VERSION 5.8 ;
BUSBITCHARS "[]" ;
DIVIDERCHAR "/" ;
UNITS
    DATABASE MICRONS 1000 ;
END UNITS

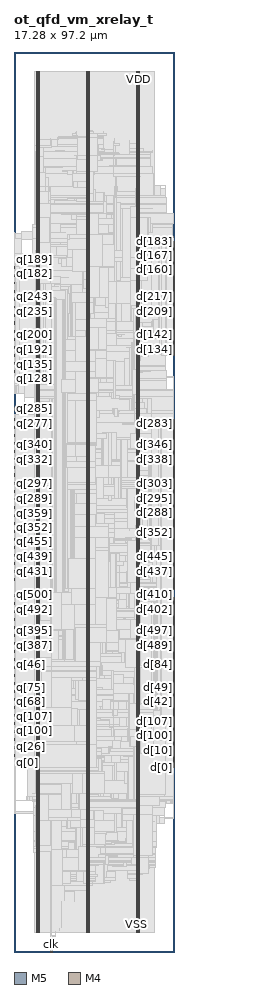
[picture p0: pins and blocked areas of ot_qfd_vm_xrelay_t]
MACRO ot_qfd_vm_xrelay_t
  FOREIGN ot_qfd_vm_xrelay_t 0 0 ;
  CLASS BLOCK ;
  SIZE 17.28 BY 97.2 ;
  PIN clk
    DIRECTION INPUT ;
    USE SIGNAL ;
    PORT
      LAYER M5 ;
        RECT  3.984 0 4.008 0.084 ;
    END
  END clk
  PIN d[0]
    DIRECTION INPUT ;
    USE SIGNAL ;
    PORT
      LAYER M4 ;
        RECT  17.196 19.92 17.28 19.944 ;
    END
  END d[0]
  PIN d[100]
    DIRECTION INPUT ;
    USE SIGNAL ;
    PORT
      LAYER M4 ;
        RECT  17.196 23.376 17.28 23.4 ;
    END
  END d[100]
  PIN d[101]
    DIRECTION INPUT ;
    USE SIGNAL ;
    PORT
      LAYER M4 ;
        RECT  17.196 23.472 17.28 23.496 ;
    END
  END d[101]
  PIN d[102]
    DIRECTION INPUT ;
    USE SIGNAL ;
    PORT
      LAYER M4 ;
        RECT  17.196 23.568 17.28 23.592 ;
    END
  END d[102]
  PIN d[103]
    DIRECTION INPUT ;
    USE SIGNAL ;
    PORT
      LAYER M4 ;
        RECT  17.196 23.664 17.28 23.688 ;
    END
  END d[103]
  PIN d[104]
    DIRECTION INPUT ;
    USE SIGNAL ;
    PORT
      LAYER M4 ;
        RECT  17.196 23.76 17.28 23.784 ;
    END
  END d[104]
  PIN d[105]
    DIRECTION INPUT ;
    USE SIGNAL ;
    PORT
      LAYER M4 ;
        RECT  17.196 23.856 17.28 23.88 ;
    END
  END d[105]
  PIN d[106]
    DIRECTION INPUT ;
    USE SIGNAL ;
    PORT
      LAYER M4 ;
        RECT  17.196 23.952 17.28 23.976 ;
    END
  END d[106]
  PIN d[107]
    DIRECTION INPUT ;
    USE SIGNAL ;
    PORT
      LAYER M4 ;
        RECT  17.196 24.048 17.28 24.072 ;
    END
  END d[107]
  PIN d[108]
    DIRECTION INPUT ;
    USE SIGNAL ;
    PORT
      LAYER M4 ;
        RECT  17.196 24.144 17.28 24.168 ;
    END
  END d[108]
  PIN d[109]
    DIRECTION INPUT ;
    USE SIGNAL ;
    PORT
      LAYER M4 ;
        RECT  17.196 24.24 17.28 24.264 ;
    END
  END d[109]
  PIN d[10]
    DIRECTION INPUT ;
    USE SIGNAL ;
    PORT
      LAYER M4 ;
        RECT  17.196 20.88 17.28 20.904 ;
    END
  END d[10]
  PIN d[110]
    DIRECTION INPUT ;
    USE SIGNAL ;
    PORT
      LAYER M4 ;
        RECT  17.196 24.336 17.28 24.36 ;
    END
  END d[110]
  PIN d[111]
    DIRECTION INPUT ;
    USE SIGNAL ;
    PORT
      LAYER M4 ;
        RECT  17.196 24.432 17.28 24.456 ;
    END
  END d[111]
  PIN d[112]
    DIRECTION INPUT ;
    USE SIGNAL ;
    PORT
      LAYER M4 ;
        RECT  17.196 24.528 17.28 24.552 ;
    END
  END d[112]
  PIN d[113]
    DIRECTION INPUT ;
    USE SIGNAL ;
    PORT
      LAYER M4 ;
        RECT  17.196 24.624 17.28 24.648 ;
    END
  END d[113]
  PIN d[114]
    DIRECTION INPUT ;
    USE SIGNAL ;
    PORT
      LAYER M4 ;
        RECT  17.196 24.72 17.28 24.744 ;
    END
  END d[114]
  PIN d[115]
    DIRECTION INPUT ;
    USE SIGNAL ;
    PORT
      LAYER M4 ;
        RECT  17.196 24.816 17.28 24.84 ;
    END
  END d[115]
  PIN d[116]
    DIRECTION INPUT ;
    USE SIGNAL ;
    PORT
      LAYER M4 ;
        RECT  17.196 24.912 17.28 24.936 ;
    END
  END d[116]
  PIN d[117]
    DIRECTION INPUT ;
    USE SIGNAL ;
    PORT
      LAYER M4 ;
        RECT  17.196 25.008 17.28 25.032 ;
    END
  END d[117]
  PIN d[118]
    DIRECTION INPUT ;
    USE SIGNAL ;
    PORT
      LAYER M4 ;
        RECT  17.196 25.104 17.28 25.128 ;
    END
  END d[118]
  PIN d[119]
    DIRECTION INPUT ;
    USE SIGNAL ;
    PORT
      LAYER M4 ;
        RECT  17.196 25.2 17.28 25.224 ;
    END
  END d[119]
  PIN d[11]
    DIRECTION INPUT ;
    USE SIGNAL ;
    PORT
      LAYER M4 ;
        RECT  17.196 20.976 17.28 21 ;
    END
  END d[11]
  PIN d[120]
    DIRECTION INPUT ;
    USE SIGNAL ;
    PORT
      LAYER M4 ;
        RECT  17.196 25.296 17.28 25.32 ;
    END
  END d[120]
  PIN d[121]
    DIRECTION INPUT ;
    USE SIGNAL ;
    PORT
      LAYER M4 ;
        RECT  17.196 25.392 17.28 25.416 ;
    END
  END d[121]
  PIN d[122]
    DIRECTION INPUT ;
    USE SIGNAL ;
    PORT
      LAYER M4 ;
        RECT  17.196 25.488 17.28 25.512 ;
    END
  END d[122]
  PIN d[123]
    DIRECTION INPUT ;
    USE SIGNAL ;
    PORT
      LAYER M4 ;
        RECT  17.196 25.584 17.28 25.608 ;
    END
  END d[123]
  PIN d[124]
    DIRECTION INPUT ;
    USE SIGNAL ;
    PORT
      LAYER M4 ;
        RECT  17.196 25.68 17.28 25.704 ;
    END
  END d[124]
  PIN d[125]
    DIRECTION INPUT ;
    USE SIGNAL ;
    PORT
      LAYER M4 ;
        RECT  17.196 25.776 17.28 25.8 ;
    END
  END d[125]
  PIN d[126]
    DIRECTION INPUT ;
    USE SIGNAL ;
    PORT
      LAYER M4 ;
        RECT  17.196 25.872 17.28 25.896 ;
    END
  END d[126]
  PIN d[127]
    DIRECTION INPUT ;
    USE SIGNAL ;
    PORT
      LAYER M4 ;
        RECT  17.196 25.968 17.28 25.992 ;
    END
  END d[127]
  PIN d[128]
    DIRECTION INPUT ;
    USE SIGNAL ;
    PORT
      LAYER M4 ;
        RECT  17.196 64.464 17.28 64.488 ;
    END
  END d[128]
  PIN d[129]
    DIRECTION INPUT ;
    USE SIGNAL ;
    PORT
      LAYER M4 ;
        RECT  17.196 64.56 17.28 64.584 ;
    END
  END d[129]
  PIN d[12]
    DIRECTION INPUT ;
    USE SIGNAL ;
    PORT
      LAYER M4 ;
        RECT  17.196 21.072 17.28 21.096 ;
    END
  END d[12]
  PIN d[130]
    DIRECTION INPUT ;
    USE SIGNAL ;
    PORT
      LAYER M4 ;
        RECT  17.196 64.656 17.28 64.68 ;
    END
  END d[130]
  PIN d[131]
    DIRECTION INPUT ;
    USE SIGNAL ;
    PORT
      LAYER M4 ;
        RECT  17.196 64.752 17.28 64.776 ;
    END
  END d[131]
  PIN d[132]
    DIRECTION INPUT ;
    USE SIGNAL ;
    PORT
      LAYER M4 ;
        RECT  17.196 64.848 17.28 64.872 ;
    END
  END d[132]
  PIN d[133]
    DIRECTION INPUT ;
    USE SIGNAL ;
    PORT
      LAYER M4 ;
        RECT  17.196 64.944 17.28 64.968 ;
    END
  END d[133]
  PIN d[134]
    DIRECTION INPUT ;
    USE SIGNAL ;
    PORT
      LAYER M4 ;
        RECT  17.196 65.04 17.28 65.064 ;
    END
  END d[134]
  PIN d[135]
    DIRECTION INPUT ;
    USE SIGNAL ;
    PORT
      LAYER M4 ;
        RECT  17.196 65.136 17.28 65.16 ;
    END
  END d[135]
  PIN d[136]
    DIRECTION INPUT ;
    USE SIGNAL ;
    PORT
      LAYER M4 ;
        RECT  17.196 65.232 17.28 65.256 ;
    END
  END d[136]
  PIN d[137]
    DIRECTION INPUT ;
    USE SIGNAL ;
    PORT
      LAYER M4 ;
        RECT  17.196 65.328 17.28 65.352 ;
    END
  END d[137]
  PIN d[138]
    DIRECTION INPUT ;
    USE SIGNAL ;
    PORT
      LAYER M4 ;
        RECT  17.196 65.424 17.28 65.448 ;
    END
  END d[138]
  PIN d[139]
    DIRECTION INPUT ;
    USE SIGNAL ;
    PORT
      LAYER M4 ;
        RECT  17.196 65.52 17.28 65.544 ;
    END
  END d[139]
  PIN d[13]
    DIRECTION INPUT ;
    USE SIGNAL ;
    PORT
      LAYER M4 ;
        RECT  17.196 21.168 17.28 21.192 ;
    END
  END d[13]
  PIN d[140]
    DIRECTION INPUT ;
    USE SIGNAL ;
    PORT
      LAYER M4 ;
        RECT  17.196 65.616 17.28 65.64 ;
    END
  END d[140]
  PIN d[141]
    DIRECTION INPUT ;
    USE SIGNAL ;
    PORT
      LAYER M4 ;
        RECT  17.196 65.712 17.28 65.736 ;
    END
  END d[141]
  PIN d[142]
    DIRECTION INPUT ;
    USE SIGNAL ;
    PORT
      LAYER M4 ;
        RECT  17.196 65.808 17.28 65.832 ;
    END
  END d[142]
  PIN d[143]
    DIRECTION INPUT ;
    USE SIGNAL ;
    PORT
      LAYER M4 ;
        RECT  17.196 65.904 17.28 65.928 ;
    END
  END d[143]
  PIN d[144]
    DIRECTION INPUT ;
    USE SIGNAL ;
    PORT
      LAYER M4 ;
        RECT  17.196 66 17.28 66.024 ;
    END
  END d[144]
  PIN d[145]
    DIRECTION INPUT ;
    USE SIGNAL ;
    PORT
      LAYER M4 ;
        RECT  17.196 66.096 17.28 66.12 ;
    END
  END d[145]
  PIN d[146]
    DIRECTION INPUT ;
    USE SIGNAL ;
    PORT
      LAYER M4 ;
        RECT  17.196 66.192 17.28 66.216 ;
    END
  END d[146]
  PIN d[147]
    DIRECTION INPUT ;
    USE SIGNAL ;
    PORT
      LAYER M4 ;
        RECT  17.196 66.288 17.28 66.312 ;
    END
  END d[147]
  PIN d[148]
    DIRECTION INPUT ;
    USE SIGNAL ;
    PORT
      LAYER M4 ;
        RECT  17.196 66.384 17.28 66.408 ;
    END
  END d[148]
  PIN d[149]
    DIRECTION INPUT ;
    USE SIGNAL ;
    PORT
      LAYER M4 ;
        RECT  17.196 66.48 17.28 66.504 ;
    END
  END d[149]
  PIN d[14]
    DIRECTION INPUT ;
    USE SIGNAL ;
    PORT
      LAYER M4 ;
        RECT  17.196 21.264 17.28 21.288 ;
    END
  END d[14]
  PIN d[150]
    DIRECTION INPUT ;
    USE SIGNAL ;
    PORT
      LAYER M4 ;
        RECT  17.196 66.576 17.28 66.6 ;
    END
  END d[150]
  PIN d[151]
    DIRECTION INPUT ;
    USE SIGNAL ;
    PORT
      LAYER M4 ;
        RECT  17.196 66.672 17.28 66.696 ;
    END
  END d[151]
  PIN d[152]
    DIRECTION INPUT ;
    USE SIGNAL ;
    PORT
      LAYER M4 ;
        RECT  17.196 66.768 17.28 66.792 ;
    END
  END d[152]
  PIN d[153]
    DIRECTION INPUT ;
    USE SIGNAL ;
    PORT
      LAYER M4 ;
        RECT  17.196 66.864 17.28 66.888 ;
    END
  END d[153]
  PIN d[154]
    DIRECTION INPUT ;
    USE SIGNAL ;
    PORT
      LAYER M4 ;
        RECT  17.196 66.96 17.28 66.984 ;
    END
  END d[154]
  PIN d[155]
    DIRECTION INPUT ;
    USE SIGNAL ;
    PORT
      LAYER M4 ;
        RECT  17.196 67.056 17.28 67.08 ;
    END
  END d[155]
  PIN d[156]
    DIRECTION INPUT ;
    USE SIGNAL ;
    PORT
      LAYER M4 ;
        RECT  17.196 67.152 17.28 67.176 ;
    END
  END d[156]
  PIN d[157]
    DIRECTION INPUT ;
    USE SIGNAL ;
    PORT
      LAYER M4 ;
        RECT  17.196 67.248 17.28 67.272 ;
    END
  END d[157]
  PIN d[158]
    DIRECTION INPUT ;
    USE SIGNAL ;
    PORT
      LAYER M4 ;
        RECT  17.196 67.344 17.28 67.368 ;
    END
  END d[158]
  PIN d[159]
    DIRECTION INPUT ;
    USE SIGNAL ;
    PORT
      LAYER M4 ;
        RECT  17.196 67.44 17.28 67.464 ;
    END
  END d[159]
  PIN d[15]
    DIRECTION INPUT ;
    USE SIGNAL ;
    PORT
      LAYER M4 ;
        RECT  17.196 21.36 17.28 21.384 ;
    END
  END d[15]
  PIN d[160]
    DIRECTION INPUT ;
    USE SIGNAL ;
    PORT
      LAYER M4 ;
        RECT  17.196 73.68 17.28 73.704 ;
    END
  END d[160]
  PIN d[161]
    DIRECTION INPUT ;
    USE SIGNAL ;
    PORT
      LAYER M4 ;
        RECT  17.196 73.776 17.28 73.8 ;
    END
  END d[161]
  PIN d[162]
    DIRECTION INPUT ;
    USE SIGNAL ;
    PORT
      LAYER M4 ;
        RECT  17.196 73.872 17.28 73.896 ;
    END
  END d[162]
  PIN d[163]
    DIRECTION INPUT ;
    USE SIGNAL ;
    PORT
      LAYER M4 ;
        RECT  17.196 73.968 17.28 73.992 ;
    END
  END d[163]
  PIN d[164]
    DIRECTION INPUT ;
    USE SIGNAL ;
    PORT
      LAYER M4 ;
        RECT  17.196 74.064 17.28 74.088 ;
    END
  END d[164]
  PIN d[165]
    DIRECTION INPUT ;
    USE SIGNAL ;
    PORT
      LAYER M4 ;
        RECT  17.196 74.16 17.28 74.184 ;
    END
  END d[165]
  PIN d[166]
    DIRECTION INPUT ;
    USE SIGNAL ;
    PORT
      LAYER M4 ;
        RECT  17.196 74.256 17.28 74.28 ;
    END
  END d[166]
  PIN d[167]
    DIRECTION INPUT ;
    USE SIGNAL ;
    PORT
      LAYER M4 ;
        RECT  17.196 74.352 17.28 74.376 ;
    END
  END d[167]
  PIN d[168]
    DIRECTION INPUT ;
    USE SIGNAL ;
    PORT
      LAYER M4 ;
        RECT  17.196 74.448 17.28 74.472 ;
    END
  END d[168]
  PIN d[169]
    DIRECTION INPUT ;
    USE SIGNAL ;
    PORT
      LAYER M4 ;
        RECT  17.196 74.544 17.28 74.568 ;
    END
  END d[169]
  PIN d[16]
    DIRECTION INPUT ;
    USE SIGNAL ;
    PORT
      LAYER M4 ;
        RECT  17.196 21.456 17.28 21.48 ;
    END
  END d[16]
  PIN d[170]
    DIRECTION INPUT ;
    USE SIGNAL ;
    PORT
      LAYER M4 ;
        RECT  17.196 74.64 17.28 74.664 ;
    END
  END d[170]
  PIN d[171]
    DIRECTION INPUT ;
    USE SIGNAL ;
    PORT
      LAYER M4 ;
        RECT  17.196 74.736 17.28 74.76 ;
    END
  END d[171]
  PIN d[172]
    DIRECTION INPUT ;
    USE SIGNAL ;
    PORT
      LAYER M4 ;
        RECT  17.196 74.832 17.28 74.856 ;
    END
  END d[172]
  PIN d[173]
    DIRECTION INPUT ;
    USE SIGNAL ;
    PORT
      LAYER M4 ;
        RECT  17.196 74.928 17.28 74.952 ;
    END
  END d[173]
  PIN d[174]
    DIRECTION INPUT ;
    USE SIGNAL ;
    PORT
      LAYER M4 ;
        RECT  17.196 75.024 17.28 75.048 ;
    END
  END d[174]
  PIN d[175]
    DIRECTION INPUT ;
    USE SIGNAL ;
    PORT
      LAYER M4 ;
        RECT  17.196 75.12 17.28 75.144 ;
    END
  END d[175]
  PIN d[176]
    DIRECTION INPUT ;
    USE SIGNAL ;
    PORT
      LAYER M4 ;
        RECT  17.196 75.216 17.28 75.24 ;
    END
  END d[176]
  PIN d[177]
    DIRECTION INPUT ;
    USE SIGNAL ;
    PORT
      LAYER M4 ;
        RECT  17.196 75.312 17.28 75.336 ;
    END
  END d[177]
  PIN d[178]
    DIRECTION INPUT ;
    USE SIGNAL ;
    PORT
      LAYER M4 ;
        RECT  17.196 75.408 17.28 75.432 ;
    END
  END d[178]
  PIN d[179]
    DIRECTION INPUT ;
    USE SIGNAL ;
    PORT
      LAYER M4 ;
        RECT  17.196 75.504 17.28 75.528 ;
    END
  END d[179]
  PIN d[17]
    DIRECTION INPUT ;
    USE SIGNAL ;
    PORT
      LAYER M4 ;
        RECT  17.196 21.552 17.28 21.576 ;
    END
  END d[17]
  PIN d[180]
    DIRECTION INPUT ;
    USE SIGNAL ;
    PORT
      LAYER M4 ;
        RECT  17.196 75.6 17.28 75.624 ;
    END
  END d[180]
  PIN d[181]
    DIRECTION INPUT ;
    USE SIGNAL ;
    PORT
      LAYER M4 ;
        RECT  17.196 75.696 17.28 75.72 ;
    END
  END d[181]
  PIN d[182]
    DIRECTION INPUT ;
    USE SIGNAL ;
    PORT
      LAYER M4 ;
        RECT  17.196 75.792 17.28 75.816 ;
    END
  END d[182]
  PIN d[183]
    DIRECTION INPUT ;
    USE SIGNAL ;
    PORT
      LAYER M4 ;
        RECT  17.196 75.888 17.28 75.912 ;
    END
  END d[183]
  PIN d[184]
    DIRECTION INPUT ;
    USE SIGNAL ;
    PORT
      LAYER M4 ;
        RECT  17.196 75.984 17.28 76.008 ;
    END
  END d[184]
  PIN d[185]
    DIRECTION INPUT ;
    USE SIGNAL ;
    PORT
      LAYER M4 ;
        RECT  17.196 76.08 17.28 76.104 ;
    END
  END d[185]
  PIN d[186]
    DIRECTION INPUT ;
    USE SIGNAL ;
    PORT
      LAYER M4 ;
        RECT  17.196 76.176 17.28 76.2 ;
    END
  END d[186]
  PIN d[187]
    DIRECTION INPUT ;
    USE SIGNAL ;
    PORT
      LAYER M4 ;
        RECT  17.196 76.272 17.28 76.296 ;
    END
  END d[187]
  PIN d[188]
    DIRECTION INPUT ;
    USE SIGNAL ;
    PORT
      LAYER M4 ;
        RECT  17.196 76.368 17.28 76.392 ;
    END
  END d[188]
  PIN d[189]
    DIRECTION INPUT ;
    USE SIGNAL ;
    PORT
      LAYER M4 ;
        RECT  17.196 76.464 17.28 76.488 ;
    END
  END d[189]
  PIN d[18]
    DIRECTION INPUT ;
    USE SIGNAL ;
    PORT
      LAYER M4 ;
        RECT  17.196 21.648 17.28 21.672 ;
    END
  END d[18]
  PIN d[190]
    DIRECTION INPUT ;
    USE SIGNAL ;
    PORT
      LAYER M4 ;
        RECT  17.196 76.56 17.28 76.584 ;
    END
  END d[190]
  PIN d[191]
    DIRECTION INPUT ;
    USE SIGNAL ;
    PORT
      LAYER M4 ;
        RECT  17.196 76.656 17.28 76.68 ;
    END
  END d[191]
  PIN d[192]
    DIRECTION INPUT ;
    USE SIGNAL ;
    PORT
      LAYER M4 ;
        RECT  17.196 67.536 17.28 67.56 ;
    END
  END d[192]
  PIN d[193]
    DIRECTION INPUT ;
    USE SIGNAL ;
    PORT
      LAYER M4 ;
        RECT  17.196 67.632 17.28 67.656 ;
    END
  END d[193]
  PIN d[194]
    DIRECTION INPUT ;
    USE SIGNAL ;
    PORT
      LAYER M4 ;
        RECT  17.196 67.728 17.28 67.752 ;
    END
  END d[194]
  PIN d[195]
    DIRECTION INPUT ;
    USE SIGNAL ;
    PORT
      LAYER M4 ;
        RECT  17.196 67.824 17.28 67.848 ;
    END
  END d[195]
  PIN d[196]
    DIRECTION INPUT ;
    USE SIGNAL ;
    PORT
      LAYER M4 ;
        RECT  17.196 67.92 17.28 67.944 ;
    END
  END d[196]
  PIN d[197]
    DIRECTION INPUT ;
    USE SIGNAL ;
    PORT
      LAYER M4 ;
        RECT  17.196 68.016 17.28 68.04 ;
    END
  END d[197]
  PIN d[198]
    DIRECTION INPUT ;
    USE SIGNAL ;
    PORT
      LAYER M4 ;
        RECT  17.196 68.112 17.28 68.136 ;
    END
  END d[198]
  PIN d[199]
    DIRECTION INPUT ;
    USE SIGNAL ;
    PORT
      LAYER M4 ;
        RECT  17.196 68.208 17.28 68.232 ;
    END
  END d[199]
  PIN d[19]
    DIRECTION INPUT ;
    USE SIGNAL ;
    PORT
      LAYER M4 ;
        RECT  17.196 21.744 17.28 21.768 ;
    END
  END d[19]
  PIN d[1]
    DIRECTION INPUT ;
    USE SIGNAL ;
    PORT
      LAYER M4 ;
        RECT  17.196 20.016 17.28 20.04 ;
    END
  END d[1]
  PIN d[200]
    DIRECTION INPUT ;
    USE SIGNAL ;
    PORT
      LAYER M4 ;
        RECT  17.196 68.304 17.28 68.328 ;
    END
  END d[200]
  PIN d[201]
    DIRECTION INPUT ;
    USE SIGNAL ;
    PORT
      LAYER M4 ;
        RECT  17.196 68.4 17.28 68.424 ;
    END
  END d[201]
  PIN d[202]
    DIRECTION INPUT ;
    USE SIGNAL ;
    PORT
      LAYER M4 ;
        RECT  17.196 68.496 17.28 68.52 ;
    END
  END d[202]
  PIN d[203]
    DIRECTION INPUT ;
    USE SIGNAL ;
    PORT
      LAYER M4 ;
        RECT  17.196 68.592 17.28 68.616 ;
    END
  END d[203]
  PIN d[204]
    DIRECTION INPUT ;
    USE SIGNAL ;
    PORT
      LAYER M4 ;
        RECT  17.196 68.688 17.28 68.712 ;
    END
  END d[204]
  PIN d[205]
    DIRECTION INPUT ;
    USE SIGNAL ;
    PORT
      LAYER M4 ;
        RECT  17.196 68.784 17.28 68.808 ;
    END
  END d[205]
  PIN d[206]
    DIRECTION INPUT ;
    USE SIGNAL ;
    PORT
      LAYER M4 ;
        RECT  17.196 68.88 17.28 68.904 ;
    END
  END d[206]
  PIN d[207]
    DIRECTION INPUT ;
    USE SIGNAL ;
    PORT
      LAYER M4 ;
        RECT  17.196 68.976 17.28 69 ;
    END
  END d[207]
  PIN d[208]
    DIRECTION INPUT ;
    USE SIGNAL ;
    PORT
      LAYER M4 ;
        RECT  17.196 69.072 17.28 69.096 ;
    END
  END d[208]
  PIN d[209]
    DIRECTION INPUT ;
    USE SIGNAL ;
    PORT
      LAYER M4 ;
        RECT  17.196 69.168 17.28 69.192 ;
    END
  END d[209]
  PIN d[20]
    DIRECTION INPUT ;
    USE SIGNAL ;
    PORT
      LAYER M4 ;
        RECT  17.196 21.84 17.28 21.864 ;
    END
  END d[20]
  PIN d[210]
    DIRECTION INPUT ;
    USE SIGNAL ;
    PORT
      LAYER M4 ;
        RECT  17.196 69.264 17.28 69.288 ;
    END
  END d[210]
  PIN d[211]
    DIRECTION INPUT ;
    USE SIGNAL ;
    PORT
      LAYER M4 ;
        RECT  17.196 69.36 17.28 69.384 ;
    END
  END d[211]
  PIN d[212]
    DIRECTION INPUT ;
    USE SIGNAL ;
    PORT
      LAYER M4 ;
        RECT  17.196 69.456 17.28 69.48 ;
    END
  END d[212]
  PIN d[213]
    DIRECTION INPUT ;
    USE SIGNAL ;
    PORT
      LAYER M4 ;
        RECT  17.196 69.552 17.28 69.576 ;
    END
  END d[213]
  PIN d[214]
    DIRECTION INPUT ;
    USE SIGNAL ;
    PORT
      LAYER M4 ;
        RECT  17.196 69.648 17.28 69.672 ;
    END
  END d[214]
  PIN d[215]
    DIRECTION INPUT ;
    USE SIGNAL ;
    PORT
      LAYER M4 ;
        RECT  17.196 69.744 17.28 69.768 ;
    END
  END d[215]
  PIN d[216]
    DIRECTION INPUT ;
    USE SIGNAL ;
    PORT
      LAYER M4 ;
        RECT  17.196 69.84 17.28 69.864 ;
    END
  END d[216]
  PIN d[217]
    DIRECTION INPUT ;
    USE SIGNAL ;
    PORT
      LAYER M4 ;
        RECT  17.196 69.936 17.28 69.96 ;
    END
  END d[217]
  PIN d[218]
    DIRECTION INPUT ;
    USE SIGNAL ;
    PORT
      LAYER M4 ;
        RECT  17.196 70.032 17.28 70.056 ;
    END
  END d[218]
  PIN d[219]
    DIRECTION INPUT ;
    USE SIGNAL ;
    PORT
      LAYER M4 ;
        RECT  17.196 70.128 17.28 70.152 ;
    END
  END d[219]
  PIN d[21]
    DIRECTION INPUT ;
    USE SIGNAL ;
    PORT
      LAYER M4 ;
        RECT  17.196 21.936 17.28 21.96 ;
    END
  END d[21]
  PIN d[220]
    DIRECTION INPUT ;
    USE SIGNAL ;
    PORT
      LAYER M4 ;
        RECT  17.196 70.224 17.28 70.248 ;
    END
  END d[220]
  PIN d[221]
    DIRECTION INPUT ;
    USE SIGNAL ;
    PORT
      LAYER M4 ;
        RECT  17.196 70.32 17.28 70.344 ;
    END
  END d[221]
  PIN d[222]
    DIRECTION INPUT ;
    USE SIGNAL ;
    PORT
      LAYER M4 ;
        RECT  17.196 70.416 17.28 70.44 ;
    END
  END d[222]
  PIN d[223]
    DIRECTION INPUT ;
    USE SIGNAL ;
    PORT
      LAYER M4 ;
        RECT  17.196 70.512 17.28 70.536 ;
    END
  END d[223]
  PIN d[224]
    DIRECTION INPUT ;
    USE SIGNAL ;
    PORT
      LAYER M4 ;
        RECT  17.196 70.608 17.28 70.632 ;
    END
  END d[224]
  PIN d[225]
    DIRECTION INPUT ;
    USE SIGNAL ;
    PORT
      LAYER M4 ;
        RECT  17.196 70.704 17.28 70.728 ;
    END
  END d[225]
  PIN d[226]
    DIRECTION INPUT ;
    USE SIGNAL ;
    PORT
      LAYER M4 ;
        RECT  17.196 70.8 17.28 70.824 ;
    END
  END d[226]
  PIN d[227]
    DIRECTION INPUT ;
    USE SIGNAL ;
    PORT
      LAYER M4 ;
        RECT  17.196 70.896 17.28 70.92 ;
    END
  END d[227]
  PIN d[228]
    DIRECTION INPUT ;
    USE SIGNAL ;
    PORT
      LAYER M4 ;
        RECT  17.196 70.992 17.28 71.016 ;
    END
  END d[228]
  PIN d[229]
    DIRECTION INPUT ;
    USE SIGNAL ;
    PORT
      LAYER M4 ;
        RECT  17.196 71.088 17.28 71.112 ;
    END
  END d[229]
  PIN d[22]
    DIRECTION INPUT ;
    USE SIGNAL ;
    PORT
      LAYER M4 ;
        RECT  17.196 22.032 17.28 22.056 ;
    END
  END d[22]
  PIN d[230]
    DIRECTION INPUT ;
    USE SIGNAL ;
    PORT
      LAYER M4 ;
        RECT  17.196 71.184 17.28 71.208 ;
    END
  END d[230]
  PIN d[231]
    DIRECTION INPUT ;
    USE SIGNAL ;
    PORT
      LAYER M4 ;
        RECT  17.196 71.28 17.28 71.304 ;
    END
  END d[231]
  PIN d[232]
    DIRECTION INPUT ;
    USE SIGNAL ;
    PORT
      LAYER M4 ;
        RECT  17.196 71.376 17.28 71.4 ;
    END
  END d[232]
  PIN d[233]
    DIRECTION INPUT ;
    USE SIGNAL ;
    PORT
      LAYER M4 ;
        RECT  17.196 71.472 17.28 71.496 ;
    END
  END d[233]
  PIN d[234]
    DIRECTION INPUT ;
    USE SIGNAL ;
    PORT
      LAYER M4 ;
        RECT  17.196 71.568 17.28 71.592 ;
    END
  END d[234]
  PIN d[235]
    DIRECTION INPUT ;
    USE SIGNAL ;
    PORT
      LAYER M4 ;
        RECT  17.196 71.664 17.28 71.688 ;
    END
  END d[235]
  PIN d[236]
    DIRECTION INPUT ;
    USE SIGNAL ;
    PORT
      LAYER M4 ;
        RECT  17.196 71.76 17.28 71.784 ;
    END
  END d[236]
  PIN d[237]
    DIRECTION INPUT ;
    USE SIGNAL ;
    PORT
      LAYER M4 ;
        RECT  17.196 71.856 17.28 71.88 ;
    END
  END d[237]
  PIN d[238]
    DIRECTION INPUT ;
    USE SIGNAL ;
    PORT
      LAYER M4 ;
        RECT  17.196 71.952 17.28 71.976 ;
    END
  END d[238]
  PIN d[239]
    DIRECTION INPUT ;
    USE SIGNAL ;
    PORT
      LAYER M4 ;
        RECT  17.196 72.048 17.28 72.072 ;
    END
  END d[239]
  PIN d[23]
    DIRECTION INPUT ;
    USE SIGNAL ;
    PORT
      LAYER M4 ;
        RECT  17.196 22.128 17.28 22.152 ;
    END
  END d[23]
  PIN d[240]
    DIRECTION INPUT ;
    USE SIGNAL ;
    PORT
      LAYER M4 ;
        RECT  17.196 72.144 17.28 72.168 ;
    END
  END d[240]
  PIN d[241]
    DIRECTION INPUT ;
    USE SIGNAL ;
    PORT
      LAYER M4 ;
        RECT  17.196 72.24 17.28 72.264 ;
    END
  END d[241]
  PIN d[242]
    DIRECTION INPUT ;
    USE SIGNAL ;
    PORT
      LAYER M4 ;
        RECT  17.196 72.336 17.28 72.36 ;
    END
  END d[242]
  PIN d[243]
    DIRECTION INPUT ;
    USE SIGNAL ;
    PORT
      LAYER M4 ;
        RECT  17.196 72.432 17.28 72.456 ;
    END
  END d[243]
  PIN d[244]
    DIRECTION INPUT ;
    USE SIGNAL ;
    PORT
      LAYER M4 ;
        RECT  17.196 72.528 17.28 72.552 ;
    END
  END d[244]
  PIN d[245]
    DIRECTION INPUT ;
    USE SIGNAL ;
    PORT
      LAYER M4 ;
        RECT  17.196 72.624 17.28 72.648 ;
    END
  END d[245]
  PIN d[246]
    DIRECTION INPUT ;
    USE SIGNAL ;
    PORT
      LAYER M4 ;
        RECT  17.196 72.72 17.28 72.744 ;
    END
  END d[246]
  PIN d[247]
    DIRECTION INPUT ;
    USE SIGNAL ;
    PORT
      LAYER M4 ;
        RECT  17.196 72.816 17.28 72.84 ;
    END
  END d[247]
  PIN d[248]
    DIRECTION INPUT ;
    USE SIGNAL ;
    PORT
      LAYER M4 ;
        RECT  17.196 72.912 17.28 72.936 ;
    END
  END d[248]
  PIN d[249]
    DIRECTION INPUT ;
    USE SIGNAL ;
    PORT
      LAYER M4 ;
        RECT  17.196 73.008 17.28 73.032 ;
    END
  END d[249]
  PIN d[24]
    DIRECTION INPUT ;
    USE SIGNAL ;
    PORT
      LAYER M4 ;
        RECT  17.196 22.224 17.28 22.248 ;
    END
  END d[24]
  PIN d[250]
    DIRECTION INPUT ;
    USE SIGNAL ;
    PORT
      LAYER M4 ;
        RECT  17.196 73.104 17.28 73.128 ;
    END
  END d[250]
  PIN d[251]
    DIRECTION INPUT ;
    USE SIGNAL ;
    PORT
      LAYER M4 ;
        RECT  17.196 73.2 17.28 73.224 ;
    END
  END d[251]
  PIN d[252]
    DIRECTION INPUT ;
    USE SIGNAL ;
    PORT
      LAYER M4 ;
        RECT  17.196 73.296 17.28 73.32 ;
    END
  END d[252]
  PIN d[253]
    DIRECTION INPUT ;
    USE SIGNAL ;
    PORT
      LAYER M4 ;
        RECT  17.196 73.392 17.28 73.416 ;
    END
  END d[253]
  PIN d[254]
    DIRECTION INPUT ;
    USE SIGNAL ;
    PORT
      LAYER M4 ;
        RECT  17.196 73.488 17.28 73.512 ;
    END
  END d[254]
  PIN d[255]
    DIRECTION INPUT ;
    USE SIGNAL ;
    PORT
      LAYER M4 ;
        RECT  17.196 73.584 17.28 73.608 ;
    END
  END d[255]
  PIN d[256]
    DIRECTION INPUT ;
    USE SIGNAL ;
    PORT
      LAYER M4 ;
        RECT  17.196 54.48 17.28 54.504 ;
    END
  END d[256]
  PIN d[257]
    DIRECTION INPUT ;
    USE SIGNAL ;
    PORT
      LAYER M4 ;
        RECT  17.196 54.576 17.28 54.6 ;
    END
  END d[257]
  PIN d[258]
    DIRECTION INPUT ;
    USE SIGNAL ;
    PORT
      LAYER M4 ;
        RECT  17.196 54.672 17.28 54.696 ;
    END
  END d[258]
  PIN d[259]
    DIRECTION INPUT ;
    USE SIGNAL ;
    PORT
      LAYER M4 ;
        RECT  17.196 54.768 17.28 54.792 ;
    END
  END d[259]
  PIN d[25]
    DIRECTION INPUT ;
    USE SIGNAL ;
    PORT
      LAYER M4 ;
        RECT  17.196 22.32 17.28 22.344 ;
    END
  END d[25]
  PIN d[260]
    DIRECTION INPUT ;
    USE SIGNAL ;
    PORT
      LAYER M4 ;
        RECT  17.196 54.864 17.28 54.888 ;
    END
  END d[260]
  PIN d[261]
    DIRECTION INPUT ;
    USE SIGNAL ;
    PORT
      LAYER M4 ;
        RECT  17.196 54.96 17.28 54.984 ;
    END
  END d[261]
  PIN d[262]
    DIRECTION INPUT ;
    USE SIGNAL ;
    PORT
      LAYER M4 ;
        RECT  17.196 55.056 17.28 55.08 ;
    END
  END d[262]
  PIN d[263]
    DIRECTION INPUT ;
    USE SIGNAL ;
    PORT
      LAYER M4 ;
        RECT  17.196 55.152 17.28 55.176 ;
    END
  END d[263]
  PIN d[264]
    DIRECTION INPUT ;
    USE SIGNAL ;
    PORT
      LAYER M4 ;
        RECT  17.196 55.248 17.28 55.272 ;
    END
  END d[264]
  PIN d[265]
    DIRECTION INPUT ;
    USE SIGNAL ;
    PORT
      LAYER M4 ;
        RECT  17.196 55.344 17.28 55.368 ;
    END
  END d[265]
  PIN d[266]
    DIRECTION INPUT ;
    USE SIGNAL ;
    PORT
      LAYER M4 ;
        RECT  17.196 55.44 17.28 55.464 ;
    END
  END d[266]
  PIN d[267]
    DIRECTION INPUT ;
    USE SIGNAL ;
    PORT
      LAYER M4 ;
        RECT  17.196 55.536 17.28 55.56 ;
    END
  END d[267]
  PIN d[268]
    DIRECTION INPUT ;
    USE SIGNAL ;
    PORT
      LAYER M4 ;
        RECT  17.196 55.632 17.28 55.656 ;
    END
  END d[268]
  PIN d[269]
    DIRECTION INPUT ;
    USE SIGNAL ;
    PORT
      LAYER M4 ;
        RECT  17.196 55.728 17.28 55.752 ;
    END
  END d[269]
  PIN d[26]
    DIRECTION INPUT ;
    USE SIGNAL ;
    PORT
      LAYER M4 ;
        RECT  17.196 22.416 17.28 22.44 ;
    END
  END d[26]
  PIN d[270]
    DIRECTION INPUT ;
    USE SIGNAL ;
    PORT
      LAYER M4 ;
        RECT  17.196 55.824 17.28 55.848 ;
    END
  END d[270]
  PIN d[271]
    DIRECTION INPUT ;
    USE SIGNAL ;
    PORT
      LAYER M4 ;
        RECT  17.196 55.92 17.28 55.944 ;
    END
  END d[271]
  PIN d[272]
    DIRECTION INPUT ;
    USE SIGNAL ;
    PORT
      LAYER M4 ;
        RECT  17.196 56.016 17.28 56.04 ;
    END
  END d[272]
  PIN d[273]
    DIRECTION INPUT ;
    USE SIGNAL ;
    PORT
      LAYER M4 ;
        RECT  17.196 56.112 17.28 56.136 ;
    END
  END d[273]
  PIN d[274]
    DIRECTION INPUT ;
    USE SIGNAL ;
    PORT
      LAYER M4 ;
        RECT  17.196 56.208 17.28 56.232 ;
    END
  END d[274]
  PIN d[275]
    DIRECTION INPUT ;
    USE SIGNAL ;
    PORT
      LAYER M4 ;
        RECT  17.196 56.304 17.28 56.328 ;
    END
  END d[275]
  PIN d[276]
    DIRECTION INPUT ;
    USE SIGNAL ;
    PORT
      LAYER M4 ;
        RECT  17.196 56.4 17.28 56.424 ;
    END
  END d[276]
  PIN d[277]
    DIRECTION INPUT ;
    USE SIGNAL ;
    PORT
      LAYER M4 ;
        RECT  17.196 56.496 17.28 56.52 ;
    END
  END d[277]
  PIN d[278]
    DIRECTION INPUT ;
    USE SIGNAL ;
    PORT
      LAYER M4 ;
        RECT  17.196 56.592 17.28 56.616 ;
    END
  END d[278]
  PIN d[279]
    DIRECTION INPUT ;
    USE SIGNAL ;
    PORT
      LAYER M4 ;
        RECT  17.196 56.688 17.28 56.712 ;
    END
  END d[279]
  PIN d[27]
    DIRECTION INPUT ;
    USE SIGNAL ;
    PORT
      LAYER M4 ;
        RECT  17.196 22.512 17.28 22.536 ;
    END
  END d[27]
  PIN d[280]
    DIRECTION INPUT ;
    USE SIGNAL ;
    PORT
      LAYER M4 ;
        RECT  17.196 56.784 17.28 56.808 ;
    END
  END d[280]
  PIN d[281]
    DIRECTION INPUT ;
    USE SIGNAL ;
    PORT
      LAYER M4 ;
        RECT  17.196 56.88 17.28 56.904 ;
    END
  END d[281]
  PIN d[282]
    DIRECTION INPUT ;
    USE SIGNAL ;
    PORT
      LAYER M4 ;
        RECT  17.196 56.976 17.28 57 ;
    END
  END d[282]
  PIN d[283]
    DIRECTION INPUT ;
    USE SIGNAL ;
    PORT
      LAYER M4 ;
        RECT  17.196 57.072 17.28 57.096 ;
    END
  END d[283]
  PIN d[284]
    DIRECTION INPUT ;
    USE SIGNAL ;
    PORT
      LAYER M4 ;
        RECT  17.196 57.168 17.28 57.192 ;
    END
  END d[284]
  PIN d[285]
    DIRECTION INPUT ;
    USE SIGNAL ;
    PORT
      LAYER M4 ;
        RECT  17.196 57.264 17.28 57.288 ;
    END
  END d[285]
  PIN d[286]
    DIRECTION INPUT ;
    USE SIGNAL ;
    PORT
      LAYER M4 ;
        RECT  17.196 57.36 17.28 57.384 ;
    END
  END d[286]
  PIN d[287]
    DIRECTION INPUT ;
    USE SIGNAL ;
    PORT
      LAYER M4 ;
        RECT  17.196 57.456 17.28 57.48 ;
    END
  END d[287]
  PIN d[288]
    DIRECTION INPUT ;
    USE SIGNAL ;
    PORT
      LAYER M4 ;
        RECT  17.196 48.336 17.28 48.36 ;
    END
  END d[288]
  PIN d[289]
    DIRECTION INPUT ;
    USE SIGNAL ;
    PORT
      LAYER M4 ;
        RECT  17.196 48.432 17.28 48.456 ;
    END
  END d[289]
  PIN d[28]
    DIRECTION INPUT ;
    USE SIGNAL ;
    PORT
      LAYER M4 ;
        RECT  17.196 22.608 17.28 22.632 ;
    END
  END d[28]
  PIN d[290]
    DIRECTION INPUT ;
    USE SIGNAL ;
    PORT
      LAYER M4 ;
        RECT  17.196 48.528 17.28 48.552 ;
    END
  END d[290]
  PIN d[291]
    DIRECTION INPUT ;
    USE SIGNAL ;
    PORT
      LAYER M4 ;
        RECT  17.196 48.624 17.28 48.648 ;
    END
  END d[291]
  PIN d[292]
    DIRECTION INPUT ;
    USE SIGNAL ;
    PORT
      LAYER M4 ;
        RECT  17.196 48.72 17.28 48.744 ;
    END
  END d[292]
  PIN d[293]
    DIRECTION INPUT ;
    USE SIGNAL ;
    PORT
      LAYER M4 ;
        RECT  17.196 48.816 17.28 48.84 ;
    END
  END d[293]
  PIN d[294]
    DIRECTION INPUT ;
    USE SIGNAL ;
    PORT
      LAYER M4 ;
        RECT  17.196 48.912 17.28 48.936 ;
    END
  END d[294]
  PIN d[295]
    DIRECTION INPUT ;
    USE SIGNAL ;
    PORT
      LAYER M4 ;
        RECT  17.196 49.008 17.28 49.032 ;
    END
  END d[295]
  PIN d[296]
    DIRECTION INPUT ;
    USE SIGNAL ;
    PORT
      LAYER M4 ;
        RECT  17.196 49.104 17.28 49.128 ;
    END
  END d[296]
  PIN d[297]
    DIRECTION INPUT ;
    USE SIGNAL ;
    PORT
      LAYER M4 ;
        RECT  17.196 49.2 17.28 49.224 ;
    END
  END d[297]
  PIN d[298]
    DIRECTION INPUT ;
    USE SIGNAL ;
    PORT
      LAYER M4 ;
        RECT  17.196 49.296 17.28 49.32 ;
    END
  END d[298]
  PIN d[299]
    DIRECTION INPUT ;
    USE SIGNAL ;
    PORT
      LAYER M4 ;
        RECT  17.196 49.392 17.28 49.416 ;
    END
  END d[299]
  PIN d[29]
    DIRECTION INPUT ;
    USE SIGNAL ;
    PORT
      LAYER M4 ;
        RECT  17.196 22.704 17.28 22.728 ;
    END
  END d[29]
  PIN d[2]
    DIRECTION INPUT ;
    USE SIGNAL ;
    PORT
      LAYER M4 ;
        RECT  17.196 20.112 17.28 20.136 ;
    END
  END d[2]
  PIN d[300]
    DIRECTION INPUT ;
    USE SIGNAL ;
    PORT
      LAYER M4 ;
        RECT  17.196 49.488 17.28 49.512 ;
    END
  END d[300]
  PIN d[301]
    DIRECTION INPUT ;
    USE SIGNAL ;
    PORT
      LAYER M4 ;
        RECT  17.196 49.584 17.28 49.608 ;
    END
  END d[301]
  PIN d[302]
    DIRECTION INPUT ;
    USE SIGNAL ;
    PORT
      LAYER M4 ;
        RECT  17.196 49.68 17.28 49.704 ;
    END
  END d[302]
  PIN d[303]
    DIRECTION INPUT ;
    USE SIGNAL ;
    PORT
      LAYER M4 ;
        RECT  17.196 49.776 17.28 49.8 ;
    END
  END d[303]
  PIN d[304]
    DIRECTION INPUT ;
    USE SIGNAL ;
    PORT
      LAYER M4 ;
        RECT  17.196 49.872 17.28 49.896 ;
    END
  END d[304]
  PIN d[305]
    DIRECTION INPUT ;
    USE SIGNAL ;
    PORT
      LAYER M4 ;
        RECT  17.196 49.968 17.28 49.992 ;
    END
  END d[305]
  PIN d[306]
    DIRECTION INPUT ;
    USE SIGNAL ;
    PORT
      LAYER M4 ;
        RECT  17.196 50.064 17.28 50.088 ;
    END
  END d[306]
  PIN d[307]
    DIRECTION INPUT ;
    USE SIGNAL ;
    PORT
      LAYER M4 ;
        RECT  17.196 50.16 17.28 50.184 ;
    END
  END d[307]
  PIN d[308]
    DIRECTION INPUT ;
    USE SIGNAL ;
    PORT
      LAYER M4 ;
        RECT  17.196 50.256 17.28 50.28 ;
    END
  END d[308]
  PIN d[309]
    DIRECTION INPUT ;
    USE SIGNAL ;
    PORT
      LAYER M4 ;
        RECT  17.196 50.352 17.28 50.376 ;
    END
  END d[309]
  PIN d[30]
    DIRECTION INPUT ;
    USE SIGNAL ;
    PORT
      LAYER M4 ;
        RECT  17.196 22.8 17.28 22.824 ;
    END
  END d[30]
  PIN d[310]
    DIRECTION INPUT ;
    USE SIGNAL ;
    PORT
      LAYER M4 ;
        RECT  17.196 50.448 17.28 50.472 ;
    END
  END d[310]
  PIN d[311]
    DIRECTION INPUT ;
    USE SIGNAL ;
    PORT
      LAYER M4 ;
        RECT  17.196 50.544 17.28 50.568 ;
    END
  END d[311]
  PIN d[312]
    DIRECTION INPUT ;
    USE SIGNAL ;
    PORT
      LAYER M4 ;
        RECT  17.196 50.64 17.28 50.664 ;
    END
  END d[312]
  PIN d[313]
    DIRECTION INPUT ;
    USE SIGNAL ;
    PORT
      LAYER M4 ;
        RECT  17.196 50.736 17.28 50.76 ;
    END
  END d[313]
  PIN d[314]
    DIRECTION INPUT ;
    USE SIGNAL ;
    PORT
      LAYER M4 ;
        RECT  17.196 50.832 17.28 50.856 ;
    END
  END d[314]
  PIN d[315]
    DIRECTION INPUT ;
    USE SIGNAL ;
    PORT
      LAYER M4 ;
        RECT  17.196 50.928 17.28 50.952 ;
    END
  END d[315]
  PIN d[316]
    DIRECTION INPUT ;
    USE SIGNAL ;
    PORT
      LAYER M4 ;
        RECT  17.196 51.024 17.28 51.048 ;
    END
  END d[316]
  PIN d[317]
    DIRECTION INPUT ;
    USE SIGNAL ;
    PORT
      LAYER M4 ;
        RECT  17.196 51.12 17.28 51.144 ;
    END
  END d[317]
  PIN d[318]
    DIRECTION INPUT ;
    USE SIGNAL ;
    PORT
      LAYER M4 ;
        RECT  17.196 51.216 17.28 51.24 ;
    END
  END d[318]
  PIN d[319]
    DIRECTION INPUT ;
    USE SIGNAL ;
    PORT
      LAYER M4 ;
        RECT  17.196 51.312 17.28 51.336 ;
    END
  END d[319]
  PIN d[31]
    DIRECTION INPUT ;
    USE SIGNAL ;
    PORT
      LAYER M4 ;
        RECT  17.196 22.896 17.28 22.92 ;
    END
  END d[31]
  PIN d[320]
    DIRECTION INPUT ;
    USE SIGNAL ;
    PORT
      LAYER M4 ;
        RECT  17.196 51.408 17.28 51.432 ;
    END
  END d[320]
  PIN d[321]
    DIRECTION INPUT ;
    USE SIGNAL ;
    PORT
      LAYER M4 ;
        RECT  17.196 51.504 17.28 51.528 ;
    END
  END d[321]
  PIN d[322]
    DIRECTION INPUT ;
    USE SIGNAL ;
    PORT
      LAYER M4 ;
        RECT  17.196 51.6 17.28 51.624 ;
    END
  END d[322]
  PIN d[323]
    DIRECTION INPUT ;
    USE SIGNAL ;
    PORT
      LAYER M4 ;
        RECT  17.196 51.696 17.28 51.72 ;
    END
  END d[323]
  PIN d[324]
    DIRECTION INPUT ;
    USE SIGNAL ;
    PORT
      LAYER M4 ;
        RECT  17.196 51.792 17.28 51.816 ;
    END
  END d[324]
  PIN d[325]
    DIRECTION INPUT ;
    USE SIGNAL ;
    PORT
      LAYER M4 ;
        RECT  17.196 51.888 17.28 51.912 ;
    END
  END d[325]
  PIN d[326]
    DIRECTION INPUT ;
    USE SIGNAL ;
    PORT
      LAYER M4 ;
        RECT  17.196 51.984 17.28 52.008 ;
    END
  END d[326]
  PIN d[327]
    DIRECTION INPUT ;
    USE SIGNAL ;
    PORT
      LAYER M4 ;
        RECT  17.196 52.08 17.28 52.104 ;
    END
  END d[327]
  PIN d[328]
    DIRECTION INPUT ;
    USE SIGNAL ;
    PORT
      LAYER M4 ;
        RECT  17.196 52.176 17.28 52.2 ;
    END
  END d[328]
  PIN d[329]
    DIRECTION INPUT ;
    USE SIGNAL ;
    PORT
      LAYER M4 ;
        RECT  17.196 52.272 17.28 52.296 ;
    END
  END d[329]
  PIN d[32]
    DIRECTION INPUT ;
    USE SIGNAL ;
    PORT
      LAYER M4 ;
        RECT  17.196 26.064 17.28 26.088 ;
    END
  END d[32]
  PIN d[330]
    DIRECTION INPUT ;
    USE SIGNAL ;
    PORT
      LAYER M4 ;
        RECT  17.196 52.368 17.28 52.392 ;
    END
  END d[330]
  PIN d[331]
    DIRECTION INPUT ;
    USE SIGNAL ;
    PORT
      LAYER M4 ;
        RECT  17.196 52.464 17.28 52.488 ;
    END
  END d[331]
  PIN d[332]
    DIRECTION INPUT ;
    USE SIGNAL ;
    PORT
      LAYER M4 ;
        RECT  17.196 52.56 17.28 52.584 ;
    END
  END d[332]
  PIN d[333]
    DIRECTION INPUT ;
    USE SIGNAL ;
    PORT
      LAYER M4 ;
        RECT  17.196 52.656 17.28 52.68 ;
    END
  END d[333]
  PIN d[334]
    DIRECTION INPUT ;
    USE SIGNAL ;
    PORT
      LAYER M4 ;
        RECT  17.196 52.752 17.28 52.776 ;
    END
  END d[334]
  PIN d[335]
    DIRECTION INPUT ;
    USE SIGNAL ;
    PORT
      LAYER M4 ;
        RECT  17.196 52.848 17.28 52.872 ;
    END
  END d[335]
  PIN d[336]
    DIRECTION INPUT ;
    USE SIGNAL ;
    PORT
      LAYER M4 ;
        RECT  17.196 52.944 17.28 52.968 ;
    END
  END d[336]
  PIN d[337]
    DIRECTION INPUT ;
    USE SIGNAL ;
    PORT
      LAYER M4 ;
        RECT  17.196 53.04 17.28 53.064 ;
    END
  END d[337]
  PIN d[338]
    DIRECTION INPUT ;
    USE SIGNAL ;
    PORT
      LAYER M4 ;
        RECT  17.196 53.136 17.28 53.16 ;
    END
  END d[338]
  PIN d[339]
    DIRECTION INPUT ;
    USE SIGNAL ;
    PORT
      LAYER M4 ;
        RECT  17.196 53.232 17.28 53.256 ;
    END
  END d[339]
  PIN d[33]
    DIRECTION INPUT ;
    USE SIGNAL ;
    PORT
      LAYER M4 ;
        RECT  17.196 26.16 17.28 26.184 ;
    END
  END d[33]
  PIN d[340]
    DIRECTION INPUT ;
    USE SIGNAL ;
    PORT
      LAYER M4 ;
        RECT  17.196 53.328 17.28 53.352 ;
    END
  END d[340]
  PIN d[341]
    DIRECTION INPUT ;
    USE SIGNAL ;
    PORT
      LAYER M4 ;
        RECT  17.196 53.424 17.28 53.448 ;
    END
  END d[341]
  PIN d[342]
    DIRECTION INPUT ;
    USE SIGNAL ;
    PORT
      LAYER M4 ;
        RECT  17.196 53.52 17.28 53.544 ;
    END
  END d[342]
  PIN d[343]
    DIRECTION INPUT ;
    USE SIGNAL ;
    PORT
      LAYER M4 ;
        RECT  17.196 53.616 17.28 53.64 ;
    END
  END d[343]
  PIN d[344]
    DIRECTION INPUT ;
    USE SIGNAL ;
    PORT
      LAYER M4 ;
        RECT  17.196 53.712 17.28 53.736 ;
    END
  END d[344]
  PIN d[345]
    DIRECTION INPUT ;
    USE SIGNAL ;
    PORT
      LAYER M4 ;
        RECT  17.196 53.808 17.28 53.832 ;
    END
  END d[345]
  PIN d[346]
    DIRECTION INPUT ;
    USE SIGNAL ;
    PORT
      LAYER M4 ;
        RECT  17.196 53.904 17.28 53.928 ;
    END
  END d[346]
  PIN d[347]
    DIRECTION INPUT ;
    USE SIGNAL ;
    PORT
      LAYER M4 ;
        RECT  17.196 54 17.28 54.024 ;
    END
  END d[347]
  PIN d[348]
    DIRECTION INPUT ;
    USE SIGNAL ;
    PORT
      LAYER M4 ;
        RECT  17.196 54.096 17.28 54.12 ;
    END
  END d[348]
  PIN d[349]
    DIRECTION INPUT ;
    USE SIGNAL ;
    PORT
      LAYER M4 ;
        RECT  17.196 54.192 17.28 54.216 ;
    END
  END d[349]
  PIN d[34]
    DIRECTION INPUT ;
    USE SIGNAL ;
    PORT
      LAYER M4 ;
        RECT  17.196 26.256 17.28 26.28 ;
    END
  END d[34]
  PIN d[350]
    DIRECTION INPUT ;
    USE SIGNAL ;
    PORT
      LAYER M4 ;
        RECT  17.196 54.288 17.28 54.312 ;
    END
  END d[350]
  PIN d[351]
    DIRECTION INPUT ;
    USE SIGNAL ;
    PORT
      LAYER M4 ;
        RECT  17.196 54.384 17.28 54.408 ;
    END
  END d[351]
  PIN d[352]
    DIRECTION INPUT ;
    USE SIGNAL ;
    PORT
      LAYER M4 ;
        RECT  17.196 45.264 17.28 45.288 ;
    END
  END d[352]
  PIN d[353]
    DIRECTION INPUT ;
    USE SIGNAL ;
    PORT
      LAYER M4 ;
        RECT  17.196 45.36 17.28 45.384 ;
    END
  END d[353]
  PIN d[354]
    DIRECTION INPUT ;
    USE SIGNAL ;
    PORT
      LAYER M4 ;
        RECT  17.196 45.456 17.28 45.48 ;
    END
  END d[354]
  PIN d[355]
    DIRECTION INPUT ;
    USE SIGNAL ;
    PORT
      LAYER M4 ;
        RECT  17.196 45.552 17.28 45.576 ;
    END
  END d[355]
  PIN d[356]
    DIRECTION INPUT ;
    USE SIGNAL ;
    PORT
      LAYER M4 ;
        RECT  17.196 45.648 17.28 45.672 ;
    END
  END d[356]
  PIN d[357]
    DIRECTION INPUT ;
    USE SIGNAL ;
    PORT
      LAYER M4 ;
        RECT  17.196 45.744 17.28 45.768 ;
    END
  END d[357]
  PIN d[358]
    DIRECTION INPUT ;
    USE SIGNAL ;
    PORT
      LAYER M4 ;
        RECT  17.196 45.84 17.28 45.864 ;
    END
  END d[358]
  PIN d[359]
    DIRECTION INPUT ;
    USE SIGNAL ;
    PORT
      LAYER M4 ;
        RECT  17.196 45.936 17.28 45.96 ;
    END
  END d[359]
  PIN d[35]
    DIRECTION INPUT ;
    USE SIGNAL ;
    PORT
      LAYER M4 ;
        RECT  17.196 26.352 17.28 26.376 ;
    END
  END d[35]
  PIN d[360]
    DIRECTION INPUT ;
    USE SIGNAL ;
    PORT
      LAYER M4 ;
        RECT  17.196 46.032 17.28 46.056 ;
    END
  END d[360]
  PIN d[361]
    DIRECTION INPUT ;
    USE SIGNAL ;
    PORT
      LAYER M4 ;
        RECT  17.196 46.128 17.28 46.152 ;
    END
  END d[361]
  PIN d[362]
    DIRECTION INPUT ;
    USE SIGNAL ;
    PORT
      LAYER M4 ;
        RECT  17.196 46.224 17.28 46.248 ;
    END
  END d[362]
  PIN d[363]
    DIRECTION INPUT ;
    USE SIGNAL ;
    PORT
      LAYER M4 ;
        RECT  17.196 46.32 17.28 46.344 ;
    END
  END d[363]
  PIN d[364]
    DIRECTION INPUT ;
    USE SIGNAL ;
    PORT
      LAYER M4 ;
        RECT  17.196 46.416 17.28 46.44 ;
    END
  END d[364]
  PIN d[365]
    DIRECTION INPUT ;
    USE SIGNAL ;
    PORT
      LAYER M4 ;
        RECT  17.196 46.512 17.28 46.536 ;
    END
  END d[365]
  PIN d[366]
    DIRECTION INPUT ;
    USE SIGNAL ;
    PORT
      LAYER M4 ;
        RECT  17.196 46.608 17.28 46.632 ;
    END
  END d[366]
  PIN d[367]
    DIRECTION INPUT ;
    USE SIGNAL ;
    PORT
      LAYER M4 ;
        RECT  17.196 46.704 17.28 46.728 ;
    END
  END d[367]
  PIN d[368]
    DIRECTION INPUT ;
    USE SIGNAL ;
    PORT
      LAYER M4 ;
        RECT  17.196 46.8 17.28 46.824 ;
    END
  END d[368]
  PIN d[369]
    DIRECTION INPUT ;
    USE SIGNAL ;
    PORT
      LAYER M4 ;
        RECT  17.196 46.896 17.28 46.92 ;
    END
  END d[369]
  PIN d[36]
    DIRECTION INPUT ;
    USE SIGNAL ;
    PORT
      LAYER M4 ;
        RECT  17.196 26.448 17.28 26.472 ;
    END
  END d[36]
  PIN d[370]
    DIRECTION INPUT ;
    USE SIGNAL ;
    PORT
      LAYER M4 ;
        RECT  17.196 46.992 17.28 47.016 ;
    END
  END d[370]
  PIN d[371]
    DIRECTION INPUT ;
    USE SIGNAL ;
    PORT
      LAYER M4 ;
        RECT  17.196 47.088 17.28 47.112 ;
    END
  END d[371]
  PIN d[372]
    DIRECTION INPUT ;
    USE SIGNAL ;
    PORT
      LAYER M4 ;
        RECT  17.196 47.184 17.28 47.208 ;
    END
  END d[372]
  PIN d[373]
    DIRECTION INPUT ;
    USE SIGNAL ;
    PORT
      LAYER M4 ;
        RECT  17.196 47.28 17.28 47.304 ;
    END
  END d[373]
  PIN d[374]
    DIRECTION INPUT ;
    USE SIGNAL ;
    PORT
      LAYER M4 ;
        RECT  17.196 47.376 17.28 47.4 ;
    END
  END d[374]
  PIN d[375]
    DIRECTION INPUT ;
    USE SIGNAL ;
    PORT
      LAYER M4 ;
        RECT  17.196 47.472 17.28 47.496 ;
    END
  END d[375]
  PIN d[376]
    DIRECTION INPUT ;
    USE SIGNAL ;
    PORT
      LAYER M4 ;
        RECT  17.196 47.568 17.28 47.592 ;
    END
  END d[376]
  PIN d[377]
    DIRECTION INPUT ;
    USE SIGNAL ;
    PORT
      LAYER M4 ;
        RECT  17.196 47.664 17.28 47.688 ;
    END
  END d[377]
  PIN d[378]
    DIRECTION INPUT ;
    USE SIGNAL ;
    PORT
      LAYER M4 ;
        RECT  17.196 47.76 17.28 47.784 ;
    END
  END d[378]
  PIN d[379]
    DIRECTION INPUT ;
    USE SIGNAL ;
    PORT
      LAYER M4 ;
        RECT  17.196 47.856 17.28 47.88 ;
    END
  END d[379]
  PIN d[37]
    DIRECTION INPUT ;
    USE SIGNAL ;
    PORT
      LAYER M4 ;
        RECT  17.196 26.544 17.28 26.568 ;
    END
  END d[37]
  PIN d[380]
    DIRECTION INPUT ;
    USE SIGNAL ;
    PORT
      LAYER M4 ;
        RECT  17.196 47.952 17.28 47.976 ;
    END
  END d[380]
  PIN d[381]
    DIRECTION INPUT ;
    USE SIGNAL ;
    PORT
      LAYER M4 ;
        RECT  17.196 48.048 17.28 48.072 ;
    END
  END d[381]
  PIN d[382]
    DIRECTION INPUT ;
    USE SIGNAL ;
    PORT
      LAYER M4 ;
        RECT  17.196 48.144 17.28 48.168 ;
    END
  END d[382]
  PIN d[383]
    DIRECTION INPUT ;
    USE SIGNAL ;
    PORT
      LAYER M4 ;
        RECT  17.196 48.24 17.28 48.264 ;
    END
  END d[383]
  PIN d[384]
    DIRECTION INPUT ;
    USE SIGNAL ;
    PORT
      LAYER M4 ;
        RECT  17.196 35.28 17.28 35.304 ;
    END
  END d[384]
  PIN d[385]
    DIRECTION INPUT ;
    USE SIGNAL ;
    PORT
      LAYER M4 ;
        RECT  17.196 35.376 17.28 35.4 ;
    END
  END d[385]
  PIN d[386]
    DIRECTION INPUT ;
    USE SIGNAL ;
    PORT
      LAYER M4 ;
        RECT  17.196 35.472 17.28 35.496 ;
    END
  END d[386]
  PIN d[387]
    DIRECTION INPUT ;
    USE SIGNAL ;
    PORT
      LAYER M4 ;
        RECT  17.196 35.568 17.28 35.592 ;
    END
  END d[387]
  PIN d[388]
    DIRECTION INPUT ;
    USE SIGNAL ;
    PORT
      LAYER M4 ;
        RECT  17.196 35.664 17.28 35.688 ;
    END
  END d[388]
  PIN d[389]
    DIRECTION INPUT ;
    USE SIGNAL ;
    PORT
      LAYER M4 ;
        RECT  17.196 35.76 17.28 35.784 ;
    END
  END d[389]
  PIN d[38]
    DIRECTION INPUT ;
    USE SIGNAL ;
    PORT
      LAYER M4 ;
        RECT  17.196 26.64 17.28 26.664 ;
    END
  END d[38]
  PIN d[390]
    DIRECTION INPUT ;
    USE SIGNAL ;
    PORT
      LAYER M4 ;
        RECT  17.196 35.856 17.28 35.88 ;
    END
  END d[390]
  PIN d[391]
    DIRECTION INPUT ;
    USE SIGNAL ;
    PORT
      LAYER M4 ;
        RECT  17.196 35.952 17.28 35.976 ;
    END
  END d[391]
  PIN d[392]
    DIRECTION INPUT ;
    USE SIGNAL ;
    PORT
      LAYER M4 ;
        RECT  17.196 36.048 17.28 36.072 ;
    END
  END d[392]
  PIN d[393]
    DIRECTION INPUT ;
    USE SIGNAL ;
    PORT
      LAYER M4 ;
        RECT  17.196 36.144 17.28 36.168 ;
    END
  END d[393]
  PIN d[394]
    DIRECTION INPUT ;
    USE SIGNAL ;
    PORT
      LAYER M4 ;
        RECT  17.196 36.24 17.28 36.264 ;
    END
  END d[394]
  PIN d[395]
    DIRECTION INPUT ;
    USE SIGNAL ;
    PORT
      LAYER M4 ;
        RECT  17.196 36.336 17.28 36.36 ;
    END
  END d[395]
  PIN d[396]
    DIRECTION INPUT ;
    USE SIGNAL ;
    PORT
      LAYER M4 ;
        RECT  17.196 36.432 17.28 36.456 ;
    END
  END d[396]
  PIN d[397]
    DIRECTION INPUT ;
    USE SIGNAL ;
    PORT
      LAYER M4 ;
        RECT  17.196 36.528 17.28 36.552 ;
    END
  END d[397]
  PIN d[398]
    DIRECTION INPUT ;
    USE SIGNAL ;
    PORT
      LAYER M4 ;
        RECT  17.196 36.624 17.28 36.648 ;
    END
  END d[398]
  PIN d[399]
    DIRECTION INPUT ;
    USE SIGNAL ;
    PORT
      LAYER M4 ;
        RECT  17.196 36.72 17.28 36.744 ;
    END
  END d[399]
  PIN d[39]
    DIRECTION INPUT ;
    USE SIGNAL ;
    PORT
      LAYER M4 ;
        RECT  17.196 26.736 17.28 26.76 ;
    END
  END d[39]
  PIN d[3]
    DIRECTION INPUT ;
    USE SIGNAL ;
    PORT
      LAYER M4 ;
        RECT  17.196 20.208 17.28 20.232 ;
    END
  END d[3]
  PIN d[400]
    DIRECTION INPUT ;
    USE SIGNAL ;
    PORT
      LAYER M4 ;
        RECT  17.196 36.816 17.28 36.84 ;
    END
  END d[400]
  PIN d[401]
    DIRECTION INPUT ;
    USE SIGNAL ;
    PORT
      LAYER M4 ;
        RECT  17.196 36.912 17.28 36.936 ;
    END
  END d[401]
  PIN d[402]
    DIRECTION INPUT ;
    USE SIGNAL ;
    PORT
      LAYER M4 ;
        RECT  17.196 37.008 17.28 37.032 ;
    END
  END d[402]
  PIN d[403]
    DIRECTION INPUT ;
    USE SIGNAL ;
    PORT
      LAYER M4 ;
        RECT  17.196 37.104 17.28 37.128 ;
    END
  END d[403]
  PIN d[404]
    DIRECTION INPUT ;
    USE SIGNAL ;
    PORT
      LAYER M4 ;
        RECT  17.196 37.2 17.28 37.224 ;
    END
  END d[404]
  PIN d[405]
    DIRECTION INPUT ;
    USE SIGNAL ;
    PORT
      LAYER M4 ;
        RECT  17.196 37.296 17.28 37.32 ;
    END
  END d[405]
  PIN d[406]
    DIRECTION INPUT ;
    USE SIGNAL ;
    PORT
      LAYER M4 ;
        RECT  17.196 37.392 17.28 37.416 ;
    END
  END d[406]
  PIN d[407]
    DIRECTION INPUT ;
    USE SIGNAL ;
    PORT
      LAYER M4 ;
        RECT  17.196 37.488 17.28 37.512 ;
    END
  END d[407]
  PIN d[408]
    DIRECTION INPUT ;
    USE SIGNAL ;
    PORT
      LAYER M4 ;
        RECT  17.196 37.584 17.28 37.608 ;
    END
  END d[408]
  PIN d[409]
    DIRECTION INPUT ;
    USE SIGNAL ;
    PORT
      LAYER M4 ;
        RECT  17.196 37.68 17.28 37.704 ;
    END
  END d[409]
  PIN d[40]
    DIRECTION INPUT ;
    USE SIGNAL ;
    PORT
      LAYER M4 ;
        RECT  17.196 26.832 17.28 26.856 ;
    END
  END d[40]
  PIN d[410]
    DIRECTION INPUT ;
    USE SIGNAL ;
    PORT
      LAYER M4 ;
        RECT  17.196 37.776 17.28 37.8 ;
    END
  END d[410]
  PIN d[411]
    DIRECTION INPUT ;
    USE SIGNAL ;
    PORT
      LAYER M4 ;
        RECT  17.196 37.872 17.28 37.896 ;
    END
  END d[411]
  PIN d[412]
    DIRECTION INPUT ;
    USE SIGNAL ;
    PORT
      LAYER M4 ;
        RECT  17.196 37.968 17.28 37.992 ;
    END
  END d[412]
  PIN d[413]
    DIRECTION INPUT ;
    USE SIGNAL ;
    PORT
      LAYER M4 ;
        RECT  17.196 38.064 17.28 38.088 ;
    END
  END d[413]
  PIN d[414]
    DIRECTION INPUT ;
    USE SIGNAL ;
    PORT
      LAYER M4 ;
        RECT  17.196 38.16 17.28 38.184 ;
    END
  END d[414]
  PIN d[415]
    DIRECTION INPUT ;
    USE SIGNAL ;
    PORT
      LAYER M4 ;
        RECT  17.196 38.256 17.28 38.28 ;
    END
  END d[415]
  PIN d[416]
    DIRECTION INPUT ;
    USE SIGNAL ;
    PORT
      LAYER M4 ;
        RECT  17.196 39.12 17.28 39.144 ;
    END
  END d[416]
  PIN d[417]
    DIRECTION INPUT ;
    USE SIGNAL ;
    PORT
      LAYER M4 ;
        RECT  17.196 39.216 17.28 39.24 ;
    END
  END d[417]
  PIN d[418]
    DIRECTION INPUT ;
    USE SIGNAL ;
    PORT
      LAYER M4 ;
        RECT  17.196 39.312 17.28 39.336 ;
    END
  END d[418]
  PIN d[419]
    DIRECTION INPUT ;
    USE SIGNAL ;
    PORT
      LAYER M4 ;
        RECT  17.196 39.408 17.28 39.432 ;
    END
  END d[419]
  PIN d[41]
    DIRECTION INPUT ;
    USE SIGNAL ;
    PORT
      LAYER M4 ;
        RECT  17.196 26.928 17.28 26.952 ;
    END
  END d[41]
  PIN d[420]
    DIRECTION INPUT ;
    USE SIGNAL ;
    PORT
      LAYER M4 ;
        RECT  17.196 39.504 17.28 39.528 ;
    END
  END d[420]
  PIN d[421]
    DIRECTION INPUT ;
    USE SIGNAL ;
    PORT
      LAYER M4 ;
        RECT  17.196 39.6 17.28 39.624 ;
    END
  END d[421]
  PIN d[422]
    DIRECTION INPUT ;
    USE SIGNAL ;
    PORT
      LAYER M4 ;
        RECT  17.196 39.696 17.28 39.72 ;
    END
  END d[422]
  PIN d[423]
    DIRECTION INPUT ;
    USE SIGNAL ;
    PORT
      LAYER M4 ;
        RECT  17.196 39.792 17.28 39.816 ;
    END
  END d[423]
  PIN d[424]
    DIRECTION INPUT ;
    USE SIGNAL ;
    PORT
      LAYER M4 ;
        RECT  17.196 39.888 17.28 39.912 ;
    END
  END d[424]
  PIN d[425]
    DIRECTION INPUT ;
    USE SIGNAL ;
    PORT
      LAYER M4 ;
        RECT  17.196 39.984 17.28 40.008 ;
    END
  END d[425]
  PIN d[426]
    DIRECTION INPUT ;
    USE SIGNAL ;
    PORT
      LAYER M4 ;
        RECT  17.196 40.08 17.28 40.104 ;
    END
  END d[426]
  PIN d[427]
    DIRECTION INPUT ;
    USE SIGNAL ;
    PORT
      LAYER M4 ;
        RECT  17.196 40.176 17.28 40.2 ;
    END
  END d[427]
  PIN d[428]
    DIRECTION INPUT ;
    USE SIGNAL ;
    PORT
      LAYER M4 ;
        RECT  17.196 40.272 17.28 40.296 ;
    END
  END d[428]
  PIN d[429]
    DIRECTION INPUT ;
    USE SIGNAL ;
    PORT
      LAYER M4 ;
        RECT  17.196 40.368 17.28 40.392 ;
    END
  END d[429]
  PIN d[42]
    DIRECTION INPUT ;
    USE SIGNAL ;
    PORT
      LAYER M4 ;
        RECT  17.196 27.024 17.28 27.048 ;
    END
  END d[42]
  PIN d[430]
    DIRECTION INPUT ;
    USE SIGNAL ;
    PORT
      LAYER M4 ;
        RECT  17.196 40.464 17.28 40.488 ;
    END
  END d[430]
  PIN d[431]
    DIRECTION INPUT ;
    USE SIGNAL ;
    PORT
      LAYER M4 ;
        RECT  17.196 40.56 17.28 40.584 ;
    END
  END d[431]
  PIN d[432]
    DIRECTION INPUT ;
    USE SIGNAL ;
    PORT
      LAYER M4 ;
        RECT  17.196 40.656 17.28 40.68 ;
    END
  END d[432]
  PIN d[433]
    DIRECTION INPUT ;
    USE SIGNAL ;
    PORT
      LAYER M4 ;
        RECT  17.196 40.752 17.28 40.776 ;
    END
  END d[433]
  PIN d[434]
    DIRECTION INPUT ;
    USE SIGNAL ;
    PORT
      LAYER M4 ;
        RECT  17.196 40.848 17.28 40.872 ;
    END
  END d[434]
  PIN d[435]
    DIRECTION INPUT ;
    USE SIGNAL ;
    PORT
      LAYER M4 ;
        RECT  17.196 40.944 17.28 40.968 ;
    END
  END d[435]
  PIN d[436]
    DIRECTION INPUT ;
    USE SIGNAL ;
    PORT
      LAYER M4 ;
        RECT  17.196 41.04 17.28 41.064 ;
    END
  END d[436]
  PIN d[437]
    DIRECTION INPUT ;
    USE SIGNAL ;
    PORT
      LAYER M4 ;
        RECT  17.196 41.136 17.28 41.16 ;
    END
  END d[437]
  PIN d[438]
    DIRECTION INPUT ;
    USE SIGNAL ;
    PORT
      LAYER M4 ;
        RECT  17.196 41.232 17.28 41.256 ;
    END
  END d[438]
  PIN d[439]
    DIRECTION INPUT ;
    USE SIGNAL ;
    PORT
      LAYER M4 ;
        RECT  17.196 41.328 17.28 41.352 ;
    END
  END d[439]
  PIN d[43]
    DIRECTION INPUT ;
    USE SIGNAL ;
    PORT
      LAYER M4 ;
        RECT  17.196 27.12 17.28 27.144 ;
    END
  END d[43]
  PIN d[440]
    DIRECTION INPUT ;
    USE SIGNAL ;
    PORT
      LAYER M4 ;
        RECT  17.196 41.424 17.28 41.448 ;
    END
  END d[440]
  PIN d[441]
    DIRECTION INPUT ;
    USE SIGNAL ;
    PORT
      LAYER M4 ;
        RECT  17.196 41.52 17.28 41.544 ;
    END
  END d[441]
  PIN d[442]
    DIRECTION INPUT ;
    USE SIGNAL ;
    PORT
      LAYER M4 ;
        RECT  17.196 41.616 17.28 41.64 ;
    END
  END d[442]
  PIN d[443]
    DIRECTION INPUT ;
    USE SIGNAL ;
    PORT
      LAYER M4 ;
        RECT  17.196 41.712 17.28 41.736 ;
    END
  END d[443]
  PIN d[444]
    DIRECTION INPUT ;
    USE SIGNAL ;
    PORT
      LAYER M4 ;
        RECT  17.196 41.808 17.28 41.832 ;
    END
  END d[444]
  PIN d[445]
    DIRECTION INPUT ;
    USE SIGNAL ;
    PORT
      LAYER M4 ;
        RECT  17.196 41.904 17.28 41.928 ;
    END
  END d[445]
  PIN d[446]
    DIRECTION INPUT ;
    USE SIGNAL ;
    PORT
      LAYER M4 ;
        RECT  17.196 42 17.28 42.024 ;
    END
  END d[446]
  PIN d[447]
    DIRECTION INPUT ;
    USE SIGNAL ;
    PORT
      LAYER M4 ;
        RECT  17.196 42.096 17.28 42.12 ;
    END
  END d[447]
  PIN d[448]
    DIRECTION INPUT ;
    USE SIGNAL ;
    PORT
      LAYER M4 ;
        RECT  17.196 42.192 17.28 42.216 ;
    END
  END d[448]
  PIN d[449]
    DIRECTION INPUT ;
    USE SIGNAL ;
    PORT
      LAYER M4 ;
        RECT  17.196 42.288 17.28 42.312 ;
    END
  END d[449]
  PIN d[44]
    DIRECTION INPUT ;
    USE SIGNAL ;
    PORT
      LAYER M4 ;
        RECT  17.196 27.216 17.28 27.24 ;
    END
  END d[44]
  PIN d[450]
    DIRECTION INPUT ;
    USE SIGNAL ;
    PORT
      LAYER M4 ;
        RECT  17.196 42.384 17.28 42.408 ;
    END
  END d[450]
  PIN d[451]
    DIRECTION INPUT ;
    USE SIGNAL ;
    PORT
      LAYER M4 ;
        RECT  17.196 42.48 17.28 42.504 ;
    END
  END d[451]
  PIN d[452]
    DIRECTION INPUT ;
    USE SIGNAL ;
    PORT
      LAYER M4 ;
        RECT  17.196 42.576 17.28 42.6 ;
    END
  END d[452]
  PIN d[453]
    DIRECTION INPUT ;
    USE SIGNAL ;
    PORT
      LAYER M4 ;
        RECT  17.196 42.672 17.28 42.696 ;
    END
  END d[453]
  PIN d[454]
    DIRECTION INPUT ;
    USE SIGNAL ;
    PORT
      LAYER M4 ;
        RECT  17.196 42.768 17.28 42.792 ;
    END
  END d[454]
  PIN d[455]
    DIRECTION INPUT ;
    USE SIGNAL ;
    PORT
      LAYER M4 ;
        RECT  17.196 42.864 17.28 42.888 ;
    END
  END d[455]
  PIN d[456]
    DIRECTION INPUT ;
    USE SIGNAL ;
    PORT
      LAYER M4 ;
        RECT  17.196 42.96 17.28 42.984 ;
    END
  END d[456]
  PIN d[457]
    DIRECTION INPUT ;
    USE SIGNAL ;
    PORT
      LAYER M4 ;
        RECT  17.196 43.056 17.28 43.08 ;
    END
  END d[457]
  PIN d[458]
    DIRECTION INPUT ;
    USE SIGNAL ;
    PORT
      LAYER M4 ;
        RECT  17.196 43.152 17.28 43.176 ;
    END
  END d[458]
  PIN d[459]
    DIRECTION INPUT ;
    USE SIGNAL ;
    PORT
      LAYER M4 ;
        RECT  17.196 43.248 17.28 43.272 ;
    END
  END d[459]
  PIN d[45]
    DIRECTION INPUT ;
    USE SIGNAL ;
    PORT
      LAYER M4 ;
        RECT  17.196 27.312 17.28 27.336 ;
    END
  END d[45]
  PIN d[460]
    DIRECTION INPUT ;
    USE SIGNAL ;
    PORT
      LAYER M4 ;
        RECT  17.196 43.344 17.28 43.368 ;
    END
  END d[460]
  PIN d[461]
    DIRECTION INPUT ;
    USE SIGNAL ;
    PORT
      LAYER M4 ;
        RECT  17.196 43.44 17.28 43.464 ;
    END
  END d[461]
  PIN d[462]
    DIRECTION INPUT ;
    USE SIGNAL ;
    PORT
      LAYER M4 ;
        RECT  17.196 43.536 17.28 43.56 ;
    END
  END d[462]
  PIN d[463]
    DIRECTION INPUT ;
    USE SIGNAL ;
    PORT
      LAYER M4 ;
        RECT  17.196 43.632 17.28 43.656 ;
    END
  END d[463]
  PIN d[464]
    DIRECTION INPUT ;
    USE SIGNAL ;
    PORT
      LAYER M4 ;
        RECT  17.196 43.728 17.28 43.752 ;
    END
  END d[464]
  PIN d[465]
    DIRECTION INPUT ;
    USE SIGNAL ;
    PORT
      LAYER M4 ;
        RECT  17.196 43.824 17.28 43.848 ;
    END
  END d[465]
  PIN d[466]
    DIRECTION INPUT ;
    USE SIGNAL ;
    PORT
      LAYER M4 ;
        RECT  17.196 43.92 17.28 43.944 ;
    END
  END d[466]
  PIN d[467]
    DIRECTION INPUT ;
    USE SIGNAL ;
    PORT
      LAYER M4 ;
        RECT  17.196 44.016 17.28 44.04 ;
    END
  END d[467]
  PIN d[468]
    DIRECTION INPUT ;
    USE SIGNAL ;
    PORT
      LAYER M4 ;
        RECT  17.196 44.112 17.28 44.136 ;
    END
  END d[468]
  PIN d[469]
    DIRECTION INPUT ;
    USE SIGNAL ;
    PORT
      LAYER M4 ;
        RECT  17.196 44.208 17.28 44.232 ;
    END
  END d[469]
  PIN d[46]
    DIRECTION INPUT ;
    USE SIGNAL ;
    PORT
      LAYER M4 ;
        RECT  17.196 27.408 17.28 27.432 ;
    END
  END d[46]
  PIN d[470]
    DIRECTION INPUT ;
    USE SIGNAL ;
    PORT
      LAYER M4 ;
        RECT  17.196 44.304 17.28 44.328 ;
    END
  END d[470]
  PIN d[471]
    DIRECTION INPUT ;
    USE SIGNAL ;
    PORT
      LAYER M4 ;
        RECT  17.196 44.4 17.28 44.424 ;
    END
  END d[471]
  PIN d[472]
    DIRECTION INPUT ;
    USE SIGNAL ;
    PORT
      LAYER M4 ;
        RECT  17.196 44.496 17.28 44.52 ;
    END
  END d[472]
  PIN d[473]
    DIRECTION INPUT ;
    USE SIGNAL ;
    PORT
      LAYER M4 ;
        RECT  17.196 44.592 17.28 44.616 ;
    END
  END d[473]
  PIN d[474]
    DIRECTION INPUT ;
    USE SIGNAL ;
    PORT
      LAYER M4 ;
        RECT  17.196 44.688 17.28 44.712 ;
    END
  END d[474]
  PIN d[475]
    DIRECTION INPUT ;
    USE SIGNAL ;
    PORT
      LAYER M4 ;
        RECT  17.196 44.784 17.28 44.808 ;
    END
  END d[475]
  PIN d[476]
    DIRECTION INPUT ;
    USE SIGNAL ;
    PORT
      LAYER M4 ;
        RECT  17.196 44.88 17.28 44.904 ;
    END
  END d[476]
  PIN d[477]
    DIRECTION INPUT ;
    USE SIGNAL ;
    PORT
      LAYER M4 ;
        RECT  17.196 44.976 17.28 45 ;
    END
  END d[477]
  PIN d[478]
    DIRECTION INPUT ;
    USE SIGNAL ;
    PORT
      LAYER M4 ;
        RECT  17.196 45.072 17.28 45.096 ;
    END
  END d[478]
  PIN d[479]
    DIRECTION INPUT ;
    USE SIGNAL ;
    PORT
      LAYER M4 ;
        RECT  17.196 45.168 17.28 45.192 ;
    END
  END d[479]
  PIN d[47]
    DIRECTION INPUT ;
    USE SIGNAL ;
    PORT
      LAYER M4 ;
        RECT  17.196 27.504 17.28 27.528 ;
    END
  END d[47]
  PIN d[480]
    DIRECTION INPUT ;
    USE SIGNAL ;
    PORT
      LAYER M4 ;
        RECT  17.196 32.208 17.28 32.232 ;
    END
  END d[480]
  PIN d[481]
    DIRECTION INPUT ;
    USE SIGNAL ;
    PORT
      LAYER M4 ;
        RECT  17.196 32.304 17.28 32.328 ;
    END
  END d[481]
  PIN d[482]
    DIRECTION INPUT ;
    USE SIGNAL ;
    PORT
      LAYER M4 ;
        RECT  17.196 32.4 17.28 32.424 ;
    END
  END d[482]
  PIN d[483]
    DIRECTION INPUT ;
    USE SIGNAL ;
    PORT
      LAYER M4 ;
        RECT  17.196 32.496 17.28 32.52 ;
    END
  END d[483]
  PIN d[484]
    DIRECTION INPUT ;
    USE SIGNAL ;
    PORT
      LAYER M4 ;
        RECT  17.196 32.592 17.28 32.616 ;
    END
  END d[484]
  PIN d[485]
    DIRECTION INPUT ;
    USE SIGNAL ;
    PORT
      LAYER M4 ;
        RECT  17.196 32.688 17.28 32.712 ;
    END
  END d[485]
  PIN d[486]
    DIRECTION INPUT ;
    USE SIGNAL ;
    PORT
      LAYER M4 ;
        RECT  17.196 32.784 17.28 32.808 ;
    END
  END d[486]
  PIN d[487]
    DIRECTION INPUT ;
    USE SIGNAL ;
    PORT
      LAYER M4 ;
        RECT  17.196 32.88 17.28 32.904 ;
    END
  END d[487]
  PIN d[488]
    DIRECTION INPUT ;
    USE SIGNAL ;
    PORT
      LAYER M4 ;
        RECT  17.196 32.976 17.28 33 ;
    END
  END d[488]
  PIN d[489]
    DIRECTION INPUT ;
    USE SIGNAL ;
    PORT
      LAYER M4 ;
        RECT  17.196 33.072 17.28 33.096 ;
    END
  END d[489]
  PIN d[48]
    DIRECTION INPUT ;
    USE SIGNAL ;
    PORT
      LAYER M4 ;
        RECT  17.196 27.6 17.28 27.624 ;
    END
  END d[48]
  PIN d[490]
    DIRECTION INPUT ;
    USE SIGNAL ;
    PORT
      LAYER M4 ;
        RECT  17.196 33.168 17.28 33.192 ;
    END
  END d[490]
  PIN d[491]
    DIRECTION INPUT ;
    USE SIGNAL ;
    PORT
      LAYER M4 ;
        RECT  17.196 33.264 17.28 33.288 ;
    END
  END d[491]
  PIN d[492]
    DIRECTION INPUT ;
    USE SIGNAL ;
    PORT
      LAYER M4 ;
        RECT  17.196 33.36 17.28 33.384 ;
    END
  END d[492]
  PIN d[493]
    DIRECTION INPUT ;
    USE SIGNAL ;
    PORT
      LAYER M4 ;
        RECT  17.196 33.456 17.28 33.48 ;
    END
  END d[493]
  PIN d[494]
    DIRECTION INPUT ;
    USE SIGNAL ;
    PORT
      LAYER M4 ;
        RECT  17.196 33.552 17.28 33.576 ;
    END
  END d[494]
  PIN d[495]
    DIRECTION INPUT ;
    USE SIGNAL ;
    PORT
      LAYER M4 ;
        RECT  17.196 33.648 17.28 33.672 ;
    END
  END d[495]
  PIN d[496]
    DIRECTION INPUT ;
    USE SIGNAL ;
    PORT
      LAYER M4 ;
        RECT  17.196 33.744 17.28 33.768 ;
    END
  END d[496]
  PIN d[497]
    DIRECTION INPUT ;
    USE SIGNAL ;
    PORT
      LAYER M4 ;
        RECT  17.196 33.84 17.28 33.864 ;
    END
  END d[497]
  PIN d[498]
    DIRECTION INPUT ;
    USE SIGNAL ;
    PORT
      LAYER M4 ;
        RECT  17.196 33.936 17.28 33.96 ;
    END
  END d[498]
  PIN d[499]
    DIRECTION INPUT ;
    USE SIGNAL ;
    PORT
      LAYER M4 ;
        RECT  17.196 34.032 17.28 34.056 ;
    END
  END d[499]
  PIN d[49]
    DIRECTION INPUT ;
    USE SIGNAL ;
    PORT
      LAYER M4 ;
        RECT  17.196 27.696 17.28 27.72 ;
    END
  END d[49]
  PIN d[4]
    DIRECTION INPUT ;
    USE SIGNAL ;
    PORT
      LAYER M4 ;
        RECT  17.196 20.304 17.28 20.328 ;
    END
  END d[4]
  PIN d[500]
    DIRECTION INPUT ;
    USE SIGNAL ;
    PORT
      LAYER M4 ;
        RECT  17.196 34.128 17.28 34.152 ;
    END
  END d[500]
  PIN d[501]
    DIRECTION INPUT ;
    USE SIGNAL ;
    PORT
      LAYER M4 ;
        RECT  17.196 34.224 17.28 34.248 ;
    END
  END d[501]
  PIN d[502]
    DIRECTION INPUT ;
    USE SIGNAL ;
    PORT
      LAYER M4 ;
        RECT  17.196 34.32 17.28 34.344 ;
    END
  END d[502]
  PIN d[503]
    DIRECTION INPUT ;
    USE SIGNAL ;
    PORT
      LAYER M4 ;
        RECT  17.196 34.416 17.28 34.44 ;
    END
  END d[503]
  PIN d[504]
    DIRECTION INPUT ;
    USE SIGNAL ;
    PORT
      LAYER M4 ;
        RECT  17.196 34.512 17.28 34.536 ;
    END
  END d[504]
  PIN d[505]
    DIRECTION INPUT ;
    USE SIGNAL ;
    PORT
      LAYER M4 ;
        RECT  17.196 34.608 17.28 34.632 ;
    END
  END d[505]
  PIN d[506]
    DIRECTION INPUT ;
    USE SIGNAL ;
    PORT
      LAYER M4 ;
        RECT  17.196 34.704 17.28 34.728 ;
    END
  END d[506]
  PIN d[507]
    DIRECTION INPUT ;
    USE SIGNAL ;
    PORT
      LAYER M4 ;
        RECT  17.196 34.8 17.28 34.824 ;
    END
  END d[507]
  PIN d[508]
    DIRECTION INPUT ;
    USE SIGNAL ;
    PORT
      LAYER M4 ;
        RECT  17.196 34.896 17.28 34.92 ;
    END
  END d[508]
  PIN d[509]
    DIRECTION INPUT ;
    USE SIGNAL ;
    PORT
      LAYER M4 ;
        RECT  17.196 34.992 17.28 35.016 ;
    END
  END d[509]
  PIN d[50]
    DIRECTION INPUT ;
    USE SIGNAL ;
    PORT
      LAYER M4 ;
        RECT  17.196 27.792 17.28 27.816 ;
    END
  END d[50]
  PIN d[510]
    DIRECTION INPUT ;
    USE SIGNAL ;
    PORT
      LAYER M4 ;
        RECT  17.196 35.088 17.28 35.112 ;
    END
  END d[510]
  PIN d[511]
    DIRECTION INPUT ;
    USE SIGNAL ;
    PORT
      LAYER M4 ;
        RECT  17.196 35.184 17.28 35.208 ;
    END
  END d[511]
  PIN d[51]
    DIRECTION INPUT ;
    USE SIGNAL ;
    PORT
      LAYER M4 ;
        RECT  17.196 27.888 17.28 27.912 ;
    END
  END d[51]
  PIN d[52]
    DIRECTION INPUT ;
    USE SIGNAL ;
    PORT
      LAYER M4 ;
        RECT  17.196 27.984 17.28 28.008 ;
    END
  END d[52]
  PIN d[53]
    DIRECTION INPUT ;
    USE SIGNAL ;
    PORT
      LAYER M4 ;
        RECT  17.196 28.08 17.28 28.104 ;
    END
  END d[53]
  PIN d[54]
    DIRECTION INPUT ;
    USE SIGNAL ;
    PORT
      LAYER M4 ;
        RECT  17.196 28.176 17.28 28.2 ;
    END
  END d[54]
  PIN d[55]
    DIRECTION INPUT ;
    USE SIGNAL ;
    PORT
      LAYER M4 ;
        RECT  17.196 28.272 17.28 28.296 ;
    END
  END d[55]
  PIN d[56]
    DIRECTION INPUT ;
    USE SIGNAL ;
    PORT
      LAYER M4 ;
        RECT  17.196 28.368 17.28 28.392 ;
    END
  END d[56]
  PIN d[57]
    DIRECTION INPUT ;
    USE SIGNAL ;
    PORT
      LAYER M4 ;
        RECT  17.196 28.464 17.28 28.488 ;
    END
  END d[57]
  PIN d[58]
    DIRECTION INPUT ;
    USE SIGNAL ;
    PORT
      LAYER M4 ;
        RECT  17.196 28.56 17.28 28.584 ;
    END
  END d[58]
  PIN d[59]
    DIRECTION INPUT ;
    USE SIGNAL ;
    PORT
      LAYER M4 ;
        RECT  17.196 28.656 17.28 28.68 ;
    END
  END d[59]
  PIN d[5]
    DIRECTION INPUT ;
    USE SIGNAL ;
    PORT
      LAYER M4 ;
        RECT  17.196 20.4 17.28 20.424 ;
    END
  END d[5]
  PIN d[60]
    DIRECTION INPUT ;
    USE SIGNAL ;
    PORT
      LAYER M4 ;
        RECT  17.196 28.752 17.28 28.776 ;
    END
  END d[60]
  PIN d[61]
    DIRECTION INPUT ;
    USE SIGNAL ;
    PORT
      LAYER M4 ;
        RECT  17.196 28.848 17.28 28.872 ;
    END
  END d[61]
  PIN d[62]
    DIRECTION INPUT ;
    USE SIGNAL ;
    PORT
      LAYER M4 ;
        RECT  17.196 28.944 17.28 28.968 ;
    END
  END d[62]
  PIN d[63]
    DIRECTION INPUT ;
    USE SIGNAL ;
    PORT
      LAYER M4 ;
        RECT  17.196 29.04 17.28 29.064 ;
    END
  END d[63]
  PIN d[64]
    DIRECTION INPUT ;
    USE SIGNAL ;
    PORT
      LAYER M4 ;
        RECT  17.196 29.136 17.28 29.16 ;
    END
  END d[64]
  PIN d[65]
    DIRECTION INPUT ;
    USE SIGNAL ;
    PORT
      LAYER M4 ;
        RECT  17.196 29.232 17.28 29.256 ;
    END
  END d[65]
  PIN d[66]
    DIRECTION INPUT ;
    USE SIGNAL ;
    PORT
      LAYER M4 ;
        RECT  17.196 29.328 17.28 29.352 ;
    END
  END d[66]
  PIN d[67]
    DIRECTION INPUT ;
    USE SIGNAL ;
    PORT
      LAYER M4 ;
        RECT  17.196 29.424 17.28 29.448 ;
    END
  END d[67]
  PIN d[68]
    DIRECTION INPUT ;
    USE SIGNAL ;
    PORT
      LAYER M4 ;
        RECT  17.196 29.52 17.28 29.544 ;
    END
  END d[68]
  PIN d[69]
    DIRECTION INPUT ;
    USE SIGNAL ;
    PORT
      LAYER M4 ;
        RECT  17.196 29.616 17.28 29.64 ;
    END
  END d[69]
  PIN d[6]
    DIRECTION INPUT ;
    USE SIGNAL ;
    PORT
      LAYER M4 ;
        RECT  17.196 20.496 17.28 20.52 ;
    END
  END d[6]
  PIN d[70]
    DIRECTION INPUT ;
    USE SIGNAL ;
    PORT
      LAYER M4 ;
        RECT  17.196 29.712 17.28 29.736 ;
    END
  END d[70]
  PIN d[71]
    DIRECTION INPUT ;
    USE SIGNAL ;
    PORT
      LAYER M4 ;
        RECT  17.196 29.808 17.28 29.832 ;
    END
  END d[71]
  PIN d[72]
    DIRECTION INPUT ;
    USE SIGNAL ;
    PORT
      LAYER M4 ;
        RECT  17.196 29.904 17.28 29.928 ;
    END
  END d[72]
  PIN d[73]
    DIRECTION INPUT ;
    USE SIGNAL ;
    PORT
      LAYER M4 ;
        RECT  17.196 30 17.28 30.024 ;
    END
  END d[73]
  PIN d[74]
    DIRECTION INPUT ;
    USE SIGNAL ;
    PORT
      LAYER M4 ;
        RECT  17.196 30.096 17.28 30.12 ;
    END
  END d[74]
  PIN d[75]
    DIRECTION INPUT ;
    USE SIGNAL ;
    PORT
      LAYER M4 ;
        RECT  17.196 30.192 17.28 30.216 ;
    END
  END d[75]
  PIN d[76]
    DIRECTION INPUT ;
    USE SIGNAL ;
    PORT
      LAYER M4 ;
        RECT  17.196 30.288 17.28 30.312 ;
    END
  END d[76]
  PIN d[77]
    DIRECTION INPUT ;
    USE SIGNAL ;
    PORT
      LAYER M4 ;
        RECT  17.196 30.384 17.28 30.408 ;
    END
  END d[77]
  PIN d[78]
    DIRECTION INPUT ;
    USE SIGNAL ;
    PORT
      LAYER M4 ;
        RECT  17.196 30.48 17.28 30.504 ;
    END
  END d[78]
  PIN d[79]
    DIRECTION INPUT ;
    USE SIGNAL ;
    PORT
      LAYER M4 ;
        RECT  17.196 30.576 17.28 30.6 ;
    END
  END d[79]
  PIN d[7]
    DIRECTION INPUT ;
    USE SIGNAL ;
    PORT
      LAYER M4 ;
        RECT  17.196 20.592 17.28 20.616 ;
    END
  END d[7]
  PIN d[80]
    DIRECTION INPUT ;
    USE SIGNAL ;
    PORT
      LAYER M4 ;
        RECT  17.196 30.672 17.28 30.696 ;
    END
  END d[80]
  PIN d[81]
    DIRECTION INPUT ;
    USE SIGNAL ;
    PORT
      LAYER M4 ;
        RECT  17.196 30.768 17.28 30.792 ;
    END
  END d[81]
  PIN d[82]
    DIRECTION INPUT ;
    USE SIGNAL ;
    PORT
      LAYER M4 ;
        RECT  17.196 30.864 17.28 30.888 ;
    END
  END d[82]
  PIN d[83]
    DIRECTION INPUT ;
    USE SIGNAL ;
    PORT
      LAYER M4 ;
        RECT  17.196 30.96 17.28 30.984 ;
    END
  END d[83]
  PIN d[84]
    DIRECTION INPUT ;
    USE SIGNAL ;
    PORT
      LAYER M4 ;
        RECT  17.196 31.056 17.28 31.08 ;
    END
  END d[84]
  PIN d[85]
    DIRECTION INPUT ;
    USE SIGNAL ;
    PORT
      LAYER M4 ;
        RECT  17.196 31.152 17.28 31.176 ;
    END
  END d[85]
  PIN d[86]
    DIRECTION INPUT ;
    USE SIGNAL ;
    PORT
      LAYER M4 ;
        RECT  17.196 31.248 17.28 31.272 ;
    END
  END d[86]
  PIN d[87]
    DIRECTION INPUT ;
    USE SIGNAL ;
    PORT
      LAYER M4 ;
        RECT  17.196 31.344 17.28 31.368 ;
    END
  END d[87]
  PIN d[88]
    DIRECTION INPUT ;
    USE SIGNAL ;
    PORT
      LAYER M4 ;
        RECT  17.196 31.44 17.28 31.464 ;
    END
  END d[88]
  PIN d[89]
    DIRECTION INPUT ;
    USE SIGNAL ;
    PORT
      LAYER M4 ;
        RECT  17.196 31.536 17.28 31.56 ;
    END
  END d[89]
  PIN d[8]
    DIRECTION INPUT ;
    USE SIGNAL ;
    PORT
      LAYER M4 ;
        RECT  17.196 20.688 17.28 20.712 ;
    END
  END d[8]
  PIN d[90]
    DIRECTION INPUT ;
    USE SIGNAL ;
    PORT
      LAYER M4 ;
        RECT  17.196 31.632 17.28 31.656 ;
    END
  END d[90]
  PIN d[91]
    DIRECTION INPUT ;
    USE SIGNAL ;
    PORT
      LAYER M4 ;
        RECT  17.196 31.728 17.28 31.752 ;
    END
  END d[91]
  PIN d[92]
    DIRECTION INPUT ;
    USE SIGNAL ;
    PORT
      LAYER M4 ;
        RECT  17.196 31.824 17.28 31.848 ;
    END
  END d[92]
  PIN d[93]
    DIRECTION INPUT ;
    USE SIGNAL ;
    PORT
      LAYER M4 ;
        RECT  17.196 31.92 17.28 31.944 ;
    END
  END d[93]
  PIN d[94]
    DIRECTION INPUT ;
    USE SIGNAL ;
    PORT
      LAYER M4 ;
        RECT  17.196 32.016 17.28 32.04 ;
    END
  END d[94]
  PIN d[95]
    DIRECTION INPUT ;
    USE SIGNAL ;
    PORT
      LAYER M4 ;
        RECT  17.196 32.112 17.28 32.136 ;
    END
  END d[95]
  PIN d[96]
    DIRECTION INPUT ;
    USE SIGNAL ;
    PORT
      LAYER M4 ;
        RECT  17.196 22.992 17.28 23.016 ;
    END
  END d[96]
  PIN d[97]
    DIRECTION INPUT ;
    USE SIGNAL ;
    PORT
      LAYER M4 ;
        RECT  17.196 23.088 17.28 23.112 ;
    END
  END d[97]
  PIN d[98]
    DIRECTION INPUT ;
    USE SIGNAL ;
    PORT
      LAYER M4 ;
        RECT  17.196 23.184 17.28 23.208 ;
    END
  END d[98]
  PIN d[99]
    DIRECTION INPUT ;
    USE SIGNAL ;
    PORT
      LAYER M4 ;
        RECT  17.196 23.28 17.28 23.304 ;
    END
  END d[99]
  PIN d[9]
    DIRECTION INPUT ;
    USE SIGNAL ;
    PORT
      LAYER M4 ;
        RECT  17.196 20.784 17.28 20.808 ;
    END
  END d[9]
  PIN me_e
    DIRECTION INPUT ;
    USE SIGNAL ;
    PORT
      LAYER M5 ;
        RECT  4.08 0 4.104 0.084 ;
    END
  END me_e
  PIN q[0]
    DIRECTION OUTPUT ;
    USE SIGNAL ;
    PORT
      LAYER M4 ;
        RECT  0 20.496 0.084 20.52 ;
    END
  END q[0]
  PIN q[100]
    DIRECTION OUTPUT ;
    USE SIGNAL ;
    PORT
      LAYER M4 ;
        RECT  0 23.952 0.084 23.976 ;
    END
  END q[100]
  PIN q[101]
    DIRECTION OUTPUT ;
    USE SIGNAL ;
    PORT
      LAYER M4 ;
        RECT  0 24.048 0.084 24.072 ;
    END
  END q[101]
  PIN q[102]
    DIRECTION OUTPUT ;
    USE SIGNAL ;
    PORT
      LAYER M4 ;
        RECT  0 24.144 0.084 24.168 ;
    END
  END q[102]
  PIN q[103]
    DIRECTION OUTPUT ;
    USE SIGNAL ;
    PORT
      LAYER M4 ;
        RECT  0 24.24 0.084 24.264 ;
    END
  END q[103]
  PIN q[104]
    DIRECTION OUTPUT ;
    USE SIGNAL ;
    PORT
      LAYER M4 ;
        RECT  0 24.336 0.084 24.36 ;
    END
  END q[104]
  PIN q[105]
    DIRECTION OUTPUT ;
    USE SIGNAL ;
    PORT
      LAYER M4 ;
        RECT  0 24.432 0.084 24.456 ;
    END
  END q[105]
  PIN q[106]
    DIRECTION OUTPUT ;
    USE SIGNAL ;
    PORT
      LAYER M4 ;
        RECT  0 24.528 0.084 24.552 ;
    END
  END q[106]
  PIN q[107]
    DIRECTION OUTPUT ;
    USE SIGNAL ;
    PORT
      LAYER M4 ;
        RECT  0 24.624 0.084 24.648 ;
    END
  END q[107]
  PIN q[108]
    DIRECTION OUTPUT ;
    USE SIGNAL ;
    PORT
      LAYER M4 ;
        RECT  0 24.72 0.084 24.744 ;
    END
  END q[108]
  PIN q[109]
    DIRECTION OUTPUT ;
    USE SIGNAL ;
    PORT
      LAYER M4 ;
        RECT  0 24.816 0.084 24.84 ;
    END
  END q[109]
  PIN q[10]
    DIRECTION OUTPUT ;
    USE SIGNAL ;
    PORT
      LAYER M4 ;
        RECT  0 21.456 0.084 21.48 ;
    END
  END q[10]
  PIN q[110]
    DIRECTION OUTPUT ;
    USE SIGNAL ;
    PORT
      LAYER M4 ;
        RECT  0 24.912 0.084 24.936 ;
    END
  END q[110]
  PIN q[111]
    DIRECTION OUTPUT ;
    USE SIGNAL ;
    PORT
      LAYER M4 ;
        RECT  0 25.008 0.084 25.032 ;
    END
  END q[111]
  PIN q[112]
    DIRECTION OUTPUT ;
    USE SIGNAL ;
    PORT
      LAYER M4 ;
        RECT  0 25.104 0.084 25.128 ;
    END
  END q[112]
  PIN q[113]
    DIRECTION OUTPUT ;
    USE SIGNAL ;
    PORT
      LAYER M4 ;
        RECT  0 25.2 0.084 25.224 ;
    END
  END q[113]
  PIN q[114]
    DIRECTION OUTPUT ;
    USE SIGNAL ;
    PORT
      LAYER M4 ;
        RECT  0 25.296 0.084 25.32 ;
    END
  END q[114]
  PIN q[115]
    DIRECTION OUTPUT ;
    USE SIGNAL ;
    PORT
      LAYER M4 ;
        RECT  0 25.392 0.084 25.416 ;
    END
  END q[115]
  PIN q[116]
    DIRECTION OUTPUT ;
    USE SIGNAL ;
    PORT
      LAYER M4 ;
        RECT  0 25.488 0.084 25.512 ;
    END
  END q[116]
  PIN q[117]
    DIRECTION OUTPUT ;
    USE SIGNAL ;
    PORT
      LAYER M4 ;
        RECT  0 25.584 0.084 25.608 ;
    END
  END q[117]
  PIN q[118]
    DIRECTION OUTPUT ;
    USE SIGNAL ;
    PORT
      LAYER M4 ;
        RECT  0 25.68 0.084 25.704 ;
    END
  END q[118]
  PIN q[119]
    DIRECTION OUTPUT ;
    USE SIGNAL ;
    PORT
      LAYER M4 ;
        RECT  0 25.776 0.084 25.8 ;
    END
  END q[119]
  PIN q[11]
    DIRECTION OUTPUT ;
    USE SIGNAL ;
    PORT
      LAYER M4 ;
        RECT  0 21.552 0.084 21.576 ;
    END
  END q[11]
  PIN q[120]
    DIRECTION OUTPUT ;
    USE SIGNAL ;
    PORT
      LAYER M4 ;
        RECT  0 25.872 0.084 25.896 ;
    END
  END q[120]
  PIN q[121]
    DIRECTION OUTPUT ;
    USE SIGNAL ;
    PORT
      LAYER M4 ;
        RECT  0 25.968 0.084 25.992 ;
    END
  END q[121]
  PIN q[122]
    DIRECTION OUTPUT ;
    USE SIGNAL ;
    PORT
      LAYER M4 ;
        RECT  0 26.064 0.084 26.088 ;
    END
  END q[122]
  PIN q[123]
    DIRECTION OUTPUT ;
    USE SIGNAL ;
    PORT
      LAYER M4 ;
        RECT  0 26.16 0.084 26.184 ;
    END
  END q[123]
  PIN q[124]
    DIRECTION OUTPUT ;
    USE SIGNAL ;
    PORT
      LAYER M4 ;
        RECT  0 26.256 0.084 26.28 ;
    END
  END q[124]
  PIN q[125]
    DIRECTION OUTPUT ;
    USE SIGNAL ;
    PORT
      LAYER M4 ;
        RECT  0 26.352 0.084 26.376 ;
    END
  END q[125]
  PIN q[126]
    DIRECTION OUTPUT ;
    USE SIGNAL ;
    PORT
      LAYER M4 ;
        RECT  0 26.448 0.084 26.472 ;
    END
  END q[126]
  PIN q[127]
    DIRECTION OUTPUT ;
    USE SIGNAL ;
    PORT
      LAYER M4 ;
        RECT  0 26.544 0.084 26.568 ;
    END
  END q[127]
  PIN q[128]
    DIRECTION OUTPUT ;
    USE SIGNAL ;
    PORT
      LAYER M4 ;
        RECT  0 61.968 0.084 61.992 ;
    END
  END q[128]
  PIN q[129]
    DIRECTION OUTPUT ;
    USE SIGNAL ;
    PORT
      LAYER M4 ;
        RECT  0 62.064 0.084 62.088 ;
    END
  END q[129]
  PIN q[12]
    DIRECTION OUTPUT ;
    USE SIGNAL ;
    PORT
      LAYER M4 ;
        RECT  0 21.648 0.084 21.672 ;
    END
  END q[12]
  PIN q[130]
    DIRECTION OUTPUT ;
    USE SIGNAL ;
    PORT
      LAYER M4 ;
        RECT  0 62.16 0.084 62.184 ;
    END
  END q[130]
  PIN q[131]
    DIRECTION OUTPUT ;
    USE SIGNAL ;
    PORT
      LAYER M4 ;
        RECT  0 62.256 0.084 62.28 ;
    END
  END q[131]
  PIN q[132]
    DIRECTION OUTPUT ;
    USE SIGNAL ;
    PORT
      LAYER M4 ;
        RECT  0 62.352 0.084 62.376 ;
    END
  END q[132]
  PIN q[133]
    DIRECTION OUTPUT ;
    USE SIGNAL ;
    PORT
      LAYER M4 ;
        RECT  0 62.448 0.084 62.472 ;
    END
  END q[133]
  PIN q[134]
    DIRECTION OUTPUT ;
    USE SIGNAL ;
    PORT
      LAYER M4 ;
        RECT  0 62.544 0.084 62.568 ;
    END
  END q[134]
  PIN q[135]
    DIRECTION OUTPUT ;
    USE SIGNAL ;
    PORT
      LAYER M4 ;
        RECT  0 62.64 0.084 62.664 ;
    END
  END q[135]
  PIN q[136]
    DIRECTION OUTPUT ;
    USE SIGNAL ;
    PORT
      LAYER M4 ;
        RECT  0 62.736 0.084 62.76 ;
    END
  END q[136]
  PIN q[137]
    DIRECTION OUTPUT ;
    USE SIGNAL ;
    PORT
      LAYER M4 ;
        RECT  0 62.832 0.084 62.856 ;
    END
  END q[137]
  PIN q[138]
    DIRECTION OUTPUT ;
    USE SIGNAL ;
    PORT
      LAYER M4 ;
        RECT  0 62.928 0.084 62.952 ;
    END
  END q[138]
  PIN q[139]
    DIRECTION OUTPUT ;
    USE SIGNAL ;
    PORT
      LAYER M4 ;
        RECT  0 63.024 0.084 63.048 ;
    END
  END q[139]
  PIN q[13]
    DIRECTION OUTPUT ;
    USE SIGNAL ;
    PORT
      LAYER M4 ;
        RECT  0 21.744 0.084 21.768 ;
    END
  END q[13]
  PIN q[140]
    DIRECTION OUTPUT ;
    USE SIGNAL ;
    PORT
      LAYER M4 ;
        RECT  0 63.12 0.084 63.144 ;
    END
  END q[140]
  PIN q[141]
    DIRECTION OUTPUT ;
    USE SIGNAL ;
    PORT
      LAYER M4 ;
        RECT  0 63.216 0.084 63.24 ;
    END
  END q[141]
  PIN q[142]
    DIRECTION OUTPUT ;
    USE SIGNAL ;
    PORT
      LAYER M4 ;
        RECT  0 63.312 0.084 63.336 ;
    END
  END q[142]
  PIN q[143]
    DIRECTION OUTPUT ;
    USE SIGNAL ;
    PORT
      LAYER M4 ;
        RECT  0 63.408 0.084 63.432 ;
    END
  END q[143]
  PIN q[144]
    DIRECTION OUTPUT ;
    USE SIGNAL ;
    PORT
      LAYER M4 ;
        RECT  0 63.504 0.084 63.528 ;
    END
  END q[144]
  PIN q[145]
    DIRECTION OUTPUT ;
    USE SIGNAL ;
    PORT
      LAYER M4 ;
        RECT  0 63.6 0.084 63.624 ;
    END
  END q[145]
  PIN q[146]
    DIRECTION OUTPUT ;
    USE SIGNAL ;
    PORT
      LAYER M4 ;
        RECT  0 63.696 0.084 63.72 ;
    END
  END q[146]
  PIN q[147]
    DIRECTION OUTPUT ;
    USE SIGNAL ;
    PORT
      LAYER M4 ;
        RECT  0 63.792 0.084 63.816 ;
    END
  END q[147]
  PIN q[148]
    DIRECTION OUTPUT ;
    USE SIGNAL ;
    PORT
      LAYER M4 ;
        RECT  0 63.888 0.084 63.912 ;
    END
  END q[148]
  PIN q[149]
    DIRECTION OUTPUT ;
    USE SIGNAL ;
    PORT
      LAYER M4 ;
        RECT  0 63.984 0.084 64.008 ;
    END
  END q[149]
  PIN q[14]
    DIRECTION OUTPUT ;
    USE SIGNAL ;
    PORT
      LAYER M4 ;
        RECT  0 21.84 0.084 21.864 ;
    END
  END q[14]
  PIN q[150]
    DIRECTION OUTPUT ;
    USE SIGNAL ;
    PORT
      LAYER M4 ;
        RECT  0 64.08 0.084 64.104 ;
    END
  END q[150]
  PIN q[151]
    DIRECTION OUTPUT ;
    USE SIGNAL ;
    PORT
      LAYER M4 ;
        RECT  0 64.176 0.084 64.2 ;
    END
  END q[151]
  PIN q[152]
    DIRECTION OUTPUT ;
    USE SIGNAL ;
    PORT
      LAYER M4 ;
        RECT  0 64.272 0.084 64.296 ;
    END
  END q[152]
  PIN q[153]
    DIRECTION OUTPUT ;
    USE SIGNAL ;
    PORT
      LAYER M4 ;
        RECT  0 64.368 0.084 64.392 ;
    END
  END q[153]
  PIN q[154]
    DIRECTION OUTPUT ;
    USE SIGNAL ;
    PORT
      LAYER M4 ;
        RECT  0 64.464 0.084 64.488 ;
    END
  END q[154]
  PIN q[155]
    DIRECTION OUTPUT ;
    USE SIGNAL ;
    PORT
      LAYER M4 ;
        RECT  0 64.56 0.084 64.584 ;
    END
  END q[155]
  PIN q[156]
    DIRECTION OUTPUT ;
    USE SIGNAL ;
    PORT
      LAYER M4 ;
        RECT  0 64.656 0.084 64.68 ;
    END
  END q[156]
  PIN q[157]
    DIRECTION OUTPUT ;
    USE SIGNAL ;
    PORT
      LAYER M4 ;
        RECT  0 64.752 0.084 64.776 ;
    END
  END q[157]
  PIN q[158]
    DIRECTION OUTPUT ;
    USE SIGNAL ;
    PORT
      LAYER M4 ;
        RECT  0 64.848 0.084 64.872 ;
    END
  END q[158]
  PIN q[159]
    DIRECTION OUTPUT ;
    USE SIGNAL ;
    PORT
      LAYER M4 ;
        RECT  0 64.944 0.084 64.968 ;
    END
  END q[159]
  PIN q[15]
    DIRECTION OUTPUT ;
    USE SIGNAL ;
    PORT
      LAYER M4 ;
        RECT  0 21.936 0.084 21.96 ;
    END
  END q[15]
  PIN q[160]
    DIRECTION OUTPUT ;
    USE SIGNAL ;
    PORT
      LAYER M4 ;
        RECT  0 71.184 0.084 71.208 ;
    END
  END q[160]
  PIN q[161]
    DIRECTION OUTPUT ;
    USE SIGNAL ;
    PORT
      LAYER M4 ;
        RECT  0 71.28 0.084 71.304 ;
    END
  END q[161]
  PIN q[162]
    DIRECTION OUTPUT ;
    USE SIGNAL ;
    PORT
      LAYER M4 ;
        RECT  0 71.376 0.084 71.4 ;
    END
  END q[162]
  PIN q[163]
    DIRECTION OUTPUT ;
    USE SIGNAL ;
    PORT
      LAYER M4 ;
        RECT  0 71.472 0.084 71.496 ;
    END
  END q[163]
  PIN q[164]
    DIRECTION OUTPUT ;
    USE SIGNAL ;
    PORT
      LAYER M4 ;
        RECT  0 71.568 0.084 71.592 ;
    END
  END q[164]
  PIN q[165]
    DIRECTION OUTPUT ;
    USE SIGNAL ;
    PORT
      LAYER M4 ;
        RECT  0 71.664 0.084 71.688 ;
    END
  END q[165]
  PIN q[166]
    DIRECTION OUTPUT ;
    USE SIGNAL ;
    PORT
      LAYER M4 ;
        RECT  0 71.76 0.084 71.784 ;
    END
  END q[166]
  PIN q[167]
    DIRECTION OUTPUT ;
    USE SIGNAL ;
    PORT
      LAYER M4 ;
        RECT  0 71.856 0.084 71.88 ;
    END
  END q[167]
  PIN q[168]
    DIRECTION OUTPUT ;
    USE SIGNAL ;
    PORT
      LAYER M4 ;
        RECT  0 71.952 0.084 71.976 ;
    END
  END q[168]
  PIN q[169]
    DIRECTION OUTPUT ;
    USE SIGNAL ;
    PORT
      LAYER M4 ;
        RECT  0 72.048 0.084 72.072 ;
    END
  END q[169]
  PIN q[16]
    DIRECTION OUTPUT ;
    USE SIGNAL ;
    PORT
      LAYER M4 ;
        RECT  0 22.032 0.084 22.056 ;
    END
  END q[16]
  PIN q[170]
    DIRECTION OUTPUT ;
    USE SIGNAL ;
    PORT
      LAYER M4 ;
        RECT  0 72.144 0.084 72.168 ;
    END
  END q[170]
  PIN q[171]
    DIRECTION OUTPUT ;
    USE SIGNAL ;
    PORT
      LAYER M4 ;
        RECT  0 72.24 0.084 72.264 ;
    END
  END q[171]
  PIN q[172]
    DIRECTION OUTPUT ;
    USE SIGNAL ;
    PORT
      LAYER M4 ;
        RECT  0 72.336 0.084 72.36 ;
    END
  END q[172]
  PIN q[173]
    DIRECTION OUTPUT ;
    USE SIGNAL ;
    PORT
      LAYER M4 ;
        RECT  0 72.432 0.084 72.456 ;
    END
  END q[173]
  PIN q[174]
    DIRECTION OUTPUT ;
    USE SIGNAL ;
    PORT
      LAYER M4 ;
        RECT  0 72.528 0.084 72.552 ;
    END
  END q[174]
  PIN q[175]
    DIRECTION OUTPUT ;
    USE SIGNAL ;
    PORT
      LAYER M4 ;
        RECT  0 72.624 0.084 72.648 ;
    END
  END q[175]
  PIN q[176]
    DIRECTION OUTPUT ;
    USE SIGNAL ;
    PORT
      LAYER M4 ;
        RECT  0 72.72 0.084 72.744 ;
    END
  END q[176]
  PIN q[177]
    DIRECTION OUTPUT ;
    USE SIGNAL ;
    PORT
      LAYER M4 ;
        RECT  0 72.816 0.084 72.84 ;
    END
  END q[177]
  PIN q[178]
    DIRECTION OUTPUT ;
    USE SIGNAL ;
    PORT
      LAYER M4 ;
        RECT  0 72.912 0.084 72.936 ;
    END
  END q[178]
  PIN q[179]
    DIRECTION OUTPUT ;
    USE SIGNAL ;
    PORT
      LAYER M4 ;
        RECT  0 73.008 0.084 73.032 ;
    END
  END q[179]
  PIN q[17]
    DIRECTION OUTPUT ;
    USE SIGNAL ;
    PORT
      LAYER M4 ;
        RECT  0 22.128 0.084 22.152 ;
    END
  END q[17]
  PIN q[180]
    DIRECTION OUTPUT ;
    USE SIGNAL ;
    PORT
      LAYER M4 ;
        RECT  0 73.104 0.084 73.128 ;
    END
  END q[180]
  PIN q[181]
    DIRECTION OUTPUT ;
    USE SIGNAL ;
    PORT
      LAYER M4 ;
        RECT  0 73.2 0.084 73.224 ;
    END
  END q[181]
  PIN q[182]
    DIRECTION OUTPUT ;
    USE SIGNAL ;
    PORT
      LAYER M4 ;
        RECT  0 73.296 0.084 73.32 ;
    END
  END q[182]
  PIN q[183]
    DIRECTION OUTPUT ;
    USE SIGNAL ;
    PORT
      LAYER M4 ;
        RECT  0 73.392 0.084 73.416 ;
    END
  END q[183]
  PIN q[184]
    DIRECTION OUTPUT ;
    USE SIGNAL ;
    PORT
      LAYER M4 ;
        RECT  0 73.488 0.084 73.512 ;
    END
  END q[184]
  PIN q[185]
    DIRECTION OUTPUT ;
    USE SIGNAL ;
    PORT
      LAYER M4 ;
        RECT  0 73.584 0.084 73.608 ;
    END
  END q[185]
  PIN q[186]
    DIRECTION OUTPUT ;
    USE SIGNAL ;
    PORT
      LAYER M4 ;
        RECT  0 73.68 0.084 73.704 ;
    END
  END q[186]
  PIN q[187]
    DIRECTION OUTPUT ;
    USE SIGNAL ;
    PORT
      LAYER M4 ;
        RECT  0 73.776 0.084 73.8 ;
    END
  END q[187]
  PIN q[188]
    DIRECTION OUTPUT ;
    USE SIGNAL ;
    PORT
      LAYER M4 ;
        RECT  0 73.872 0.084 73.896 ;
    END
  END q[188]
  PIN q[189]
    DIRECTION OUTPUT ;
    USE SIGNAL ;
    PORT
      LAYER M4 ;
        RECT  0 73.968 0.084 73.992 ;
    END
  END q[189]
  PIN q[18]
    DIRECTION OUTPUT ;
    USE SIGNAL ;
    PORT
      LAYER M4 ;
        RECT  0 22.224 0.084 22.248 ;
    END
  END q[18]
  PIN q[190]
    DIRECTION OUTPUT ;
    USE SIGNAL ;
    PORT
      LAYER M4 ;
        RECT  0 74.064 0.084 74.088 ;
    END
  END q[190]
  PIN q[191]
    DIRECTION OUTPUT ;
    USE SIGNAL ;
    PORT
      LAYER M4 ;
        RECT  0 74.16 0.084 74.184 ;
    END
  END q[191]
  PIN q[192]
    DIRECTION OUTPUT ;
    USE SIGNAL ;
    PORT
      LAYER M4 ;
        RECT  0 65.04 0.084 65.064 ;
    END
  END q[192]
  PIN q[193]
    DIRECTION OUTPUT ;
    USE SIGNAL ;
    PORT
      LAYER M4 ;
        RECT  0 65.136 0.084 65.16 ;
    END
  END q[193]
  PIN q[194]
    DIRECTION OUTPUT ;
    USE SIGNAL ;
    PORT
      LAYER M4 ;
        RECT  0 65.232 0.084 65.256 ;
    END
  END q[194]
  PIN q[195]
    DIRECTION OUTPUT ;
    USE SIGNAL ;
    PORT
      LAYER M4 ;
        RECT  0 65.328 0.084 65.352 ;
    END
  END q[195]
  PIN q[196]
    DIRECTION OUTPUT ;
    USE SIGNAL ;
    PORT
      LAYER M4 ;
        RECT  0 65.424 0.084 65.448 ;
    END
  END q[196]
  PIN q[197]
    DIRECTION OUTPUT ;
    USE SIGNAL ;
    PORT
      LAYER M4 ;
        RECT  0 65.52 0.084 65.544 ;
    END
  END q[197]
  PIN q[198]
    DIRECTION OUTPUT ;
    USE SIGNAL ;
    PORT
      LAYER M4 ;
        RECT  0 65.616 0.084 65.64 ;
    END
  END q[198]
  PIN q[199]
    DIRECTION OUTPUT ;
    USE SIGNAL ;
    PORT
      LAYER M4 ;
        RECT  0 65.712 0.084 65.736 ;
    END
  END q[199]
  PIN q[19]
    DIRECTION OUTPUT ;
    USE SIGNAL ;
    PORT
      LAYER M4 ;
        RECT  0 22.32 0.084 22.344 ;
    END
  END q[19]
  PIN q[1]
    DIRECTION OUTPUT ;
    USE SIGNAL ;
    PORT
      LAYER M4 ;
        RECT  0 20.592 0.084 20.616 ;
    END
  END q[1]
  PIN q[200]
    DIRECTION OUTPUT ;
    USE SIGNAL ;
    PORT
      LAYER M4 ;
        RECT  0 65.808 0.084 65.832 ;
    END
  END q[200]
  PIN q[201]
    DIRECTION OUTPUT ;
    USE SIGNAL ;
    PORT
      LAYER M4 ;
        RECT  0 65.904 0.084 65.928 ;
    END
  END q[201]
  PIN q[202]
    DIRECTION OUTPUT ;
    USE SIGNAL ;
    PORT
      LAYER M4 ;
        RECT  0 66 0.084 66.024 ;
    END
  END q[202]
  PIN q[203]
    DIRECTION OUTPUT ;
    USE SIGNAL ;
    PORT
      LAYER M4 ;
        RECT  0 66.096 0.084 66.12 ;
    END
  END q[203]
  PIN q[204]
    DIRECTION OUTPUT ;
    USE SIGNAL ;
    PORT
      LAYER M4 ;
        RECT  0 66.192 0.084 66.216 ;
    END
  END q[204]
  PIN q[205]
    DIRECTION OUTPUT ;
    USE SIGNAL ;
    PORT
      LAYER M4 ;
        RECT  0 66.288 0.084 66.312 ;
    END
  END q[205]
  PIN q[206]
    DIRECTION OUTPUT ;
    USE SIGNAL ;
    PORT
      LAYER M4 ;
        RECT  0 66.384 0.084 66.408 ;
    END
  END q[206]
  PIN q[207]
    DIRECTION OUTPUT ;
    USE SIGNAL ;
    PORT
      LAYER M4 ;
        RECT  0 66.48 0.084 66.504 ;
    END
  END q[207]
  PIN q[208]
    DIRECTION OUTPUT ;
    USE SIGNAL ;
    PORT
      LAYER M4 ;
        RECT  0 66.576 0.084 66.6 ;
    END
  END q[208]
  PIN q[209]
    DIRECTION OUTPUT ;
    USE SIGNAL ;
    PORT
      LAYER M4 ;
        RECT  0 66.672 0.084 66.696 ;
    END
  END q[209]
  PIN q[20]
    DIRECTION OUTPUT ;
    USE SIGNAL ;
    PORT
      LAYER M4 ;
        RECT  0 22.416 0.084 22.44 ;
    END
  END q[20]
  PIN q[210]
    DIRECTION OUTPUT ;
    USE SIGNAL ;
    PORT
      LAYER M4 ;
        RECT  0 66.768 0.084 66.792 ;
    END
  END q[210]
  PIN q[211]
    DIRECTION OUTPUT ;
    USE SIGNAL ;
    PORT
      LAYER M4 ;
        RECT  0 66.864 0.084 66.888 ;
    END
  END q[211]
  PIN q[212]
    DIRECTION OUTPUT ;
    USE SIGNAL ;
    PORT
      LAYER M4 ;
        RECT  0 66.96 0.084 66.984 ;
    END
  END q[212]
  PIN q[213]
    DIRECTION OUTPUT ;
    USE SIGNAL ;
    PORT
      LAYER M4 ;
        RECT  0 67.056 0.084 67.08 ;
    END
  END q[213]
  PIN q[214]
    DIRECTION OUTPUT ;
    USE SIGNAL ;
    PORT
      LAYER M4 ;
        RECT  0 67.152 0.084 67.176 ;
    END
  END q[214]
  PIN q[215]
    DIRECTION OUTPUT ;
    USE SIGNAL ;
    PORT
      LAYER M4 ;
        RECT  0 67.248 0.084 67.272 ;
    END
  END q[215]
  PIN q[216]
    DIRECTION OUTPUT ;
    USE SIGNAL ;
    PORT
      LAYER M4 ;
        RECT  0 67.344 0.084 67.368 ;
    END
  END q[216]
  PIN q[217]
    DIRECTION OUTPUT ;
    USE SIGNAL ;
    PORT
      LAYER M4 ;
        RECT  0 67.44 0.084 67.464 ;
    END
  END q[217]
  PIN q[218]
    DIRECTION OUTPUT ;
    USE SIGNAL ;
    PORT
      LAYER M4 ;
        RECT  0 67.536 0.084 67.56 ;
    END
  END q[218]
  PIN q[219]
    DIRECTION OUTPUT ;
    USE SIGNAL ;
    PORT
      LAYER M4 ;
        RECT  0 67.632 0.084 67.656 ;
    END
  END q[219]
  PIN q[21]
    DIRECTION OUTPUT ;
    USE SIGNAL ;
    PORT
      LAYER M4 ;
        RECT  0 22.512 0.084 22.536 ;
    END
  END q[21]
  PIN q[220]
    DIRECTION OUTPUT ;
    USE SIGNAL ;
    PORT
      LAYER M4 ;
        RECT  0 67.728 0.084 67.752 ;
    END
  END q[220]
  PIN q[221]
    DIRECTION OUTPUT ;
    USE SIGNAL ;
    PORT
      LAYER M4 ;
        RECT  0 67.824 0.084 67.848 ;
    END
  END q[221]
  PIN q[222]
    DIRECTION OUTPUT ;
    USE SIGNAL ;
    PORT
      LAYER M4 ;
        RECT  0 67.92 0.084 67.944 ;
    END
  END q[222]
  PIN q[223]
    DIRECTION OUTPUT ;
    USE SIGNAL ;
    PORT
      LAYER M4 ;
        RECT  0 68.016 0.084 68.04 ;
    END
  END q[223]
  PIN q[224]
    DIRECTION OUTPUT ;
    USE SIGNAL ;
    PORT
      LAYER M4 ;
        RECT  0 68.112 0.084 68.136 ;
    END
  END q[224]
  PIN q[225]
    DIRECTION OUTPUT ;
    USE SIGNAL ;
    PORT
      LAYER M4 ;
        RECT  0 68.208 0.084 68.232 ;
    END
  END q[225]
  PIN q[226]
    DIRECTION OUTPUT ;
    USE SIGNAL ;
    PORT
      LAYER M4 ;
        RECT  0 68.304 0.084 68.328 ;
    END
  END q[226]
  PIN q[227]
    DIRECTION OUTPUT ;
    USE SIGNAL ;
    PORT
      LAYER M4 ;
        RECT  0 68.4 0.084 68.424 ;
    END
  END q[227]
  PIN q[228]
    DIRECTION OUTPUT ;
    USE SIGNAL ;
    PORT
      LAYER M4 ;
        RECT  0 68.496 0.084 68.52 ;
    END
  END q[228]
  PIN q[229]
    DIRECTION OUTPUT ;
    USE SIGNAL ;
    PORT
      LAYER M4 ;
        RECT  0 68.592 0.084 68.616 ;
    END
  END q[229]
  PIN q[22]
    DIRECTION OUTPUT ;
    USE SIGNAL ;
    PORT
      LAYER M4 ;
        RECT  0 22.608 0.084 22.632 ;
    END
  END q[22]
  PIN q[230]
    DIRECTION OUTPUT ;
    USE SIGNAL ;
    PORT
      LAYER M4 ;
        RECT  0 68.688 0.084 68.712 ;
    END
  END q[230]
  PIN q[231]
    DIRECTION OUTPUT ;
    USE SIGNAL ;
    PORT
      LAYER M4 ;
        RECT  0 68.784 0.084 68.808 ;
    END
  END q[231]
  PIN q[232]
    DIRECTION OUTPUT ;
    USE SIGNAL ;
    PORT
      LAYER M4 ;
        RECT  0 68.88 0.084 68.904 ;
    END
  END q[232]
  PIN q[233]
    DIRECTION OUTPUT ;
    USE SIGNAL ;
    PORT
      LAYER M4 ;
        RECT  0 68.976 0.084 69 ;
    END
  END q[233]
  PIN q[234]
    DIRECTION OUTPUT ;
    USE SIGNAL ;
    PORT
      LAYER M4 ;
        RECT  0 69.072 0.084 69.096 ;
    END
  END q[234]
  PIN q[235]
    DIRECTION OUTPUT ;
    USE SIGNAL ;
    PORT
      LAYER M4 ;
        RECT  0 69.168 0.084 69.192 ;
    END
  END q[235]
  PIN q[236]
    DIRECTION OUTPUT ;
    USE SIGNAL ;
    PORT
      LAYER M4 ;
        RECT  0 69.264 0.084 69.288 ;
    END
  END q[236]
  PIN q[237]
    DIRECTION OUTPUT ;
    USE SIGNAL ;
    PORT
      LAYER M4 ;
        RECT  0 69.36 0.084 69.384 ;
    END
  END q[237]
  PIN q[238]
    DIRECTION OUTPUT ;
    USE SIGNAL ;
    PORT
      LAYER M4 ;
        RECT  0 69.456 0.084 69.48 ;
    END
  END q[238]
  PIN q[239]
    DIRECTION OUTPUT ;
    USE SIGNAL ;
    PORT
      LAYER M4 ;
        RECT  0 69.552 0.084 69.576 ;
    END
  END q[239]
  PIN q[23]
    DIRECTION OUTPUT ;
    USE SIGNAL ;
    PORT
      LAYER M4 ;
        RECT  0 22.704 0.084 22.728 ;
    END
  END q[23]
  PIN q[240]
    DIRECTION OUTPUT ;
    USE SIGNAL ;
    PORT
      LAYER M4 ;
        RECT  0 69.648 0.084 69.672 ;
    END
  END q[240]
  PIN q[241]
    DIRECTION OUTPUT ;
    USE SIGNAL ;
    PORT
      LAYER M4 ;
        RECT  0 69.744 0.084 69.768 ;
    END
  END q[241]
  PIN q[242]
    DIRECTION OUTPUT ;
    USE SIGNAL ;
    PORT
      LAYER M4 ;
        RECT  0 69.84 0.084 69.864 ;
    END
  END q[242]
  PIN q[243]
    DIRECTION OUTPUT ;
    USE SIGNAL ;
    PORT
      LAYER M4 ;
        RECT  0 69.936 0.084 69.96 ;
    END
  END q[243]
  PIN q[244]
    DIRECTION OUTPUT ;
    USE SIGNAL ;
    PORT
      LAYER M4 ;
        RECT  0 70.032 0.084 70.056 ;
    END
  END q[244]
  PIN q[245]
    DIRECTION OUTPUT ;
    USE SIGNAL ;
    PORT
      LAYER M4 ;
        RECT  0 70.128 0.084 70.152 ;
    END
  END q[245]
  PIN q[246]
    DIRECTION OUTPUT ;
    USE SIGNAL ;
    PORT
      LAYER M4 ;
        RECT  0 70.224 0.084 70.248 ;
    END
  END q[246]
  PIN q[247]
    DIRECTION OUTPUT ;
    USE SIGNAL ;
    PORT
      LAYER M4 ;
        RECT  0 70.32 0.084 70.344 ;
    END
  END q[247]
  PIN q[248]
    DIRECTION OUTPUT ;
    USE SIGNAL ;
    PORT
      LAYER M4 ;
        RECT  0 70.416 0.084 70.44 ;
    END
  END q[248]
  PIN q[249]
    DIRECTION OUTPUT ;
    USE SIGNAL ;
    PORT
      LAYER M4 ;
        RECT  0 70.512 0.084 70.536 ;
    END
  END q[249]
  PIN q[24]
    DIRECTION OUTPUT ;
    USE SIGNAL ;
    PORT
      LAYER M4 ;
        RECT  0 22.8 0.084 22.824 ;
    END
  END q[24]
  PIN q[250]
    DIRECTION OUTPUT ;
    USE SIGNAL ;
    PORT
      LAYER M4 ;
        RECT  0 70.608 0.084 70.632 ;
    END
  END q[250]
  PIN q[251]
    DIRECTION OUTPUT ;
    USE SIGNAL ;
    PORT
      LAYER M4 ;
        RECT  0 70.704 0.084 70.728 ;
    END
  END q[251]
  PIN q[252]
    DIRECTION OUTPUT ;
    USE SIGNAL ;
    PORT
      LAYER M4 ;
        RECT  0 70.8 0.084 70.824 ;
    END
  END q[252]
  PIN q[253]
    DIRECTION OUTPUT ;
    USE SIGNAL ;
    PORT
      LAYER M4 ;
        RECT  0 70.896 0.084 70.92 ;
    END
  END q[253]
  PIN q[254]
    DIRECTION OUTPUT ;
    USE SIGNAL ;
    PORT
      LAYER M4 ;
        RECT  0 70.992 0.084 71.016 ;
    END
  END q[254]
  PIN q[255]
    DIRECTION OUTPUT ;
    USE SIGNAL ;
    PORT
      LAYER M4 ;
        RECT  0 71.088 0.084 71.112 ;
    END
  END q[255]
  PIN q[256]
    DIRECTION OUTPUT ;
    USE SIGNAL ;
    PORT
      LAYER M4 ;
        RECT  0 55.056 0.084 55.08 ;
    END
  END q[256]
  PIN q[257]
    DIRECTION OUTPUT ;
    USE SIGNAL ;
    PORT
      LAYER M4 ;
        RECT  0 55.152 0.084 55.176 ;
    END
  END q[257]
  PIN q[258]
    DIRECTION OUTPUT ;
    USE SIGNAL ;
    PORT
      LAYER M4 ;
        RECT  0 55.248 0.084 55.272 ;
    END
  END q[258]
  PIN q[259]
    DIRECTION OUTPUT ;
    USE SIGNAL ;
    PORT
      LAYER M4 ;
        RECT  0 55.344 0.084 55.368 ;
    END
  END q[259]
  PIN q[25]
    DIRECTION OUTPUT ;
    USE SIGNAL ;
    PORT
      LAYER M4 ;
        RECT  0 22.896 0.084 22.92 ;
    END
  END q[25]
  PIN q[260]
    DIRECTION OUTPUT ;
    USE SIGNAL ;
    PORT
      LAYER M4 ;
        RECT  0 55.44 0.084 55.464 ;
    END
  END q[260]
  PIN q[261]
    DIRECTION OUTPUT ;
    USE SIGNAL ;
    PORT
      LAYER M4 ;
        RECT  0 55.536 0.084 55.56 ;
    END
  END q[261]
  PIN q[262]
    DIRECTION OUTPUT ;
    USE SIGNAL ;
    PORT
      LAYER M4 ;
        RECT  0 55.632 0.084 55.656 ;
    END
  END q[262]
  PIN q[263]
    DIRECTION OUTPUT ;
    USE SIGNAL ;
    PORT
      LAYER M4 ;
        RECT  0 55.728 0.084 55.752 ;
    END
  END q[263]
  PIN q[264]
    DIRECTION OUTPUT ;
    USE SIGNAL ;
    PORT
      LAYER M4 ;
        RECT  0 55.824 0.084 55.848 ;
    END
  END q[264]
  PIN q[265]
    DIRECTION OUTPUT ;
    USE SIGNAL ;
    PORT
      LAYER M4 ;
        RECT  0 55.92 0.084 55.944 ;
    END
  END q[265]
  PIN q[266]
    DIRECTION OUTPUT ;
    USE SIGNAL ;
    PORT
      LAYER M4 ;
        RECT  0 56.016 0.084 56.04 ;
    END
  END q[266]
  PIN q[267]
    DIRECTION OUTPUT ;
    USE SIGNAL ;
    PORT
      LAYER M4 ;
        RECT  0 56.112 0.084 56.136 ;
    END
  END q[267]
  PIN q[268]
    DIRECTION OUTPUT ;
    USE SIGNAL ;
    PORT
      LAYER M4 ;
        RECT  0 56.208 0.084 56.232 ;
    END
  END q[268]
  PIN q[269]
    DIRECTION OUTPUT ;
    USE SIGNAL ;
    PORT
      LAYER M4 ;
        RECT  0 56.304 0.084 56.328 ;
    END
  END q[269]
  PIN q[26]
    DIRECTION OUTPUT ;
    USE SIGNAL ;
    PORT
      LAYER M4 ;
        RECT  0 22.992 0.084 23.016 ;
    END
  END q[26]
  PIN q[270]
    DIRECTION OUTPUT ;
    USE SIGNAL ;
    PORT
      LAYER M4 ;
        RECT  0 56.4 0.084 56.424 ;
    END
  END q[270]
  PIN q[271]
    DIRECTION OUTPUT ;
    USE SIGNAL ;
    PORT
      LAYER M4 ;
        RECT  0 56.496 0.084 56.52 ;
    END
  END q[271]
  PIN q[272]
    DIRECTION OUTPUT ;
    USE SIGNAL ;
    PORT
      LAYER M4 ;
        RECT  0 56.592 0.084 56.616 ;
    END
  END q[272]
  PIN q[273]
    DIRECTION OUTPUT ;
    USE SIGNAL ;
    PORT
      LAYER M4 ;
        RECT  0 56.688 0.084 56.712 ;
    END
  END q[273]
  PIN q[274]
    DIRECTION OUTPUT ;
    USE SIGNAL ;
    PORT
      LAYER M4 ;
        RECT  0 56.784 0.084 56.808 ;
    END
  END q[274]
  PIN q[275]
    DIRECTION OUTPUT ;
    USE SIGNAL ;
    PORT
      LAYER M4 ;
        RECT  0 56.88 0.084 56.904 ;
    END
  END q[275]
  PIN q[276]
    DIRECTION OUTPUT ;
    USE SIGNAL ;
    PORT
      LAYER M4 ;
        RECT  0 56.976 0.084 57 ;
    END
  END q[276]
  PIN q[277]
    DIRECTION OUTPUT ;
    USE SIGNAL ;
    PORT
      LAYER M4 ;
        RECT  0 57.072 0.084 57.096 ;
    END
  END q[277]
  PIN q[278]
    DIRECTION OUTPUT ;
    USE SIGNAL ;
    PORT
      LAYER M4 ;
        RECT  0 57.168 0.084 57.192 ;
    END
  END q[278]
  PIN q[279]
    DIRECTION OUTPUT ;
    USE SIGNAL ;
    PORT
      LAYER M4 ;
        RECT  0 57.264 0.084 57.288 ;
    END
  END q[279]
  PIN q[27]
    DIRECTION OUTPUT ;
    USE SIGNAL ;
    PORT
      LAYER M4 ;
        RECT  0 23.088 0.084 23.112 ;
    END
  END q[27]
  PIN q[280]
    DIRECTION OUTPUT ;
    USE SIGNAL ;
    PORT
      LAYER M4 ;
        RECT  0 57.36 0.084 57.384 ;
    END
  END q[280]
  PIN q[281]
    DIRECTION OUTPUT ;
    USE SIGNAL ;
    PORT
      LAYER M4 ;
        RECT  0 57.456 0.084 57.48 ;
    END
  END q[281]
  PIN q[282]
    DIRECTION OUTPUT ;
    USE SIGNAL ;
    PORT
      LAYER M4 ;
        RECT  0 57.552 0.084 57.576 ;
    END
  END q[282]
  PIN q[283]
    DIRECTION OUTPUT ;
    USE SIGNAL ;
    PORT
      LAYER M4 ;
        RECT  0 57.648 0.084 57.672 ;
    END
  END q[283]
  PIN q[284]
    DIRECTION OUTPUT ;
    USE SIGNAL ;
    PORT
      LAYER M4 ;
        RECT  0 57.744 0.084 57.768 ;
    END
  END q[284]
  PIN q[285]
    DIRECTION OUTPUT ;
    USE SIGNAL ;
    PORT
      LAYER M4 ;
        RECT  0 57.84 0.084 57.864 ;
    END
  END q[285]
  PIN q[286]
    DIRECTION OUTPUT ;
    USE SIGNAL ;
    PORT
      LAYER M4 ;
        RECT  0 57.936 0.084 57.96 ;
    END
  END q[286]
  PIN q[287]
    DIRECTION OUTPUT ;
    USE SIGNAL ;
    PORT
      LAYER M4 ;
        RECT  0 58.032 0.084 58.056 ;
    END
  END q[287]
  PIN q[288]
    DIRECTION OUTPUT ;
    USE SIGNAL ;
    PORT
      LAYER M4 ;
        RECT  0 48.912 0.084 48.936 ;
    END
  END q[288]
  PIN q[289]
    DIRECTION OUTPUT ;
    USE SIGNAL ;
    PORT
      LAYER M4 ;
        RECT  0 49.008 0.084 49.032 ;
    END
  END q[289]
  PIN q[28]
    DIRECTION OUTPUT ;
    USE SIGNAL ;
    PORT
      LAYER M4 ;
        RECT  0 23.184 0.084 23.208 ;
    END
  END q[28]
  PIN q[290]
    DIRECTION OUTPUT ;
    USE SIGNAL ;
    PORT
      LAYER M4 ;
        RECT  0 49.104 0.084 49.128 ;
    END
  END q[290]
  PIN q[291]
    DIRECTION OUTPUT ;
    USE SIGNAL ;
    PORT
      LAYER M4 ;
        RECT  0 49.2 0.084 49.224 ;
    END
  END q[291]
  PIN q[292]
    DIRECTION OUTPUT ;
    USE SIGNAL ;
    PORT
      LAYER M4 ;
        RECT  0 49.296 0.084 49.32 ;
    END
  END q[292]
  PIN q[293]
    DIRECTION OUTPUT ;
    USE SIGNAL ;
    PORT
      LAYER M4 ;
        RECT  0 49.392 0.084 49.416 ;
    END
  END q[293]
  PIN q[294]
    DIRECTION OUTPUT ;
    USE SIGNAL ;
    PORT
      LAYER M4 ;
        RECT  0 49.488 0.084 49.512 ;
    END
  END q[294]
  PIN q[295]
    DIRECTION OUTPUT ;
    USE SIGNAL ;
    PORT
      LAYER M4 ;
        RECT  0 49.584 0.084 49.608 ;
    END
  END q[295]
  PIN q[296]
    DIRECTION OUTPUT ;
    USE SIGNAL ;
    PORT
      LAYER M4 ;
        RECT  0 49.68 0.084 49.704 ;
    END
  END q[296]
  PIN q[297]
    DIRECTION OUTPUT ;
    USE SIGNAL ;
    PORT
      LAYER M4 ;
        RECT  0 49.776 0.084 49.8 ;
    END
  END q[297]
  PIN q[298]
    DIRECTION OUTPUT ;
    USE SIGNAL ;
    PORT
      LAYER M4 ;
        RECT  0 49.872 0.084 49.896 ;
    END
  END q[298]
  PIN q[299]
    DIRECTION OUTPUT ;
    USE SIGNAL ;
    PORT
      LAYER M4 ;
        RECT  0 49.968 0.084 49.992 ;
    END
  END q[299]
  PIN q[29]
    DIRECTION OUTPUT ;
    USE SIGNAL ;
    PORT
      LAYER M4 ;
        RECT  0 23.28 0.084 23.304 ;
    END
  END q[29]
  PIN q[2]
    DIRECTION OUTPUT ;
    USE SIGNAL ;
    PORT
      LAYER M4 ;
        RECT  0 20.688 0.084 20.712 ;
    END
  END q[2]
  PIN q[300]
    DIRECTION OUTPUT ;
    USE SIGNAL ;
    PORT
      LAYER M4 ;
        RECT  0 50.064 0.084 50.088 ;
    END
  END q[300]
  PIN q[301]
    DIRECTION OUTPUT ;
    USE SIGNAL ;
    PORT
      LAYER M4 ;
        RECT  0 50.16 0.084 50.184 ;
    END
  END q[301]
  PIN q[302]
    DIRECTION OUTPUT ;
    USE SIGNAL ;
    PORT
      LAYER M4 ;
        RECT  0 50.256 0.084 50.28 ;
    END
  END q[302]
  PIN q[303]
    DIRECTION OUTPUT ;
    USE SIGNAL ;
    PORT
      LAYER M4 ;
        RECT  0 50.352 0.084 50.376 ;
    END
  END q[303]
  PIN q[304]
    DIRECTION OUTPUT ;
    USE SIGNAL ;
    PORT
      LAYER M4 ;
        RECT  0 50.448 0.084 50.472 ;
    END
  END q[304]
  PIN q[305]
    DIRECTION OUTPUT ;
    USE SIGNAL ;
    PORT
      LAYER M4 ;
        RECT  0 50.544 0.084 50.568 ;
    END
  END q[305]
  PIN q[306]
    DIRECTION OUTPUT ;
    USE SIGNAL ;
    PORT
      LAYER M4 ;
        RECT  0 50.64 0.084 50.664 ;
    END
  END q[306]
  PIN q[307]
    DIRECTION OUTPUT ;
    USE SIGNAL ;
    PORT
      LAYER M4 ;
        RECT  0 50.736 0.084 50.76 ;
    END
  END q[307]
  PIN q[308]
    DIRECTION OUTPUT ;
    USE SIGNAL ;
    PORT
      LAYER M4 ;
        RECT  0 50.832 0.084 50.856 ;
    END
  END q[308]
  PIN q[309]
    DIRECTION OUTPUT ;
    USE SIGNAL ;
    PORT
      LAYER M4 ;
        RECT  0 50.928 0.084 50.952 ;
    END
  END q[309]
  PIN q[30]
    DIRECTION OUTPUT ;
    USE SIGNAL ;
    PORT
      LAYER M4 ;
        RECT  0 23.376 0.084 23.4 ;
    END
  END q[30]
  PIN q[310]
    DIRECTION OUTPUT ;
    USE SIGNAL ;
    PORT
      LAYER M4 ;
        RECT  0 51.024 0.084 51.048 ;
    END
  END q[310]
  PIN q[311]
    DIRECTION OUTPUT ;
    USE SIGNAL ;
    PORT
      LAYER M4 ;
        RECT  0 51.12 0.084 51.144 ;
    END
  END q[311]
  PIN q[312]
    DIRECTION OUTPUT ;
    USE SIGNAL ;
    PORT
      LAYER M4 ;
        RECT  0 51.216 0.084 51.24 ;
    END
  END q[312]
  PIN q[313]
    DIRECTION OUTPUT ;
    USE SIGNAL ;
    PORT
      LAYER M4 ;
        RECT  0 51.312 0.084 51.336 ;
    END
  END q[313]
  PIN q[314]
    DIRECTION OUTPUT ;
    USE SIGNAL ;
    PORT
      LAYER M4 ;
        RECT  0 51.408 0.084 51.432 ;
    END
  END q[314]
  PIN q[315]
    DIRECTION OUTPUT ;
    USE SIGNAL ;
    PORT
      LAYER M4 ;
        RECT  0 51.504 0.084 51.528 ;
    END
  END q[315]
  PIN q[316]
    DIRECTION OUTPUT ;
    USE SIGNAL ;
    PORT
      LAYER M4 ;
        RECT  0 51.6 0.084 51.624 ;
    END
  END q[316]
  PIN q[317]
    DIRECTION OUTPUT ;
    USE SIGNAL ;
    PORT
      LAYER M4 ;
        RECT  0 51.696 0.084 51.72 ;
    END
  END q[317]
  PIN q[318]
    DIRECTION OUTPUT ;
    USE SIGNAL ;
    PORT
      LAYER M4 ;
        RECT  0 51.792 0.084 51.816 ;
    END
  END q[318]
  PIN q[319]
    DIRECTION OUTPUT ;
    USE SIGNAL ;
    PORT
      LAYER M4 ;
        RECT  0 51.888 0.084 51.912 ;
    END
  END q[319]
  PIN q[31]
    DIRECTION OUTPUT ;
    USE SIGNAL ;
    PORT
      LAYER M4 ;
        RECT  0 23.472 0.084 23.496 ;
    END
  END q[31]
  PIN q[320]
    DIRECTION OUTPUT ;
    USE SIGNAL ;
    PORT
      LAYER M4 ;
        RECT  0 51.984 0.084 52.008 ;
    END
  END q[320]
  PIN q[321]
    DIRECTION OUTPUT ;
    USE SIGNAL ;
    PORT
      LAYER M4 ;
        RECT  0 52.08 0.084 52.104 ;
    END
  END q[321]
  PIN q[322]
    DIRECTION OUTPUT ;
    USE SIGNAL ;
    PORT
      LAYER M4 ;
        RECT  0 52.176 0.084 52.2 ;
    END
  END q[322]
  PIN q[323]
    DIRECTION OUTPUT ;
    USE SIGNAL ;
    PORT
      LAYER M4 ;
        RECT  0 52.272 0.084 52.296 ;
    END
  END q[323]
  PIN q[324]
    DIRECTION OUTPUT ;
    USE SIGNAL ;
    PORT
      LAYER M4 ;
        RECT  0 52.368 0.084 52.392 ;
    END
  END q[324]
  PIN q[325]
    DIRECTION OUTPUT ;
    USE SIGNAL ;
    PORT
      LAYER M4 ;
        RECT  0 52.464 0.084 52.488 ;
    END
  END q[325]
  PIN q[326]
    DIRECTION OUTPUT ;
    USE SIGNAL ;
    PORT
      LAYER M4 ;
        RECT  0 52.56 0.084 52.584 ;
    END
  END q[326]
  PIN q[327]
    DIRECTION OUTPUT ;
    USE SIGNAL ;
    PORT
      LAYER M4 ;
        RECT  0 52.656 0.084 52.68 ;
    END
  END q[327]
  PIN q[328]
    DIRECTION OUTPUT ;
    USE SIGNAL ;
    PORT
      LAYER M4 ;
        RECT  0 52.752 0.084 52.776 ;
    END
  END q[328]
  PIN q[329]
    DIRECTION OUTPUT ;
    USE SIGNAL ;
    PORT
      LAYER M4 ;
        RECT  0 52.848 0.084 52.872 ;
    END
  END q[329]
  PIN q[32]
    DIRECTION OUTPUT ;
    USE SIGNAL ;
    PORT
      LAYER M4 ;
        RECT  0 29.712 0.084 29.736 ;
    END
  END q[32]
  PIN q[330]
    DIRECTION OUTPUT ;
    USE SIGNAL ;
    PORT
      LAYER M4 ;
        RECT  0 52.944 0.084 52.968 ;
    END
  END q[330]
  PIN q[331]
    DIRECTION OUTPUT ;
    USE SIGNAL ;
    PORT
      LAYER M4 ;
        RECT  0 53.04 0.084 53.064 ;
    END
  END q[331]
  PIN q[332]
    DIRECTION OUTPUT ;
    USE SIGNAL ;
    PORT
      LAYER M4 ;
        RECT  0 53.136 0.084 53.16 ;
    END
  END q[332]
  PIN q[333]
    DIRECTION OUTPUT ;
    USE SIGNAL ;
    PORT
      LAYER M4 ;
        RECT  0 53.232 0.084 53.256 ;
    END
  END q[333]
  PIN q[334]
    DIRECTION OUTPUT ;
    USE SIGNAL ;
    PORT
      LAYER M4 ;
        RECT  0 53.328 0.084 53.352 ;
    END
  END q[334]
  PIN q[335]
    DIRECTION OUTPUT ;
    USE SIGNAL ;
    PORT
      LAYER M4 ;
        RECT  0 53.424 0.084 53.448 ;
    END
  END q[335]
  PIN q[336]
    DIRECTION OUTPUT ;
    USE SIGNAL ;
    PORT
      LAYER M4 ;
        RECT  0 53.52 0.084 53.544 ;
    END
  END q[336]
  PIN q[337]
    DIRECTION OUTPUT ;
    USE SIGNAL ;
    PORT
      LAYER M4 ;
        RECT  0 53.616 0.084 53.64 ;
    END
  END q[337]
  PIN q[338]
    DIRECTION OUTPUT ;
    USE SIGNAL ;
    PORT
      LAYER M4 ;
        RECT  0 53.712 0.084 53.736 ;
    END
  END q[338]
  PIN q[339]
    DIRECTION OUTPUT ;
    USE SIGNAL ;
    PORT
      LAYER M4 ;
        RECT  0 53.808 0.084 53.832 ;
    END
  END q[339]
  PIN q[33]
    DIRECTION OUTPUT ;
    USE SIGNAL ;
    PORT
      LAYER M4 ;
        RECT  0 29.808 0.084 29.832 ;
    END
  END q[33]
  PIN q[340]
    DIRECTION OUTPUT ;
    USE SIGNAL ;
    PORT
      LAYER M4 ;
        RECT  0 53.904 0.084 53.928 ;
    END
  END q[340]
  PIN q[341]
    DIRECTION OUTPUT ;
    USE SIGNAL ;
    PORT
      LAYER M4 ;
        RECT  0 54 0.084 54.024 ;
    END
  END q[341]
  PIN q[342]
    DIRECTION OUTPUT ;
    USE SIGNAL ;
    PORT
      LAYER M4 ;
        RECT  0 54.096 0.084 54.12 ;
    END
  END q[342]
  PIN q[343]
    DIRECTION OUTPUT ;
    USE SIGNAL ;
    PORT
      LAYER M4 ;
        RECT  0 54.192 0.084 54.216 ;
    END
  END q[343]
  PIN q[344]
    DIRECTION OUTPUT ;
    USE SIGNAL ;
    PORT
      LAYER M4 ;
        RECT  0 54.288 0.084 54.312 ;
    END
  END q[344]
  PIN q[345]
    DIRECTION OUTPUT ;
    USE SIGNAL ;
    PORT
      LAYER M4 ;
        RECT  0 54.384 0.084 54.408 ;
    END
  END q[345]
  PIN q[346]
    DIRECTION OUTPUT ;
    USE SIGNAL ;
    PORT
      LAYER M4 ;
        RECT  0 54.48 0.084 54.504 ;
    END
  END q[346]
  PIN q[347]
    DIRECTION OUTPUT ;
    USE SIGNAL ;
    PORT
      LAYER M4 ;
        RECT  0 54.576 0.084 54.6 ;
    END
  END q[347]
  PIN q[348]
    DIRECTION OUTPUT ;
    USE SIGNAL ;
    PORT
      LAYER M4 ;
        RECT  0 54.672 0.084 54.696 ;
    END
  END q[348]
  PIN q[349]
    DIRECTION OUTPUT ;
    USE SIGNAL ;
    PORT
      LAYER M4 ;
        RECT  0 54.768 0.084 54.792 ;
    END
  END q[349]
  PIN q[34]
    DIRECTION OUTPUT ;
    USE SIGNAL ;
    PORT
      LAYER M4 ;
        RECT  0 29.904 0.084 29.928 ;
    END
  END q[34]
  PIN q[350]
    DIRECTION OUTPUT ;
    USE SIGNAL ;
    PORT
      LAYER M4 ;
        RECT  0 54.864 0.084 54.888 ;
    END
  END q[350]
  PIN q[351]
    DIRECTION OUTPUT ;
    USE SIGNAL ;
    PORT
      LAYER M4 ;
        RECT  0 54.96 0.084 54.984 ;
    END
  END q[351]
  PIN q[352]
    DIRECTION OUTPUT ;
    USE SIGNAL ;
    PORT
      LAYER M4 ;
        RECT  0 45.84 0.084 45.864 ;
    END
  END q[352]
  PIN q[353]
    DIRECTION OUTPUT ;
    USE SIGNAL ;
    PORT
      LAYER M4 ;
        RECT  0 45.936 0.084 45.96 ;
    END
  END q[353]
  PIN q[354]
    DIRECTION OUTPUT ;
    USE SIGNAL ;
    PORT
      LAYER M4 ;
        RECT  0 46.032 0.084 46.056 ;
    END
  END q[354]
  PIN q[355]
    DIRECTION OUTPUT ;
    USE SIGNAL ;
    PORT
      LAYER M4 ;
        RECT  0 46.128 0.084 46.152 ;
    END
  END q[355]
  PIN q[356]
    DIRECTION OUTPUT ;
    USE SIGNAL ;
    PORT
      LAYER M4 ;
        RECT  0 46.224 0.084 46.248 ;
    END
  END q[356]
  PIN q[357]
    DIRECTION OUTPUT ;
    USE SIGNAL ;
    PORT
      LAYER M4 ;
        RECT  0 46.32 0.084 46.344 ;
    END
  END q[357]
  PIN q[358]
    DIRECTION OUTPUT ;
    USE SIGNAL ;
    PORT
      LAYER M4 ;
        RECT  0 46.416 0.084 46.44 ;
    END
  END q[358]
  PIN q[359]
    DIRECTION OUTPUT ;
    USE SIGNAL ;
    PORT
      LAYER M4 ;
        RECT  0 46.512 0.084 46.536 ;
    END
  END q[359]
  PIN q[35]
    DIRECTION OUTPUT ;
    USE SIGNAL ;
    PORT
      LAYER M4 ;
        RECT  0 30 0.084 30.024 ;
    END
  END q[35]
  PIN q[360]
    DIRECTION OUTPUT ;
    USE SIGNAL ;
    PORT
      LAYER M4 ;
        RECT  0 46.608 0.084 46.632 ;
    END
  END q[360]
  PIN q[361]
    DIRECTION OUTPUT ;
    USE SIGNAL ;
    PORT
      LAYER M4 ;
        RECT  0 46.704 0.084 46.728 ;
    END
  END q[361]
  PIN q[362]
    DIRECTION OUTPUT ;
    USE SIGNAL ;
    PORT
      LAYER M4 ;
        RECT  0 46.8 0.084 46.824 ;
    END
  END q[362]
  PIN q[363]
    DIRECTION OUTPUT ;
    USE SIGNAL ;
    PORT
      LAYER M4 ;
        RECT  0 46.896 0.084 46.92 ;
    END
  END q[363]
  PIN q[364]
    DIRECTION OUTPUT ;
    USE SIGNAL ;
    PORT
      LAYER M4 ;
        RECT  0 46.992 0.084 47.016 ;
    END
  END q[364]
  PIN q[365]
    DIRECTION OUTPUT ;
    USE SIGNAL ;
    PORT
      LAYER M4 ;
        RECT  0 47.088 0.084 47.112 ;
    END
  END q[365]
  PIN q[366]
    DIRECTION OUTPUT ;
    USE SIGNAL ;
    PORT
      LAYER M4 ;
        RECT  0 47.184 0.084 47.208 ;
    END
  END q[366]
  PIN q[367]
    DIRECTION OUTPUT ;
    USE SIGNAL ;
    PORT
      LAYER M4 ;
        RECT  0 47.28 0.084 47.304 ;
    END
  END q[367]
  PIN q[368]
    DIRECTION OUTPUT ;
    USE SIGNAL ;
    PORT
      LAYER M4 ;
        RECT  0 47.376 0.084 47.4 ;
    END
  END q[368]
  PIN q[369]
    DIRECTION OUTPUT ;
    USE SIGNAL ;
    PORT
      LAYER M4 ;
        RECT  0 47.472 0.084 47.496 ;
    END
  END q[369]
  PIN q[36]
    DIRECTION OUTPUT ;
    USE SIGNAL ;
    PORT
      LAYER M4 ;
        RECT  0 30.096 0.084 30.12 ;
    END
  END q[36]
  PIN q[370]
    DIRECTION OUTPUT ;
    USE SIGNAL ;
    PORT
      LAYER M4 ;
        RECT  0 47.568 0.084 47.592 ;
    END
  END q[370]
  PIN q[371]
    DIRECTION OUTPUT ;
    USE SIGNAL ;
    PORT
      LAYER M4 ;
        RECT  0 47.664 0.084 47.688 ;
    END
  END q[371]
  PIN q[372]
    DIRECTION OUTPUT ;
    USE SIGNAL ;
    PORT
      LAYER M4 ;
        RECT  0 47.76 0.084 47.784 ;
    END
  END q[372]
  PIN q[373]
    DIRECTION OUTPUT ;
    USE SIGNAL ;
    PORT
      LAYER M4 ;
        RECT  0 47.856 0.084 47.88 ;
    END
  END q[373]
  PIN q[374]
    DIRECTION OUTPUT ;
    USE SIGNAL ;
    PORT
      LAYER M4 ;
        RECT  0 47.952 0.084 47.976 ;
    END
  END q[374]
  PIN q[375]
    DIRECTION OUTPUT ;
    USE SIGNAL ;
    PORT
      LAYER M4 ;
        RECT  0 48.048 0.084 48.072 ;
    END
  END q[375]
  PIN q[376]
    DIRECTION OUTPUT ;
    USE SIGNAL ;
    PORT
      LAYER M4 ;
        RECT  0 48.144 0.084 48.168 ;
    END
  END q[376]
  PIN q[377]
    DIRECTION OUTPUT ;
    USE SIGNAL ;
    PORT
      LAYER M4 ;
        RECT  0 48.24 0.084 48.264 ;
    END
  END q[377]
  PIN q[378]
    DIRECTION OUTPUT ;
    USE SIGNAL ;
    PORT
      LAYER M4 ;
        RECT  0 48.336 0.084 48.36 ;
    END
  END q[378]
  PIN q[379]
    DIRECTION OUTPUT ;
    USE SIGNAL ;
    PORT
      LAYER M4 ;
        RECT  0 48.432 0.084 48.456 ;
    END
  END q[379]
  PIN q[37]
    DIRECTION OUTPUT ;
    USE SIGNAL ;
    PORT
      LAYER M4 ;
        RECT  0 30.192 0.084 30.216 ;
    END
  END q[37]
  PIN q[380]
    DIRECTION OUTPUT ;
    USE SIGNAL ;
    PORT
      LAYER M4 ;
        RECT  0 48.528 0.084 48.552 ;
    END
  END q[380]
  PIN q[381]
    DIRECTION OUTPUT ;
    USE SIGNAL ;
    PORT
      LAYER M4 ;
        RECT  0 48.624 0.084 48.648 ;
    END
  END q[381]
  PIN q[382]
    DIRECTION OUTPUT ;
    USE SIGNAL ;
    PORT
      LAYER M4 ;
        RECT  0 48.72 0.084 48.744 ;
    END
  END q[382]
  PIN q[383]
    DIRECTION OUTPUT ;
    USE SIGNAL ;
    PORT
      LAYER M4 ;
        RECT  0 48.816 0.084 48.84 ;
    END
  END q[383]
  PIN q[384]
    DIRECTION OUTPUT ;
    USE SIGNAL ;
    PORT
      LAYER M4 ;
        RECT  0 32.784 0.084 32.808 ;
    END
  END q[384]
  PIN q[385]
    DIRECTION OUTPUT ;
    USE SIGNAL ;
    PORT
      LAYER M4 ;
        RECT  0 32.88 0.084 32.904 ;
    END
  END q[385]
  PIN q[386]
    DIRECTION OUTPUT ;
    USE SIGNAL ;
    PORT
      LAYER M4 ;
        RECT  0 32.976 0.084 33 ;
    END
  END q[386]
  PIN q[387]
    DIRECTION OUTPUT ;
    USE SIGNAL ;
    PORT
      LAYER M4 ;
        RECT  0 33.072 0.084 33.096 ;
    END
  END q[387]
  PIN q[388]
    DIRECTION OUTPUT ;
    USE SIGNAL ;
    PORT
      LAYER M4 ;
        RECT  0 33.168 0.084 33.192 ;
    END
  END q[388]
  PIN q[389]
    DIRECTION OUTPUT ;
    USE SIGNAL ;
    PORT
      LAYER M4 ;
        RECT  0 33.264 0.084 33.288 ;
    END
  END q[389]
  PIN q[38]
    DIRECTION OUTPUT ;
    USE SIGNAL ;
    PORT
      LAYER M4 ;
        RECT  0 30.288 0.084 30.312 ;
    END
  END q[38]
  PIN q[390]
    DIRECTION OUTPUT ;
    USE SIGNAL ;
    PORT
      LAYER M4 ;
        RECT  0 33.36 0.084 33.384 ;
    END
  END q[390]
  PIN q[391]
    DIRECTION OUTPUT ;
    USE SIGNAL ;
    PORT
      LAYER M4 ;
        RECT  0 33.456 0.084 33.48 ;
    END
  END q[391]
  PIN q[392]
    DIRECTION OUTPUT ;
    USE SIGNAL ;
    PORT
      LAYER M4 ;
        RECT  0 33.552 0.084 33.576 ;
    END
  END q[392]
  PIN q[393]
    DIRECTION OUTPUT ;
    USE SIGNAL ;
    PORT
      LAYER M4 ;
        RECT  0 33.648 0.084 33.672 ;
    END
  END q[393]
  PIN q[394]
    DIRECTION OUTPUT ;
    USE SIGNAL ;
    PORT
      LAYER M4 ;
        RECT  0 33.744 0.084 33.768 ;
    END
  END q[394]
  PIN q[395]
    DIRECTION OUTPUT ;
    USE SIGNAL ;
    PORT
      LAYER M4 ;
        RECT  0 33.84 0.084 33.864 ;
    END
  END q[395]
  PIN q[396]
    DIRECTION OUTPUT ;
    USE SIGNAL ;
    PORT
      LAYER M4 ;
        RECT  0 33.936 0.084 33.96 ;
    END
  END q[396]
  PIN q[397]
    DIRECTION OUTPUT ;
    USE SIGNAL ;
    PORT
      LAYER M4 ;
        RECT  0 34.032 0.084 34.056 ;
    END
  END q[397]
  PIN q[398]
    DIRECTION OUTPUT ;
    USE SIGNAL ;
    PORT
      LAYER M4 ;
        RECT  0 34.128 0.084 34.152 ;
    END
  END q[398]
  PIN q[399]
    DIRECTION OUTPUT ;
    USE SIGNAL ;
    PORT
      LAYER M4 ;
        RECT  0 34.224 0.084 34.248 ;
    END
  END q[399]
  PIN q[39]
    DIRECTION OUTPUT ;
    USE SIGNAL ;
    PORT
      LAYER M4 ;
        RECT  0 30.384 0.084 30.408 ;
    END
  END q[39]
  PIN q[3]
    DIRECTION OUTPUT ;
    USE SIGNAL ;
    PORT
      LAYER M4 ;
        RECT  0 20.784 0.084 20.808 ;
    END
  END q[3]
  PIN q[400]
    DIRECTION OUTPUT ;
    USE SIGNAL ;
    PORT
      LAYER M4 ;
        RECT  0 34.32 0.084 34.344 ;
    END
  END q[400]
  PIN q[401]
    DIRECTION OUTPUT ;
    USE SIGNAL ;
    PORT
      LAYER M4 ;
        RECT  0 34.416 0.084 34.44 ;
    END
  END q[401]
  PIN q[402]
    DIRECTION OUTPUT ;
    USE SIGNAL ;
    PORT
      LAYER M4 ;
        RECT  0 34.512 0.084 34.536 ;
    END
  END q[402]
  PIN q[403]
    DIRECTION OUTPUT ;
    USE SIGNAL ;
    PORT
      LAYER M4 ;
        RECT  0 34.608 0.084 34.632 ;
    END
  END q[403]
  PIN q[404]
    DIRECTION OUTPUT ;
    USE SIGNAL ;
    PORT
      LAYER M4 ;
        RECT  0 34.704 0.084 34.728 ;
    END
  END q[404]
  PIN q[405]
    DIRECTION OUTPUT ;
    USE SIGNAL ;
    PORT
      LAYER M4 ;
        RECT  0 34.8 0.084 34.824 ;
    END
  END q[405]
  PIN q[406]
    DIRECTION OUTPUT ;
    USE SIGNAL ;
    PORT
      LAYER M4 ;
        RECT  0 34.896 0.084 34.92 ;
    END
  END q[406]
  PIN q[407]
    DIRECTION OUTPUT ;
    USE SIGNAL ;
    PORT
      LAYER M4 ;
        RECT  0 34.992 0.084 35.016 ;
    END
  END q[407]
  PIN q[408]
    DIRECTION OUTPUT ;
    USE SIGNAL ;
    PORT
      LAYER M4 ;
        RECT  0 35.088 0.084 35.112 ;
    END
  END q[408]
  PIN q[409]
    DIRECTION OUTPUT ;
    USE SIGNAL ;
    PORT
      LAYER M4 ;
        RECT  0 35.184 0.084 35.208 ;
    END
  END q[409]
  PIN q[40]
    DIRECTION OUTPUT ;
    USE SIGNAL ;
    PORT
      LAYER M4 ;
        RECT  0 30.48 0.084 30.504 ;
    END
  END q[40]
  PIN q[410]
    DIRECTION OUTPUT ;
    USE SIGNAL ;
    PORT
      LAYER M4 ;
        RECT  0 35.28 0.084 35.304 ;
    END
  END q[410]
  PIN q[411]
    DIRECTION OUTPUT ;
    USE SIGNAL ;
    PORT
      LAYER M4 ;
        RECT  0 35.376 0.084 35.4 ;
    END
  END q[411]
  PIN q[412]
    DIRECTION OUTPUT ;
    USE SIGNAL ;
    PORT
      LAYER M4 ;
        RECT  0 35.472 0.084 35.496 ;
    END
  END q[412]
  PIN q[413]
    DIRECTION OUTPUT ;
    USE SIGNAL ;
    PORT
      LAYER M4 ;
        RECT  0 35.568 0.084 35.592 ;
    END
  END q[413]
  PIN q[414]
    DIRECTION OUTPUT ;
    USE SIGNAL ;
    PORT
      LAYER M4 ;
        RECT  0 35.664 0.084 35.688 ;
    END
  END q[414]
  PIN q[415]
    DIRECTION OUTPUT ;
    USE SIGNAL ;
    PORT
      LAYER M4 ;
        RECT  0 35.76 0.084 35.784 ;
    END
  END q[415]
  PIN q[416]
    DIRECTION OUTPUT ;
    USE SIGNAL ;
    PORT
      LAYER M4 ;
        RECT  0 39.696 0.084 39.72 ;
    END
  END q[416]
  PIN q[417]
    DIRECTION OUTPUT ;
    USE SIGNAL ;
    PORT
      LAYER M4 ;
        RECT  0 39.792 0.084 39.816 ;
    END
  END q[417]
  PIN q[418]
    DIRECTION OUTPUT ;
    USE SIGNAL ;
    PORT
      LAYER M4 ;
        RECT  0 39.888 0.084 39.912 ;
    END
  END q[418]
  PIN q[419]
    DIRECTION OUTPUT ;
    USE SIGNAL ;
    PORT
      LAYER M4 ;
        RECT  0 39.984 0.084 40.008 ;
    END
  END q[419]
  PIN q[41]
    DIRECTION OUTPUT ;
    USE SIGNAL ;
    PORT
      LAYER M4 ;
        RECT  0 30.576 0.084 30.6 ;
    END
  END q[41]
  PIN q[420]
    DIRECTION OUTPUT ;
    USE SIGNAL ;
    PORT
      LAYER M4 ;
        RECT  0 40.08 0.084 40.104 ;
    END
  END q[420]
  PIN q[421]
    DIRECTION OUTPUT ;
    USE SIGNAL ;
    PORT
      LAYER M4 ;
        RECT  0 40.176 0.084 40.2 ;
    END
  END q[421]
  PIN q[422]
    DIRECTION OUTPUT ;
    USE SIGNAL ;
    PORT
      LAYER M4 ;
        RECT  0 40.272 0.084 40.296 ;
    END
  END q[422]
  PIN q[423]
    DIRECTION OUTPUT ;
    USE SIGNAL ;
    PORT
      LAYER M4 ;
        RECT  0 40.368 0.084 40.392 ;
    END
  END q[423]
  PIN q[424]
    DIRECTION OUTPUT ;
    USE SIGNAL ;
    PORT
      LAYER M4 ;
        RECT  0 40.464 0.084 40.488 ;
    END
  END q[424]
  PIN q[425]
    DIRECTION OUTPUT ;
    USE SIGNAL ;
    PORT
      LAYER M4 ;
        RECT  0 40.56 0.084 40.584 ;
    END
  END q[425]
  PIN q[426]
    DIRECTION OUTPUT ;
    USE SIGNAL ;
    PORT
      LAYER M4 ;
        RECT  0 40.656 0.084 40.68 ;
    END
  END q[426]
  PIN q[427]
    DIRECTION OUTPUT ;
    USE SIGNAL ;
    PORT
      LAYER M4 ;
        RECT  0 40.752 0.084 40.776 ;
    END
  END q[427]
  PIN q[428]
    DIRECTION OUTPUT ;
    USE SIGNAL ;
    PORT
      LAYER M4 ;
        RECT  0 40.848 0.084 40.872 ;
    END
  END q[428]
  PIN q[429]
    DIRECTION OUTPUT ;
    USE SIGNAL ;
    PORT
      LAYER M4 ;
        RECT  0 40.944 0.084 40.968 ;
    END
  END q[429]
  PIN q[42]
    DIRECTION OUTPUT ;
    USE SIGNAL ;
    PORT
      LAYER M4 ;
        RECT  0 30.672 0.084 30.696 ;
    END
  END q[42]
  PIN q[430]
    DIRECTION OUTPUT ;
    USE SIGNAL ;
    PORT
      LAYER M4 ;
        RECT  0 41.04 0.084 41.064 ;
    END
  END q[430]
  PIN q[431]
    DIRECTION OUTPUT ;
    USE SIGNAL ;
    PORT
      LAYER M4 ;
        RECT  0 41.136 0.084 41.16 ;
    END
  END q[431]
  PIN q[432]
    DIRECTION OUTPUT ;
    USE SIGNAL ;
    PORT
      LAYER M4 ;
        RECT  0 41.232 0.084 41.256 ;
    END
  END q[432]
  PIN q[433]
    DIRECTION OUTPUT ;
    USE SIGNAL ;
    PORT
      LAYER M4 ;
        RECT  0 41.328 0.084 41.352 ;
    END
  END q[433]
  PIN q[434]
    DIRECTION OUTPUT ;
    USE SIGNAL ;
    PORT
      LAYER M4 ;
        RECT  0 41.424 0.084 41.448 ;
    END
  END q[434]
  PIN q[435]
    DIRECTION OUTPUT ;
    USE SIGNAL ;
    PORT
      LAYER M4 ;
        RECT  0 41.52 0.084 41.544 ;
    END
  END q[435]
  PIN q[436]
    DIRECTION OUTPUT ;
    USE SIGNAL ;
    PORT
      LAYER M4 ;
        RECT  0 41.616 0.084 41.64 ;
    END
  END q[436]
  PIN q[437]
    DIRECTION OUTPUT ;
    USE SIGNAL ;
    PORT
      LAYER M4 ;
        RECT  0 41.712 0.084 41.736 ;
    END
  END q[437]
  PIN q[438]
    DIRECTION OUTPUT ;
    USE SIGNAL ;
    PORT
      LAYER M4 ;
        RECT  0 41.808 0.084 41.832 ;
    END
  END q[438]
  PIN q[439]
    DIRECTION OUTPUT ;
    USE SIGNAL ;
    PORT
      LAYER M4 ;
        RECT  0 41.904 0.084 41.928 ;
    END
  END q[439]
  PIN q[43]
    DIRECTION OUTPUT ;
    USE SIGNAL ;
    PORT
      LAYER M4 ;
        RECT  0 30.768 0.084 30.792 ;
    END
  END q[43]
  PIN q[440]
    DIRECTION OUTPUT ;
    USE SIGNAL ;
    PORT
      LAYER M4 ;
        RECT  0 42 0.084 42.024 ;
    END
  END q[440]
  PIN q[441]
    DIRECTION OUTPUT ;
    USE SIGNAL ;
    PORT
      LAYER M4 ;
        RECT  0 42.096 0.084 42.12 ;
    END
  END q[441]
  PIN q[442]
    DIRECTION OUTPUT ;
    USE SIGNAL ;
    PORT
      LAYER M4 ;
        RECT  0 42.192 0.084 42.216 ;
    END
  END q[442]
  PIN q[443]
    DIRECTION OUTPUT ;
    USE SIGNAL ;
    PORT
      LAYER M4 ;
        RECT  0 42.288 0.084 42.312 ;
    END
  END q[443]
  PIN q[444]
    DIRECTION OUTPUT ;
    USE SIGNAL ;
    PORT
      LAYER M4 ;
        RECT  0 42.384 0.084 42.408 ;
    END
  END q[444]
  PIN q[445]
    DIRECTION OUTPUT ;
    USE SIGNAL ;
    PORT
      LAYER M4 ;
        RECT  0 42.48 0.084 42.504 ;
    END
  END q[445]
  PIN q[446]
    DIRECTION OUTPUT ;
    USE SIGNAL ;
    PORT
      LAYER M4 ;
        RECT  0 42.576 0.084 42.6 ;
    END
  END q[446]
  PIN q[447]
    DIRECTION OUTPUT ;
    USE SIGNAL ;
    PORT
      LAYER M4 ;
        RECT  0 42.672 0.084 42.696 ;
    END
  END q[447]
  PIN q[448]
    DIRECTION OUTPUT ;
    USE SIGNAL ;
    PORT
      LAYER M4 ;
        RECT  0 42.768 0.084 42.792 ;
    END
  END q[448]
  PIN q[449]
    DIRECTION OUTPUT ;
    USE SIGNAL ;
    PORT
      LAYER M4 ;
        RECT  0 42.864 0.084 42.888 ;
    END
  END q[449]
  PIN q[44]
    DIRECTION OUTPUT ;
    USE SIGNAL ;
    PORT
      LAYER M4 ;
        RECT  0 30.864 0.084 30.888 ;
    END
  END q[44]
  PIN q[450]
    DIRECTION OUTPUT ;
    USE SIGNAL ;
    PORT
      LAYER M4 ;
        RECT  0 42.96 0.084 42.984 ;
    END
  END q[450]
  PIN q[451]
    DIRECTION OUTPUT ;
    USE SIGNAL ;
    PORT
      LAYER M4 ;
        RECT  0 43.056 0.084 43.08 ;
    END
  END q[451]
  PIN q[452]
    DIRECTION OUTPUT ;
    USE SIGNAL ;
    PORT
      LAYER M4 ;
        RECT  0 43.152 0.084 43.176 ;
    END
  END q[452]
  PIN q[453]
    DIRECTION OUTPUT ;
    USE SIGNAL ;
    PORT
      LAYER M4 ;
        RECT  0 43.248 0.084 43.272 ;
    END
  END q[453]
  PIN q[454]
    DIRECTION OUTPUT ;
    USE SIGNAL ;
    PORT
      LAYER M4 ;
        RECT  0 43.344 0.084 43.368 ;
    END
  END q[454]
  PIN q[455]
    DIRECTION OUTPUT ;
    USE SIGNAL ;
    PORT
      LAYER M4 ;
        RECT  0 43.44 0.084 43.464 ;
    END
  END q[455]
  PIN q[456]
    DIRECTION OUTPUT ;
    USE SIGNAL ;
    PORT
      LAYER M4 ;
        RECT  0 43.536 0.084 43.56 ;
    END
  END q[456]
  PIN q[457]
    DIRECTION OUTPUT ;
    USE SIGNAL ;
    PORT
      LAYER M4 ;
        RECT  0 43.632 0.084 43.656 ;
    END
  END q[457]
  PIN q[458]
    DIRECTION OUTPUT ;
    USE SIGNAL ;
    PORT
      LAYER M4 ;
        RECT  0 43.728 0.084 43.752 ;
    END
  END q[458]
  PIN q[459]
    DIRECTION OUTPUT ;
    USE SIGNAL ;
    PORT
      LAYER M4 ;
        RECT  0 43.824 0.084 43.848 ;
    END
  END q[459]
  PIN q[45]
    DIRECTION OUTPUT ;
    USE SIGNAL ;
    PORT
      LAYER M4 ;
        RECT  0 30.96 0.084 30.984 ;
    END
  END q[45]
  PIN q[460]
    DIRECTION OUTPUT ;
    USE SIGNAL ;
    PORT
      LAYER M4 ;
        RECT  0 43.92 0.084 43.944 ;
    END
  END q[460]
  PIN q[461]
    DIRECTION OUTPUT ;
    USE SIGNAL ;
    PORT
      LAYER M4 ;
        RECT  0 44.016 0.084 44.04 ;
    END
  END q[461]
  PIN q[462]
    DIRECTION OUTPUT ;
    USE SIGNAL ;
    PORT
      LAYER M4 ;
        RECT  0 44.112 0.084 44.136 ;
    END
  END q[462]
  PIN q[463]
    DIRECTION OUTPUT ;
    USE SIGNAL ;
    PORT
      LAYER M4 ;
        RECT  0 44.208 0.084 44.232 ;
    END
  END q[463]
  PIN q[464]
    DIRECTION OUTPUT ;
    USE SIGNAL ;
    PORT
      LAYER M4 ;
        RECT  0 44.304 0.084 44.328 ;
    END
  END q[464]
  PIN q[465]
    DIRECTION OUTPUT ;
    USE SIGNAL ;
    PORT
      LAYER M4 ;
        RECT  0 44.4 0.084 44.424 ;
    END
  END q[465]
  PIN q[466]
    DIRECTION OUTPUT ;
    USE SIGNAL ;
    PORT
      LAYER M4 ;
        RECT  0 44.496 0.084 44.52 ;
    END
  END q[466]
  PIN q[467]
    DIRECTION OUTPUT ;
    USE SIGNAL ;
    PORT
      LAYER M4 ;
        RECT  0 44.592 0.084 44.616 ;
    END
  END q[467]
  PIN q[468]
    DIRECTION OUTPUT ;
    USE SIGNAL ;
    PORT
      LAYER M4 ;
        RECT  0 44.688 0.084 44.712 ;
    END
  END q[468]
  PIN q[469]
    DIRECTION OUTPUT ;
    USE SIGNAL ;
    PORT
      LAYER M4 ;
        RECT  0 44.784 0.084 44.808 ;
    END
  END q[469]
  PIN q[46]
    DIRECTION OUTPUT ;
    USE SIGNAL ;
    PORT
      LAYER M4 ;
        RECT  0 31.056 0.084 31.08 ;
    END
  END q[46]
  PIN q[470]
    DIRECTION OUTPUT ;
    USE SIGNAL ;
    PORT
      LAYER M4 ;
        RECT  0 44.88 0.084 44.904 ;
    END
  END q[470]
  PIN q[471]
    DIRECTION OUTPUT ;
    USE SIGNAL ;
    PORT
      LAYER M4 ;
        RECT  0 44.976 0.084 45 ;
    END
  END q[471]
  PIN q[472]
    DIRECTION OUTPUT ;
    USE SIGNAL ;
    PORT
      LAYER M4 ;
        RECT  0 45.072 0.084 45.096 ;
    END
  END q[472]
  PIN q[473]
    DIRECTION OUTPUT ;
    USE SIGNAL ;
    PORT
      LAYER M4 ;
        RECT  0 45.168 0.084 45.192 ;
    END
  END q[473]
  PIN q[474]
    DIRECTION OUTPUT ;
    USE SIGNAL ;
    PORT
      LAYER M4 ;
        RECT  0 45.264 0.084 45.288 ;
    END
  END q[474]
  PIN q[475]
    DIRECTION OUTPUT ;
    USE SIGNAL ;
    PORT
      LAYER M4 ;
        RECT  0 45.36 0.084 45.384 ;
    END
  END q[475]
  PIN q[476]
    DIRECTION OUTPUT ;
    USE SIGNAL ;
    PORT
      LAYER M4 ;
        RECT  0 45.456 0.084 45.48 ;
    END
  END q[476]
  PIN q[477]
    DIRECTION OUTPUT ;
    USE SIGNAL ;
    PORT
      LAYER M4 ;
        RECT  0 45.552 0.084 45.576 ;
    END
  END q[477]
  PIN q[478]
    DIRECTION OUTPUT ;
    USE SIGNAL ;
    PORT
      LAYER M4 ;
        RECT  0 45.648 0.084 45.672 ;
    END
  END q[478]
  PIN q[479]
    DIRECTION OUTPUT ;
    USE SIGNAL ;
    PORT
      LAYER M4 ;
        RECT  0 45.744 0.084 45.768 ;
    END
  END q[479]
  PIN q[47]
    DIRECTION OUTPUT ;
    USE SIGNAL ;
    PORT
      LAYER M4 ;
        RECT  0 31.152 0.084 31.176 ;
    END
  END q[47]
  PIN q[480]
    DIRECTION OUTPUT ;
    USE SIGNAL ;
    PORT
      LAYER M4 ;
        RECT  0 35.856 0.084 35.88 ;
    END
  END q[480]
  PIN q[481]
    DIRECTION OUTPUT ;
    USE SIGNAL ;
    PORT
      LAYER M4 ;
        RECT  0 35.952 0.084 35.976 ;
    END
  END q[481]
  PIN q[482]
    DIRECTION OUTPUT ;
    USE SIGNAL ;
    PORT
      LAYER M4 ;
        RECT  0 36.048 0.084 36.072 ;
    END
  END q[482]
  PIN q[483]
    DIRECTION OUTPUT ;
    USE SIGNAL ;
    PORT
      LAYER M4 ;
        RECT  0 36.144 0.084 36.168 ;
    END
  END q[483]
  PIN q[484]
    DIRECTION OUTPUT ;
    USE SIGNAL ;
    PORT
      LAYER M4 ;
        RECT  0 36.24 0.084 36.264 ;
    END
  END q[484]
  PIN q[485]
    DIRECTION OUTPUT ;
    USE SIGNAL ;
    PORT
      LAYER M4 ;
        RECT  0 36.336 0.084 36.36 ;
    END
  END q[485]
  PIN q[486]
    DIRECTION OUTPUT ;
    USE SIGNAL ;
    PORT
      LAYER M4 ;
        RECT  0 36.432 0.084 36.456 ;
    END
  END q[486]
  PIN q[487]
    DIRECTION OUTPUT ;
    USE SIGNAL ;
    PORT
      LAYER M4 ;
        RECT  0 36.528 0.084 36.552 ;
    END
  END q[487]
  PIN q[488]
    DIRECTION OUTPUT ;
    USE SIGNAL ;
    PORT
      LAYER M4 ;
        RECT  0 36.624 0.084 36.648 ;
    END
  END q[488]
  PIN q[489]
    DIRECTION OUTPUT ;
    USE SIGNAL ;
    PORT
      LAYER M4 ;
        RECT  0 36.72 0.084 36.744 ;
    END
  END q[489]
  PIN q[48]
    DIRECTION OUTPUT ;
    USE SIGNAL ;
    PORT
      LAYER M4 ;
        RECT  0 31.248 0.084 31.272 ;
    END
  END q[48]
  PIN q[490]
    DIRECTION OUTPUT ;
    USE SIGNAL ;
    PORT
      LAYER M4 ;
        RECT  0 36.816 0.084 36.84 ;
    END
  END q[490]
  PIN q[491]
    DIRECTION OUTPUT ;
    USE SIGNAL ;
    PORT
      LAYER M4 ;
        RECT  0 36.912 0.084 36.936 ;
    END
  END q[491]
  PIN q[492]
    DIRECTION OUTPUT ;
    USE SIGNAL ;
    PORT
      LAYER M4 ;
        RECT  0 37.008 0.084 37.032 ;
    END
  END q[492]
  PIN q[493]
    DIRECTION OUTPUT ;
    USE SIGNAL ;
    PORT
      LAYER M4 ;
        RECT  0 37.104 0.084 37.128 ;
    END
  END q[493]
  PIN q[494]
    DIRECTION OUTPUT ;
    USE SIGNAL ;
    PORT
      LAYER M4 ;
        RECT  0 37.2 0.084 37.224 ;
    END
  END q[494]
  PIN q[495]
    DIRECTION OUTPUT ;
    USE SIGNAL ;
    PORT
      LAYER M4 ;
        RECT  0 37.296 0.084 37.32 ;
    END
  END q[495]
  PIN q[496]
    DIRECTION OUTPUT ;
    USE SIGNAL ;
    PORT
      LAYER M4 ;
        RECT  0 37.392 0.084 37.416 ;
    END
  END q[496]
  PIN q[497]
    DIRECTION OUTPUT ;
    USE SIGNAL ;
    PORT
      LAYER M4 ;
        RECT  0 37.488 0.084 37.512 ;
    END
  END q[497]
  PIN q[498]
    DIRECTION OUTPUT ;
    USE SIGNAL ;
    PORT
      LAYER M4 ;
        RECT  0 37.584 0.084 37.608 ;
    END
  END q[498]
  PIN q[499]
    DIRECTION OUTPUT ;
    USE SIGNAL ;
    PORT
      LAYER M4 ;
        RECT  0 37.68 0.084 37.704 ;
    END
  END q[499]
  PIN q[49]
    DIRECTION OUTPUT ;
    USE SIGNAL ;
    PORT
      LAYER M4 ;
        RECT  0 31.344 0.084 31.368 ;
    END
  END q[49]
  PIN q[4]
    DIRECTION OUTPUT ;
    USE SIGNAL ;
    PORT
      LAYER M4 ;
        RECT  0 20.88 0.084 20.904 ;
    END
  END q[4]
  PIN q[500]
    DIRECTION OUTPUT ;
    USE SIGNAL ;
    PORT
      LAYER M4 ;
        RECT  0 37.776 0.084 37.8 ;
    END
  END q[500]
  PIN q[501]
    DIRECTION OUTPUT ;
    USE SIGNAL ;
    PORT
      LAYER M4 ;
        RECT  0 37.872 0.084 37.896 ;
    END
  END q[501]
  PIN q[502]
    DIRECTION OUTPUT ;
    USE SIGNAL ;
    PORT
      LAYER M4 ;
        RECT  0 37.968 0.084 37.992 ;
    END
  END q[502]
  PIN q[503]
    DIRECTION OUTPUT ;
    USE SIGNAL ;
    PORT
      LAYER M4 ;
        RECT  0 38.064 0.084 38.088 ;
    END
  END q[503]
  PIN q[504]
    DIRECTION OUTPUT ;
    USE SIGNAL ;
    PORT
      LAYER M4 ;
        RECT  0 38.16 0.084 38.184 ;
    END
  END q[504]
  PIN q[505]
    DIRECTION OUTPUT ;
    USE SIGNAL ;
    PORT
      LAYER M4 ;
        RECT  0 38.256 0.084 38.28 ;
    END
  END q[505]
  PIN q[506]
    DIRECTION OUTPUT ;
    USE SIGNAL ;
    PORT
      LAYER M4 ;
        RECT  0 38.352 0.084 38.376 ;
    END
  END q[506]
  PIN q[507]
    DIRECTION OUTPUT ;
    USE SIGNAL ;
    PORT
      LAYER M4 ;
        RECT  0 38.448 0.084 38.472 ;
    END
  END q[507]
  PIN q[508]
    DIRECTION OUTPUT ;
    USE SIGNAL ;
    PORT
      LAYER M4 ;
        RECT  0 38.544 0.084 38.568 ;
    END
  END q[508]
  PIN q[509]
    DIRECTION OUTPUT ;
    USE SIGNAL ;
    PORT
      LAYER M4 ;
        RECT  0 38.64 0.084 38.664 ;
    END
  END q[509]
  PIN q[50]
    DIRECTION OUTPUT ;
    USE SIGNAL ;
    PORT
      LAYER M4 ;
        RECT  0 31.44 0.084 31.464 ;
    END
  END q[50]
  PIN q[510]
    DIRECTION OUTPUT ;
    USE SIGNAL ;
    PORT
      LAYER M4 ;
        RECT  0 38.736 0.084 38.76 ;
    END
  END q[510]
  PIN q[511]
    DIRECTION OUTPUT ;
    USE SIGNAL ;
    PORT
      LAYER M4 ;
        RECT  0 38.832 0.084 38.856 ;
    END
  END q[511]
  PIN q[51]
    DIRECTION OUTPUT ;
    USE SIGNAL ;
    PORT
      LAYER M4 ;
        RECT  0 31.536 0.084 31.56 ;
    END
  END q[51]
  PIN q[52]
    DIRECTION OUTPUT ;
    USE SIGNAL ;
    PORT
      LAYER M4 ;
        RECT  0 31.632 0.084 31.656 ;
    END
  END q[52]
  PIN q[53]
    DIRECTION OUTPUT ;
    USE SIGNAL ;
    PORT
      LAYER M4 ;
        RECT  0 31.728 0.084 31.752 ;
    END
  END q[53]
  PIN q[54]
    DIRECTION OUTPUT ;
    USE SIGNAL ;
    PORT
      LAYER M4 ;
        RECT  0 31.824 0.084 31.848 ;
    END
  END q[54]
  PIN q[55]
    DIRECTION OUTPUT ;
    USE SIGNAL ;
    PORT
      LAYER M4 ;
        RECT  0 31.92 0.084 31.944 ;
    END
  END q[55]
  PIN q[56]
    DIRECTION OUTPUT ;
    USE SIGNAL ;
    PORT
      LAYER M4 ;
        RECT  0 32.016 0.084 32.04 ;
    END
  END q[56]
  PIN q[57]
    DIRECTION OUTPUT ;
    USE SIGNAL ;
    PORT
      LAYER M4 ;
        RECT  0 32.112 0.084 32.136 ;
    END
  END q[57]
  PIN q[58]
    DIRECTION OUTPUT ;
    USE SIGNAL ;
    PORT
      LAYER M4 ;
        RECT  0 32.208 0.084 32.232 ;
    END
  END q[58]
  PIN q[59]
    DIRECTION OUTPUT ;
    USE SIGNAL ;
    PORT
      LAYER M4 ;
        RECT  0 32.304 0.084 32.328 ;
    END
  END q[59]
  PIN q[5]
    DIRECTION OUTPUT ;
    USE SIGNAL ;
    PORT
      LAYER M4 ;
        RECT  0 20.976 0.084 21 ;
    END
  END q[5]
  PIN q[60]
    DIRECTION OUTPUT ;
    USE SIGNAL ;
    PORT
      LAYER M4 ;
        RECT  0 32.4 0.084 32.424 ;
    END
  END q[60]
  PIN q[61]
    DIRECTION OUTPUT ;
    USE SIGNAL ;
    PORT
      LAYER M4 ;
        RECT  0 32.496 0.084 32.52 ;
    END
  END q[61]
  PIN q[62]
    DIRECTION OUTPUT ;
    USE SIGNAL ;
    PORT
      LAYER M4 ;
        RECT  0 32.592 0.084 32.616 ;
    END
  END q[62]
  PIN q[63]
    DIRECTION OUTPUT ;
    USE SIGNAL ;
    PORT
      LAYER M4 ;
        RECT  0 32.688 0.084 32.712 ;
    END
  END q[63]
  PIN q[64]
    DIRECTION OUTPUT ;
    USE SIGNAL ;
    PORT
      LAYER M4 ;
        RECT  0 26.64 0.084 26.664 ;
    END
  END q[64]
  PIN q[65]
    DIRECTION OUTPUT ;
    USE SIGNAL ;
    PORT
      LAYER M4 ;
        RECT  0 26.736 0.084 26.76 ;
    END
  END q[65]
  PIN q[66]
    DIRECTION OUTPUT ;
    USE SIGNAL ;
    PORT
      LAYER M4 ;
        RECT  0 26.832 0.084 26.856 ;
    END
  END q[66]
  PIN q[67]
    DIRECTION OUTPUT ;
    USE SIGNAL ;
    PORT
      LAYER M4 ;
        RECT  0 26.928 0.084 26.952 ;
    END
  END q[67]
  PIN q[68]
    DIRECTION OUTPUT ;
    USE SIGNAL ;
    PORT
      LAYER M4 ;
        RECT  0 27.024 0.084 27.048 ;
    END
  END q[68]
  PIN q[69]
    DIRECTION OUTPUT ;
    USE SIGNAL ;
    PORT
      LAYER M4 ;
        RECT  0 27.12 0.084 27.144 ;
    END
  END q[69]
  PIN q[6]
    DIRECTION OUTPUT ;
    USE SIGNAL ;
    PORT
      LAYER M4 ;
        RECT  0 21.072 0.084 21.096 ;
    END
  END q[6]
  PIN q[70]
    DIRECTION OUTPUT ;
    USE SIGNAL ;
    PORT
      LAYER M4 ;
        RECT  0 27.216 0.084 27.24 ;
    END
  END q[70]
  PIN q[71]
    DIRECTION OUTPUT ;
    USE SIGNAL ;
    PORT
      LAYER M4 ;
        RECT  0 27.312 0.084 27.336 ;
    END
  END q[71]
  PIN q[72]
    DIRECTION OUTPUT ;
    USE SIGNAL ;
    PORT
      LAYER M4 ;
        RECT  0 27.408 0.084 27.432 ;
    END
  END q[72]
  PIN q[73]
    DIRECTION OUTPUT ;
    USE SIGNAL ;
    PORT
      LAYER M4 ;
        RECT  0 27.504 0.084 27.528 ;
    END
  END q[73]
  PIN q[74]
    DIRECTION OUTPUT ;
    USE SIGNAL ;
    PORT
      LAYER M4 ;
        RECT  0 27.6 0.084 27.624 ;
    END
  END q[74]
  PIN q[75]
    DIRECTION OUTPUT ;
    USE SIGNAL ;
    PORT
      LAYER M4 ;
        RECT  0 27.696 0.084 27.72 ;
    END
  END q[75]
  PIN q[76]
    DIRECTION OUTPUT ;
    USE SIGNAL ;
    PORT
      LAYER M4 ;
        RECT  0 27.792 0.084 27.816 ;
    END
  END q[76]
  PIN q[77]
    DIRECTION OUTPUT ;
    USE SIGNAL ;
    PORT
      LAYER M4 ;
        RECT  0 27.888 0.084 27.912 ;
    END
  END q[77]
  PIN q[78]
    DIRECTION OUTPUT ;
    USE SIGNAL ;
    PORT
      LAYER M4 ;
        RECT  0 27.984 0.084 28.008 ;
    END
  END q[78]
  PIN q[79]
    DIRECTION OUTPUT ;
    USE SIGNAL ;
    PORT
      LAYER M4 ;
        RECT  0 28.08 0.084 28.104 ;
    END
  END q[79]
  PIN q[7]
    DIRECTION OUTPUT ;
    USE SIGNAL ;
    PORT
      LAYER M4 ;
        RECT  0 21.168 0.084 21.192 ;
    END
  END q[7]
  PIN q[80]
    DIRECTION OUTPUT ;
    USE SIGNAL ;
    PORT
      LAYER M4 ;
        RECT  0 28.176 0.084 28.2 ;
    END
  END q[80]
  PIN q[81]
    DIRECTION OUTPUT ;
    USE SIGNAL ;
    PORT
      LAYER M4 ;
        RECT  0 28.272 0.084 28.296 ;
    END
  END q[81]
  PIN q[82]
    DIRECTION OUTPUT ;
    USE SIGNAL ;
    PORT
      LAYER M4 ;
        RECT  0 28.368 0.084 28.392 ;
    END
  END q[82]
  PIN q[83]
    DIRECTION OUTPUT ;
    USE SIGNAL ;
    PORT
      LAYER M4 ;
        RECT  0 28.464 0.084 28.488 ;
    END
  END q[83]
  PIN q[84]
    DIRECTION OUTPUT ;
    USE SIGNAL ;
    PORT
      LAYER M4 ;
        RECT  0 28.56 0.084 28.584 ;
    END
  END q[84]
  PIN q[85]
    DIRECTION OUTPUT ;
    USE SIGNAL ;
    PORT
      LAYER M4 ;
        RECT  0 28.656 0.084 28.68 ;
    END
  END q[85]
  PIN q[86]
    DIRECTION OUTPUT ;
    USE SIGNAL ;
    PORT
      LAYER M4 ;
        RECT  0 28.752 0.084 28.776 ;
    END
  END q[86]
  PIN q[87]
    DIRECTION OUTPUT ;
    USE SIGNAL ;
    PORT
      LAYER M4 ;
        RECT  0 28.848 0.084 28.872 ;
    END
  END q[87]
  PIN q[88]
    DIRECTION OUTPUT ;
    USE SIGNAL ;
    PORT
      LAYER M4 ;
        RECT  0 28.944 0.084 28.968 ;
    END
  END q[88]
  PIN q[89]
    DIRECTION OUTPUT ;
    USE SIGNAL ;
    PORT
      LAYER M4 ;
        RECT  0 29.04 0.084 29.064 ;
    END
  END q[89]
  PIN q[8]
    DIRECTION OUTPUT ;
    USE SIGNAL ;
    PORT
      LAYER M4 ;
        RECT  0 21.264 0.084 21.288 ;
    END
  END q[8]
  PIN q[90]
    DIRECTION OUTPUT ;
    USE SIGNAL ;
    PORT
      LAYER M4 ;
        RECT  0 29.136 0.084 29.16 ;
    END
  END q[90]
  PIN q[91]
    DIRECTION OUTPUT ;
    USE SIGNAL ;
    PORT
      LAYER M4 ;
        RECT  0 29.232 0.084 29.256 ;
    END
  END q[91]
  PIN q[92]
    DIRECTION OUTPUT ;
    USE SIGNAL ;
    PORT
      LAYER M4 ;
        RECT  0 29.328 0.084 29.352 ;
    END
  END q[92]
  PIN q[93]
    DIRECTION OUTPUT ;
    USE SIGNAL ;
    PORT
      LAYER M4 ;
        RECT  0 29.424 0.084 29.448 ;
    END
  END q[93]
  PIN q[94]
    DIRECTION OUTPUT ;
    USE SIGNAL ;
    PORT
      LAYER M4 ;
        RECT  0 29.52 0.084 29.544 ;
    END
  END q[94]
  PIN q[95]
    DIRECTION OUTPUT ;
    USE SIGNAL ;
    PORT
      LAYER M4 ;
        RECT  0 29.616 0.084 29.64 ;
    END
  END q[95]
  PIN q[96]
    DIRECTION OUTPUT ;
    USE SIGNAL ;
    PORT
      LAYER M4 ;
        RECT  0 23.568 0.084 23.592 ;
    END
  END q[96]
  PIN q[97]
    DIRECTION OUTPUT ;
    USE SIGNAL ;
    PORT
      LAYER M4 ;
        RECT  0 23.664 0.084 23.688 ;
    END
  END q[97]
  PIN q[98]
    DIRECTION OUTPUT ;
    USE SIGNAL ;
    PORT
      LAYER M4 ;
        RECT  0 23.76 0.084 23.784 ;
    END
  END q[98]
  PIN q[99]
    DIRECTION OUTPUT ;
    USE SIGNAL ;
    PORT
      LAYER M4 ;
        RECT  0 23.856 0.084 23.88 ;
    END
  END q[99]
  PIN q[9]
    DIRECTION OUTPUT ;
    USE SIGNAL ;
    PORT
      LAYER M4 ;
        RECT  0 21.36 0.084 21.384 ;
    END
  END q[9]
  PIN VDD
    DIRECTION INOUT ;
    USE POWER ;
    PORT
      LAYER M5 ;
        RECT  13.392 2.151 13.512 95.049 ;
        RECT  7.992 2.151 8.112 95.049 ;
        RECT  2.592 2.151 2.712 95.049 ;
    END
  END VDD
  PIN VSS
    DIRECTION INOUT ;
    USE GROUND ;
    PORT
      LAYER M5 ;
        RECT  13.2 2.137 13.32 95.063 ;
        RECT  7.8 2.137 7.92 95.063 ;
        RECT  2.4 2.137 2.52 95.063 ;
    END
  END VSS
  # OT_OBS_CLOSED layer=M5 d_um=1.536 added=100
  OBS
    LAYER RVTN ;
     RECT  2.16 2.16 15.12 2.295 ;
     RECT  2.16 2.565 15.12 2.835 ;
     RECT  2.16 3.105 15.12 3.375 ;
     RECT  2.16 3.645 15.12 3.915 ;
     RECT  2.16 4.185 15.12 4.455 ;
     RECT  2.16 4.725 15.12 4.995 ;
     RECT  2.16 5.265 15.12 5.535 ;
     RECT  2.16 5.805 15.12 6.075 ;
     RECT  2.16 6.345 15.12 6.615 ;
     RECT  2.16 6.885 15.12 7.155 ;
     RECT  2.16 7.425 15.12 7.695 ;
     RECT  2.16 7.965 15.12 8.235 ;
     RECT  2.16 8.505 15.12 8.775 ;
     RECT  2.16 9.045 15.12 9.315 ;
     RECT  2.16 9.585 15.12 9.855 ;
     RECT  2.16 10.125 15.12 10.395 ;
     RECT  2.16 10.665 15.12 10.935 ;
     RECT  2.16 11.205 15.12 11.475 ;
     RECT  2.16 11.745 15.12 12.015 ;
     RECT  2.16 12.285 15.12 12.555 ;
     RECT  2.16 12.825 15.12 13.095 ;
     RECT  2.16 13.365 15.12 13.635 ;
     RECT  2.16 13.905 15.12 14.175 ;
     RECT  2.16 14.445 15.12 14.715 ;
     RECT  2.16 14.985 15.12 15.255 ;
     RECT  2.16 15.525 15.12 15.795 ;
     RECT  2.16 16.065 15.12 16.335 ;
     RECT  2.16 16.605 15.12 16.875 ;
     RECT  2.16 17.145 15.12 17.415 ;
     RECT  2.16 17.685 15.12 17.955 ;
     RECT  2.16 18.225 15.12 18.495 ;
     RECT  2.16 18.765 15.12 19.035 ;
     RECT  2.16 19.305 15.12 19.575 ;
     RECT  2.16 19.845 15.12 20.115 ;
     RECT  2.16 20.385 15.12 20.655 ;
     RECT  2.16 20.925 15.12 21.195 ;
     RECT  2.16 21.465 15.12 21.735 ;
     RECT  2.16 22.005 15.12 22.275 ;
     RECT  2.16 22.545 15.12 22.815 ;
     RECT  2.16 23.085 15.12 23.355 ;
     RECT  2.16 23.625 15.12 23.895 ;
     RECT  2.16 24.165 15.12 24.435 ;
     RECT  2.16 24.705 15.12 24.975 ;
     RECT  2.16 25.245 15.12 25.515 ;
     RECT  2.16 25.785 15.12 26.055 ;
     RECT  2.16 26.325 15.12 26.595 ;
     RECT  2.16 26.865 15.12 27.135 ;
     RECT  2.16 27.405 15.12 27.675 ;
     RECT  2.16 27.945 15.12 28.215 ;
     RECT  2.16 28.485 15.12 28.755 ;
     RECT  2.16 29.025 15.12 29.295 ;
     RECT  2.16 29.565 15.12 29.835 ;
     RECT  2.16 30.105 15.12 30.375 ;
     RECT  2.16 30.645 15.12 30.915 ;
     RECT  2.16 31.185 15.12 31.455 ;
     RECT  2.16 31.725 15.12 31.995 ;
     RECT  2.16 32.265 15.12 32.535 ;
     RECT  2.16 32.805 15.12 33.075 ;
     RECT  2.16 33.345 15.12 33.615 ;
     RECT  2.16 33.885 15.12 34.155 ;
     RECT  2.16 34.425 15.12 34.695 ;
     RECT  2.16 34.965 15.12 35.235 ;
     RECT  2.16 35.505 15.12 35.775 ;
     RECT  2.16 36.045 15.12 36.315 ;
     RECT  2.16 36.585 15.12 36.855 ;
     RECT  2.16 37.125 15.12 37.395 ;
     RECT  2.16 37.665 15.12 37.935 ;
     RECT  2.16 38.205 15.12 38.475 ;
     RECT  2.16 38.745 15.12 39.015 ;
     RECT  2.16 39.285 15.12 39.555 ;
     RECT  2.16 39.825 15.12 40.095 ;
     RECT  2.16 40.365 15.12 40.635 ;
     RECT  2.16 40.905 15.12 41.175 ;
     RECT  2.16 41.445 15.12 41.715 ;
     RECT  2.16 41.985 15.12 42.255 ;
     RECT  2.16 42.525 15.12 42.795 ;
     RECT  2.16 43.065 15.12 43.335 ;
     RECT  2.16 43.605 15.12 43.875 ;
     RECT  2.16 44.145 15.12 44.415 ;
     RECT  2.16 44.685 15.12 44.955 ;
     RECT  2.16 45.225 15.12 45.495 ;
     RECT  2.16 45.765 15.12 46.035 ;
     RECT  2.16 46.305 15.12 46.575 ;
     RECT  2.16 46.845 15.12 47.115 ;
     RECT  2.16 47.385 15.12 47.655 ;
     RECT  2.16 47.925 15.12 48.195 ;
     RECT  2.16 48.465 15.12 48.735 ;
     RECT  2.16 49.005 15.12 49.275 ;
     RECT  2.16 49.545 15.12 49.815 ;
     RECT  2.16 50.085 15.12 50.355 ;
     RECT  2.16 50.625 15.12 50.895 ;
     RECT  2.16 51.165 15.12 51.435 ;
     RECT  2.16 51.705 15.12 51.975 ;
     RECT  2.16 52.245 15.12 52.515 ;
     RECT  2.16 52.785 15.12 53.055 ;
     RECT  2.16 53.325 15.12 53.595 ;
     RECT  2.16 53.865 15.12 54.135 ;
     RECT  2.16 54.405 15.12 54.675 ;
     RECT  2.16 54.945 15.12 55.215 ;
     RECT  2.16 55.485 15.12 55.755 ;
     RECT  2.16 56.025 15.12 56.295 ;
     RECT  2.16 56.565 15.12 56.835 ;
     RECT  2.16 57.105 15.12 57.375 ;
     RECT  2.16 57.645 15.12 57.915 ;
     RECT  2.16 58.185 15.12 58.455 ;
     RECT  2.16 58.725 15.12 58.995 ;
     RECT  2.16 59.265 15.12 59.535 ;
     RECT  2.16 59.805 15.12 60.075 ;
     RECT  2.16 60.345 15.12 60.615 ;
     RECT  2.16 60.885 15.12 61.155 ;
     RECT  2.16 61.425 15.12 61.695 ;
     RECT  2.16 61.965 15.12 62.235 ;
     RECT  2.16 62.505 15.12 62.775 ;
     RECT  2.16 63.045 15.12 63.315 ;
     RECT  2.16 63.585 15.12 63.855 ;
     RECT  2.16 64.125 15.12 64.395 ;
     RECT  2.16 64.665 15.12 64.935 ;
     RECT  2.16 65.205 15.12 65.475 ;
     RECT  2.16 65.745 15.12 66.015 ;
     RECT  2.16 66.285 15.12 66.555 ;
     RECT  2.16 66.825 15.12 67.095 ;
     RECT  2.16 67.365 15.12 67.635 ;
     RECT  2.16 67.905 15.12 68.175 ;
     RECT  2.16 68.445 15.12 68.715 ;
     RECT  2.16 68.985 15.12 69.255 ;
     RECT  2.16 69.525 15.12 69.795 ;
     RECT  2.16 70.065 15.12 70.335 ;
     RECT  2.16 70.605 15.12 70.875 ;
     RECT  2.16 71.145 15.12 71.415 ;
     RECT  2.16 71.685 15.12 71.955 ;
     RECT  2.16 72.225 15.12 72.495 ;
     RECT  2.16 72.765 15.12 73.035 ;
     RECT  2.16 73.305 15.12 73.575 ;
     RECT  2.16 73.845 15.12 74.115 ;
     RECT  2.16 74.385 15.12 74.655 ;
     RECT  2.16 74.925 15.12 75.195 ;
     RECT  2.16 75.465 15.12 75.735 ;
     RECT  2.16 76.005 15.12 76.275 ;
     RECT  2.16 76.545 15.12 76.815 ;
     RECT  2.16 77.085 15.12 77.355 ;
     RECT  2.16 77.625 15.12 77.895 ;
     RECT  2.16 78.165 15.12 78.435 ;
     RECT  2.16 78.705 15.12 78.975 ;
     RECT  2.16 79.245 15.12 79.515 ;
     RECT  2.16 79.785 15.12 80.055 ;
     RECT  2.16 80.325 15.12 80.595 ;
     RECT  2.16 80.865 15.12 81.135 ;
     RECT  2.16 81.405 15.12 81.675 ;
     RECT  2.16 81.945 15.12 82.215 ;
     RECT  2.16 82.485 15.12 82.755 ;
     RECT  2.16 83.025 15.12 83.295 ;
     RECT  2.16 83.565 15.12 83.835 ;
     RECT  2.16 84.105 15.12 84.375 ;
     RECT  2.16 84.645 15.12 84.915 ;
     RECT  2.16 85.185 15.12 85.455 ;
     RECT  2.16 85.725 15.12 85.995 ;
     RECT  2.16 86.265 15.12 86.535 ;
     RECT  2.16 86.805 15.12 87.075 ;
     RECT  2.16 87.345 15.12 87.615 ;
     RECT  2.16 87.885 15.12 88.155 ;
     RECT  2.16 88.425 15.12 88.695 ;
     RECT  2.16 88.965 15.12 89.235 ;
     RECT  2.16 89.505 15.12 89.775 ;
     RECT  2.16 90.045 15.12 90.315 ;
     RECT  2.16 90.585 15.12 90.855 ;
     RECT  2.16 91.125 15.12 91.395 ;
     RECT  2.16 91.665 15.12 91.935 ;
     RECT  2.16 92.205 15.12 92.475 ;
     RECT  2.16 92.745 15.12 93.015 ;
     RECT  2.16 93.285 15.12 93.555 ;
     RECT  2.16 93.825 15.12 94.095 ;
     RECT  2.16 94.365 15.12 94.635 ;
     RECT  2.16 94.905 15.12 95.04 ;
    LAYER RVTP ;
     RECT  2.16 2.295 15.12 2.565 ;
     RECT  2.16 2.835 15.12 3.105 ;
     RECT  2.16 3.375 15.12 3.645 ;
     RECT  2.16 3.915 15.12 4.185 ;
     RECT  2.16 4.455 15.12 4.725 ;
     RECT  2.16 4.995 15.12 5.265 ;
     RECT  2.16 5.535 15.12 5.805 ;
     RECT  2.16 6.075 15.12 6.345 ;
     RECT  2.16 6.615 15.12 6.885 ;
     RECT  2.16 7.155 15.12 7.425 ;
     RECT  2.16 7.695 15.12 7.965 ;
     RECT  2.16 8.235 15.12 8.505 ;
     RECT  2.16 8.775 15.12 9.045 ;
     RECT  2.16 9.315 15.12 9.585 ;
     RECT  2.16 9.855 15.12 10.125 ;
     RECT  2.16 10.395 15.12 10.665 ;
     RECT  2.16 10.935 15.12 11.205 ;
     RECT  2.16 11.475 15.12 11.745 ;
     RECT  2.16 12.015 15.12 12.285 ;
     RECT  2.16 12.555 15.12 12.825 ;
     RECT  2.16 13.095 15.12 13.365 ;
     RECT  2.16 13.635 15.12 13.905 ;
     RECT  2.16 14.175 15.12 14.445 ;
     RECT  2.16 14.715 15.12 14.985 ;
     RECT  2.16 15.255 15.12 15.525 ;
     RECT  2.16 15.795 15.12 16.065 ;
     RECT  2.16 16.335 15.12 16.605 ;
     RECT  2.16 16.875 15.12 17.145 ;
     RECT  2.16 17.415 15.12 17.685 ;
     RECT  2.16 17.955 15.12 18.225 ;
     RECT  2.16 18.495 15.12 18.765 ;
     RECT  2.16 19.035 15.12 19.305 ;
     RECT  2.16 19.575 15.12 19.845 ;
     RECT  2.16 20.115 15.12 20.385 ;
     RECT  2.16 20.655 15.12 20.925 ;
     RECT  2.16 21.195 15.12 21.465 ;
     RECT  2.16 21.735 15.12 22.005 ;
     RECT  2.16 22.275 15.12 22.545 ;
     RECT  2.16 22.815 15.12 23.085 ;
     RECT  2.16 23.355 15.12 23.625 ;
     RECT  2.16 23.895 15.12 24.165 ;
     RECT  2.16 24.435 15.12 24.705 ;
     RECT  2.16 24.975 15.12 25.245 ;
     RECT  2.16 25.515 15.12 25.785 ;
     RECT  2.16 26.055 15.12 26.325 ;
     RECT  2.16 26.595 15.12 26.865 ;
     RECT  2.16 27.135 15.12 27.405 ;
     RECT  2.16 27.675 15.12 27.945 ;
     RECT  2.16 28.215 15.12 28.485 ;
     RECT  2.16 28.755 15.12 29.025 ;
     RECT  2.16 29.295 15.12 29.565 ;
     RECT  2.16 29.835 15.12 30.105 ;
     RECT  2.16 30.375 15.12 30.645 ;
     RECT  2.16 30.915 15.12 31.185 ;
     RECT  2.16 31.455 15.12 31.725 ;
     RECT  2.16 31.995 15.12 32.265 ;
     RECT  2.16 32.535 15.12 32.805 ;
     RECT  2.16 33.075 15.12 33.345 ;
     RECT  2.16 33.615 15.12 33.885 ;
     RECT  2.16 34.155 15.12 34.425 ;
     RECT  2.16 34.695 15.12 34.965 ;
     RECT  2.16 35.235 15.12 35.505 ;
     RECT  2.16 35.775 15.12 36.045 ;
     RECT  2.16 36.315 15.12 36.585 ;
     RECT  2.16 36.855 15.12 37.125 ;
     RECT  2.16 37.395 15.12 37.665 ;
     RECT  2.16 37.935 15.12 38.205 ;
     RECT  2.16 38.475 15.12 38.745 ;
     RECT  2.16 39.015 15.12 39.285 ;
     RECT  2.16 39.555 15.12 39.825 ;
     RECT  2.16 40.095 15.12 40.365 ;
     RECT  2.16 40.635 15.12 40.905 ;
     RECT  2.16 41.175 15.12 41.445 ;
     RECT  2.16 41.715 15.12 41.985 ;
     RECT  2.16 42.255 15.12 42.525 ;
     RECT  2.16 42.795 15.12 43.065 ;
     RECT  2.16 43.335 15.12 43.605 ;
     RECT  2.16 43.875 15.12 44.145 ;
     RECT  2.16 44.415 15.12 44.685 ;
     RECT  2.16 44.955 15.12 45.225 ;
     RECT  2.16 45.495 15.12 45.765 ;
     RECT  2.16 46.035 15.12 46.305 ;
     RECT  2.16 46.575 15.12 46.845 ;
     RECT  2.16 47.115 15.12 47.385 ;
     RECT  2.16 47.655 15.12 47.925 ;
     RECT  2.16 48.195 15.12 48.465 ;
     RECT  2.16 48.735 15.12 49.005 ;
     RECT  2.16 49.275 15.12 49.545 ;
     RECT  2.16 49.815 15.12 50.085 ;
     RECT  2.16 50.355 15.12 50.625 ;
     RECT  2.16 50.895 15.12 51.165 ;
     RECT  2.16 51.435 15.12 51.705 ;
     RECT  2.16 51.975 15.12 52.245 ;
     RECT  2.16 52.515 15.12 52.785 ;
     RECT  2.16 53.055 15.12 53.325 ;
     RECT  2.16 53.595 15.12 53.865 ;
     RECT  2.16 54.135 15.12 54.405 ;
     RECT  2.16 54.675 15.12 54.945 ;
     RECT  2.16 55.215 15.12 55.485 ;
     RECT  2.16 55.755 15.12 56.025 ;
     RECT  2.16 56.295 15.12 56.565 ;
     RECT  2.16 56.835 15.12 57.105 ;
     RECT  2.16 57.375 15.12 57.645 ;
     RECT  2.16 57.915 15.12 58.185 ;
     RECT  2.16 58.455 15.12 58.725 ;
     RECT  2.16 58.995 15.12 59.265 ;
     RECT  2.16 59.535 15.12 59.805 ;
     RECT  2.16 60.075 15.12 60.345 ;
     RECT  2.16 60.615 15.12 60.885 ;
     RECT  2.16 61.155 15.12 61.425 ;
     RECT  2.16 61.695 15.12 61.965 ;
     RECT  2.16 62.235 15.12 62.505 ;
     RECT  2.16 62.775 15.12 63.045 ;
     RECT  2.16 63.315 15.12 63.585 ;
     RECT  2.16 63.855 15.12 64.125 ;
     RECT  2.16 64.395 15.12 64.665 ;
     RECT  2.16 64.935 15.12 65.205 ;
     RECT  2.16 65.475 15.12 65.745 ;
     RECT  2.16 66.015 15.12 66.285 ;
     RECT  2.16 66.555 15.12 66.825 ;
     RECT  2.16 67.095 15.12 67.365 ;
     RECT  2.16 67.635 15.12 67.905 ;
     RECT  2.16 68.175 15.12 68.445 ;
     RECT  2.16 68.715 15.12 68.985 ;
     RECT  2.16 69.255 15.12 69.525 ;
     RECT  2.16 69.795 15.12 70.065 ;
     RECT  2.16 70.335 15.12 70.605 ;
     RECT  2.16 70.875 15.12 71.145 ;
     RECT  2.16 71.415 15.12 71.685 ;
     RECT  2.16 71.955 15.12 72.225 ;
     RECT  2.16 72.495 15.12 72.765 ;
     RECT  2.16 73.035 15.12 73.305 ;
     RECT  2.16 73.575 15.12 73.845 ;
     RECT  2.16 74.115 15.12 74.385 ;
     RECT  2.16 74.655 15.12 74.925 ;
     RECT  2.16 75.195 15.12 75.465 ;
     RECT  2.16 75.735 15.12 76.005 ;
     RECT  2.16 76.275 15.12 76.545 ;
     RECT  2.16 76.815 15.12 77.085 ;
     RECT  2.16 77.355 15.12 77.625 ;
     RECT  2.16 77.895 15.12 78.165 ;
     RECT  2.16 78.435 15.12 78.705 ;
     RECT  2.16 78.975 15.12 79.245 ;
     RECT  2.16 79.515 15.12 79.785 ;
     RECT  2.16 80.055 15.12 80.325 ;
     RECT  2.16 80.595 15.12 80.865 ;
     RECT  2.16 81.135 15.12 81.405 ;
     RECT  2.16 81.675 15.12 81.945 ;
     RECT  2.16 82.215 15.12 82.485 ;
     RECT  2.16 82.755 15.12 83.025 ;
     RECT  2.16 83.295 15.12 83.565 ;
     RECT  2.16 83.835 15.12 84.105 ;
     RECT  2.16 84.375 15.12 84.645 ;
     RECT  2.16 84.915 15.12 85.185 ;
     RECT  2.16 85.455 15.12 85.725 ;
     RECT  2.16 85.995 15.12 86.265 ;
     RECT  2.16 86.535 15.12 86.805 ;
     RECT  2.16 87.075 15.12 87.345 ;
     RECT  2.16 87.615 15.12 87.885 ;
     RECT  2.16 88.155 15.12 88.425 ;
     RECT  2.16 88.695 15.12 88.965 ;
     RECT  2.16 89.235 15.12 89.505 ;
     RECT  2.16 89.775 15.12 90.045 ;
     RECT  2.16 90.315 15.12 90.585 ;
     RECT  2.16 90.855 15.12 91.125 ;
     RECT  2.16 91.395 15.12 91.665 ;
     RECT  2.16 91.935 15.12 92.205 ;
     RECT  2.16 92.475 15.12 92.745 ;
     RECT  2.16 93.015 15.12 93.285 ;
     RECT  2.16 93.555 15.12 93.825 ;
     RECT  2.16 94.095 15.12 94.365 ;
     RECT  2.16 94.635 15.12 94.905 ;
    LAYER M1 ;
     RECT  2.16 2.151 15.12 95.049 ;
    LAYER M2 ;
     RECT  0.031 77.634 0.067 77.652 ;
     RECT  0.031 15.156 0.103 15.174 ;
     RECT  0.031 20.664 0.103 20.682 ;
     RECT  0.031 40.536 0.103 40.554 ;
     RECT  0.031 60.318 0.103 60.336 ;
     RECT  0.031 63.396 0.103 63.414 ;
     RECT  0.103 47.286 0.139 47.304 ;
     RECT  0.103 48.474 0.139 49.104 ;
     RECT  0.067 77.058 0.139 77.652 ;
     RECT  0.103 23.328 0.175 23.886 ;
     RECT  0.103 25.146 0.175 25.164 ;
     RECT  0.103 28.386 0.175 28.404 ;
     RECT  0.031 37.674 0.175 37.692 ;
     RECT  0.103 41.526 0.175 41.544 ;
     RECT  0.139 46.161 0.175 46.179 ;
     RECT  0.103 63.054 0.175 63.414 ;
     RECT  0.103 65.718 0.175 66.474 ;
     RECT  0.103 31.896 0.203 36.108 ;
     RECT  0.103 43.92 0.203 43.938 ;
     RECT  0.103 44.694 0.203 44.712 ;
     RECT  0.175 65.448 0.203 66.474 ;
     RECT  0.103 68.76 0.203 68.976 ;
     RECT  0.067 73.782 0.203 73.8 ;
     RECT  0.103 60.318 0.211 61.074 ;
     RECT  0.175 62.676 0.211 63.414 ;
     RECT  0.103 64.296 0.211 64.314 ;
     RECT  0.203 65.448 0.211 65.466 ;
     RECT  0.103 21.906 0.247 21.924 ;
     RECT  0.175 23.13 0.247 23.886 ;
     RECT  0.211 26.766 0.247 26.784 ;
     RECT  0.103 39.834 0.247 40.554 ;
     RECT  0.175 41.418 0.247 41.544 ;
     RECT  0.175 46.008 0.247 46.179 ;
     RECT  0.211 60.318 0.247 61.614 ;
     RECT  0.103 29.466 0.275 31.14 ;
     RECT  0.203 35.208 0.275 35.298 ;
     RECT  0.211 62.676 0.275 65.466 ;
     RECT  0.175 25.146 0.283 25.308 ;
     RECT  0.247 26.136 0.283 26.784 ;
     RECT  0.275 35.208 0.311 35.226 ;
     RECT  0.275 62.676 0.311 65.034 ;
     RECT  0.247 45.936 0.347 46.179 ;
     RECT  0.103 69.84 0.347 69.858 ;
     RECT  0.103 71.46 0.347 71.478 ;
     RECT  0.103 72.234 0.347 72.252 ;
     RECT  0.319 38.826 0.419 38.844 ;
     RECT  0.103 20.664 0.427 21.024 ;
     RECT  0.247 21.906 0.427 23.886 ;
     RECT  0.247 39.834 0.427 41.544 ;
     RECT  0.103 42.651 0.427 43.164 ;
     RECT  0.283 25.146 0.463 26.784 ;
     RECT  0.139 47.286 0.463 49.104 ;
     RECT  0.427 20.664 0.499 23.886 ;
     RECT  0.463 24.948 0.499 26.784 ;
     RECT  0.247 60.318 0.499 61.65 ;
     RECT  0.311 62.676 0.499 64.314 ;
     RECT  0.499 20.088 0.535 24.156 ;
     RECT  0.499 24.948 0.535 27.198 ;
     RECT  0.499 38.988 0.535 39.006 ;
     RECT  0.427 39.834 0.535 43.164 ;
     RECT  0.463 47.286 0.535 49.149 ;
     RECT  0.103 67.491 0.535 67.824 ;
     RECT  0.139 76.986 0.823 77.652 ;
     RECT  0.535 47.124 1.139 49.149 ;
     RECT  0.499 60.318 1.147 64.314 ;
     RECT  0.571 74.358 1.147 74.376 ;
     RECT  0.535 20.088 1.175 27.198 ;
     RECT  1.147 74.358 1.183 75.114 ;
     RECT  1.183 74.196 1.211 75.114 ;
     RECT  0.535 38.988 1.219 43.434 ;
     RECT  1.211 75.096 1.219 75.114 ;
     RECT  0.067 16.344 1.399 16.362 ;
     RECT  0.535 52.218 1.399 52.236 ;
     RECT  1.399 16.344 1.507 16.794 ;
     RECT  1.507 16.344 1.687 16.83 ;
     RECT  0.535 71.226 1.723 71.244 ;
     RECT  1.723 71.226 1.759 71.406 ;
     RECT  0.823 76.986 1.975 77.85 ;
     RECT  1.759 71.226 2.011 72.054 ;
     RECT  1.975 76.986 2.011 78.264 ;
     RECT  1.687 16.344 2.047 17.244 ;
     RECT  2.011 71.226 2.083 72.324 ;
     RECT  1.723 57.276 2.119 57.294 ;
     RECT  2.083 71.226 2.119 72.414 ;
     RECT  1.211 74.196 2.119 74.214 ;
     RECT  2.047 16.308 2.155 17.244 ;
     RECT  2.083 10.71 2.16 10.728 ;
     RECT  0.103 14.958 2.16 15.174 ;
     RECT  2.155 15.966 2.16 17.334 ;
     RECT  1.651 18.396 2.16 18.414 ;
     RECT  1.175 20.088 2.16 27.09 ;
     RECT  0.175 28.296 2.16 28.404 ;
     RECT  0.275 29.466 2.16 31.104 ;
     RECT  0.203 31.896 2.16 34.146 ;
     RECT  0.175 37.026 2.16 37.692 ;
     RECT  1.219 38.556 2.16 43.434 ;
     RECT  0.347 45.936 2.16 46.026 ;
     RECT  1.139 47.124 2.16 49.104 ;
     RECT  1.399 52.056 2.16 52.236 ;
     RECT  0.103 52.992 2.16 53.01 ;
     RECT  1.975 54.306 2.16 54.324 ;
     RECT  2.155 56.196 2.16 56.214 ;
     RECT  2.119 57.078 2.16 57.294 ;
     RECT  1.759 58.158 2.16 58.176 ;
     RECT  1.147 59.85 2.16 64.314 ;
     RECT  0.203 66.456 2.16 66.474 ;
     RECT  0.535 67.374 2.16 67.824 ;
     RECT  2.119 70.65 2.16 72.414 ;
     RECT  2.119 74.088 2.16 74.214 ;
     RECT  1.219 75.096 2.16 75.384 ;
     RECT  2.011 76.986 2.16 78.534 ;
     RECT  2.16 2.151 15.12 95.049 ;
     RECT  15.12 27.144 15.215 66.312 ;
     RECT  15.12 9.09 15.251 9.648 ;
     RECT  15.251 9.63 15.287 9.648 ;
     RECT  15.215 52.56 15.287 66.312 ;
     RECT  15.12 10.638 15.323 11.304 ;
     RECT  15.323 11.286 15.359 11.304 ;
     RECT  15.287 52.56 15.359 59.364 ;
     RECT  15.215 27.144 15.395 51.768 ;
     RECT  15.395 27.144 15.431 46.836 ;
     RECT  15.359 53.1 15.503 59.364 ;
     RECT  15.12 13.914 15.683 26.388 ;
     RECT  15.683 13.914 15.755 23.31 ;
     RECT  15.287 60.12 15.755 66.312 ;
     RECT  15.755 15.3 15.827 23.31 ;
     RECT  15.12 67.608 15.827 80.118 ;
     RECT  15.12 80.874 15.827 82.782 ;
     RECT  15.827 73.116 15.863 80.118 ;
     RECT  15.827 81.18 15.863 82.782 ;
     RECT  15.755 60.12 15.899 63.648 ;
     RECT  15.431 29.538 15.935 46.836 ;
     RECT  15.395 47.736 15.935 51.768 ;
     RECT  15.755 64.674 15.935 66.312 ;
     RECT  15.827 67.608 15.935 72.288 ;
     RECT  15.863 73.926 15.935 80.118 ;
     RECT  15.935 29.538 15.971 39.924 ;
     RECT  15.935 41.184 15.971 46.404 ;
     RECT  15.935 47.736 15.971 49.104 ;
     RECT  15.935 49.86 15.971 51.768 ;
     RECT  15.503 53.1 15.971 57.672 ;
     RECT  15.935 67.95 15.971 72.288 ;
     RECT  15.863 81.18 15.971 81.936 ;
     RECT  15.827 15.534 16.007 20.754 ;
     RECT  15.683 24.408 16.007 26.388 ;
     RECT  15.431 27.144 16.007 28.782 ;
     RECT  15.971 33.858 16.007 39.924 ;
     RECT  15.899 60.39 16.007 63.648 ;
     RECT  15.971 68.382 16.007 69.354 ;
     RECT  16.007 24.408 16.043 25.848 ;
     RECT  16.007 27.144 16.043 28.476 ;
     RECT  15.971 29.538 16.043 33.102 ;
     RECT  16.007 33.858 16.043 38.736 ;
     RECT  15.971 41.688 16.043 46.404 ;
     RECT  16.043 31.968 16.079 32.292 ;
     RECT  16.043 33.084 16.079 33.102 ;
     RECT  16.043 33.858 16.079 35.604 ;
     RECT  16.043 36.36 16.079 38.538 ;
     RECT  15.971 70.146 16.079 72.288 ;
     RECT  16.043 24.678 16.115 25.848 ;
     RECT  16.043 29.538 16.115 31.212 ;
     RECT  16.079 36.36 16.115 38.124 ;
     RECT  16.115 36.558 16.151 38.124 ;
     RECT  15.971 57.078 16.151 57.672 ;
     RECT  15.503 58.536 16.187 59.364 ;
     RECT  16.007 15.57 16.223 20.754 ;
     RECT  16.007 60.39 16.223 63.27 ;
     RECT  16.223 15.651 16.259 20.754 ;
     RECT  16.115 29.88 16.259 31.212 ;
     RECT  16.043 41.688 16.259 44.784 ;
     RECT  15.935 64.674 16.259 64.998 ;
     RECT  15.755 13.914 16.295 14.508 ;
     RECT  16.259 29.88 16.295 29.898 ;
     RECT  15.971 48.24 16.295 49.104 ;
     RECT  15.863 73.116 16.295 73.134 ;
     RECT  15.971 81.18 16.295 81.468 ;
     RECT  16.187 58.536 16.303 58.95 ;
     RECT  16.115 24.678 16.331 25.542 ;
     RECT  16.151 57.078 16.331 57.096 ;
     RECT  16.259 64.872 16.331 64.998 ;
     RECT  15.863 82.764 16.331 82.782 ;
     RECT  16.259 30.888 16.367 31.212 ;
     RECT  16.223 61.668 16.367 63.27 ;
     RECT  16.259 15.651 16.403 20.718 ;
     RECT  15.827 21.708 16.403 23.31 ;
     RECT  16.403 16.038 16.439 20.718 ;
     RECT  16.043 27.144 16.439 27.819 ;
     RECT  15.971 54.72 16.439 56.124 ;
     RECT  16.367 61.668 16.439 62.802 ;
     RECT  15.935 73.926 16.439 79.884 ;
     RECT  16.331 24.678 16.475 25.506 ;
     RECT  16.295 49.086 16.475 49.104 ;
     RECT  16.439 61.668 16.475 62.109 ;
     RECT  16.295 81.45 16.475 81.468 ;
     RECT  16.439 16.038 16.511 18.018 ;
     RECT  16.403 22.896 16.511 23.31 ;
     RECT  16.475 24.678 16.511 24.768 ;
     RECT  16.151 36.594 16.511 38.124 ;
     RECT  15.971 50.094 16.511 51.768 ;
     RECT  15.971 53.1 16.511 53.964 ;
     RECT  16.439 54.72 16.511 55.008 ;
     RECT  15.935 65.754 16.511 66.312 ;
     RECT  16.079 70.146 16.511 72.216 ;
     RECT  16.439 79.452 16.511 79.884 ;
     RECT  16.079 31.968 16.547 32.058 ;
     RECT  16.511 36.594 16.547 36.612 ;
     RECT  16.259 41.688 16.547 43.974 ;
     RECT  16.303 58.122 16.547 58.95 ;
     RECT  16.367 30.888 16.583 30.906 ;
     RECT  16.439 18.81 16.619 20.718 ;
     RECT  16.511 23.058 16.619 23.31 ;
     RECT  16.547 31.968 16.619 32.022 ;
     RECT  16.619 23.058 16.655 23.076 ;
     RECT  16.511 16.038 16.907 17.982 ;
     RECT  16.439 73.926 16.907 77.076 ;
     RECT  16.907 16.038 16.943 17.478 ;
     RECT  16.907 73.926 16.979 76.068 ;
     RECT  16.619 19.818 17.015 20.718 ;
     RECT  16.439 55.764 17.015 56.124 ;
     RECT  16.439 27.648 17.023 27.819 ;
     RECT  16.511 53.946 17.023 53.964 ;
     RECT  16.511 54.72 17.023 54.738 ;
     RECT  16.943 16.038 17.051 17.1 ;
     RECT  16.979 73.926 17.051 75.798 ;
     RECT  17.015 20.088 17.087 20.718 ;
     RECT  17.023 27.648 17.087 28.476 ;
     RECT  16.511 50.67 17.087 51.768 ;
     RECT  16.511 53.1 17.087 53.118 ;
     RECT  17.015 55.764 17.087 55.782 ;
     RECT  16.223 60.39 17.087 60.714 ;
     RECT  17.051 73.926 17.087 75.492 ;
     RECT  16.259 44.766 17.095 44.784 ;
     RECT  16.043 45.54 17.095 46.404 ;
     RECT  16.007 68.994 17.095 69.354 ;
     RECT  16.511 70.146 17.095 71.676 ;
     RECT  17.051 16.038 17.123 16.938 ;
     RECT  16.511 24.678 17.123 24.696 ;
     RECT  17.087 27.72 17.123 28.476 ;
     RECT  16.547 41.688 17.123 42.588 ;
     RECT  17.023 53.946 17.123 54.738 ;
     RECT  16.547 58.626 17.123 58.95 ;
     RECT  17.095 68.994 17.123 71.676 ;
     RECT  16.439 78.174 17.123 78.66 ;
     RECT  16.511 79.452 17.123 79.74 ;
     RECT  16.331 64.98 17.131 64.998 ;
     RECT  17.123 16.038 17.159 16.596 ;
     RECT  16.619 18.81 17.159 18.909 ;
     RECT  16.079 33.858 17.159 34.992 ;
     RECT  17.123 41.688 17.159 41.778 ;
     RECT  16.547 43.416 17.159 43.974 ;
     RECT  17.095 44.766 17.159 46.404 ;
     RECT  17.087 51.21 17.159 51.768 ;
     RECT  17.123 53.946 17.159 54.666 ;
     RECT  17.087 60.624 17.159 60.714 ;
     RECT  17.123 70.038 17.159 71.604 ;
     RECT  17.087 73.926 17.159 75.024 ;
     RECT  17.123 78.516 17.159 78.66 ;
     RECT  16.619 31.968 17.167 31.986 ;
     RECT  16.007 39.906 17.167 39.924 ;
     RECT  16.295 14.418 17.195 14.508 ;
     RECT  16.403 21.708 17.195 22.104 ;
     RECT  17.123 27.72 17.195 27.819 ;
     RECT  17.159 34.2 17.195 34.992 ;
     RECT  17.167 39.906 17.195 40.014 ;
     RECT  17.159 41.76 17.195 41.778 ;
     RECT  17.123 42.57 17.195 42.588 ;
     RECT  17.159 43.956 17.195 43.974 ;
     RECT  17.159 44.766 17.195 44.829 ;
     RECT  17.159 46.044 17.195 46.062 ;
     RECT  17.159 51.21 17.195 51.534 ;
     RECT  17.159 53.946 17.195 54.594 ;
     RECT  17.123 58.626 17.195 58.824 ;
     RECT  17.131 64.98 17.195 65.349 ;
     RECT  16.511 66.294 17.195 66.312 ;
     RECT  17.159 70.038 17.195 70.56 ;
     RECT  17.159 74.628 17.195 75.024 ;
     RECT  16.907 77.058 17.195 77.076 ;
     RECT  17.159 78.642 17.195 78.66 ;
     RECT  17.123 79.722 17.195 79.74 ;
     RECT  17.159 16.578 17.231 16.596 ;
     RECT  17.159 18.891 17.231 18.909 ;
     RECT  17.167 31.896 17.231 31.986 ;
     RECT  17.195 34.866 17.231 34.884 ;
     RECT  17.131 49.131 17.231 49.149 ;
     RECT  17.195 51.21 17.231 51.228 ;
     RECT  17.195 58.626 17.231 58.644 ;
     RECT  16.475 62.091 17.231 62.109 ;
     RECT  17.195 70.038 17.231 70.479 ;
     RECT  17.159 71.496 17.231 71.514 ;
     RECT  17.195 14.418 17.267 14.436 ;
     RECT  17.167 20.781 17.267 20.799 ;
     RECT  17.195 21.708 17.267 21.726 ;
     RECT  17.167 25.866 17.267 25.884 ;
     RECT  17.195 27.801 17.267 27.819 ;
     RECT  17.231 31.896 17.267 31.914 ;
     RECT  16.511 38.106 17.267 38.124 ;
     RECT  17.195 39.996 17.267 40.014 ;
     RECT  17.195 44.811 17.267 44.829 ;
     RECT  16.295 48.24 17.267 48.258 ;
     RECT  17.195 53.991 17.267 54.009 ;
     RECT  17.159 60.624 17.267 60.642 ;
     RECT  17.195 65.331 17.267 65.349 ;
     RECT  17.123 68.994 17.267 69.012 ;
     RECT  17.231 70.038 17.267 70.056 ;
     RECT  17.195 75.006 17.267 75.024 ;
    LAYER M3 ;
     RECT  4.5 1.723 4.518 2.255 ;
     RECT  2.415 2.143 2.505 2.413 ;
     RECT  7.815 2.143 7.905 2.413 ;
     RECT  13.215 2.143 13.305 2.413 ;
     RECT  4.932 2.371 4.95 2.525 ;
     RECT  5.148 2.641 5.166 5.495 ;
     RECT  5.4 5.611 5.418 6.547 ;
     RECT  6.48 5.467 6.498 6.547 ;
     RECT  5.4 6.547 6.498 6.691 ;
     RECT  7.815 2.413 8.097 6.691 ;
     RECT  5.4 6.691 8.097 7.189 ;
     RECT  4.788 7.189 8.097 7.231 ;
     RECT  4.032 7.195 4.05 7.385 ;
     RECT  9.792 7.387 9.81 7.501 ;
     RECT  4.788 7.231 8.514 7.591 ;
     RECT  4.788 7.591 8.766 7.699 ;
     RECT  9.792 7.501 10.422 7.699 ;
     RECT  12.456 7.735 12.474 7.771 ;
     RECT  13.215 2.413 13.497 7.771 ;
     RECT  12.456 7.771 13.497 7.897 ;
     RECT  4.608 7.699 8.766 7.925 ;
     RECT  9.792 7.699 10.926 7.997 ;
     RECT  4.68 7.925 8.766 8.203 ;
     RECT  4.68 8.203 9.054 8.339 ;
     RECT  12.276 7.897 13.497 8.401 ;
     RECT  12.276 8.401 13.842 8.437 ;
     RECT  4.68 8.339 8.838 8.699 ;
     RECT  10.008 7.997 10.926 8.699 ;
     RECT  10.08 8.699 10.926 8.779 ;
     RECT  12.24 8.437 13.842 8.779 ;
     RECT  3.78 7.591 3.798 9.085 ;
     RECT  14.652 9.013 14.67 9.085 ;
     RECT  4.68 8.699 5.49 9.121 ;
     RECT  6.228 8.699 8.838 9.319 ;
     RECT  10.08 8.779 13.842 9.355 ;
     RECT  14.58 9.085 15.246 9.355 ;
     RECT  6.228 9.319 9.162 9.481 ;
     RECT  10.08 9.355 15.246 9.481 ;
     RECT  6.228 9.481 15.246 9.625 ;
     RECT  4.572 9.121 5.49 9.751 ;
     RECT  6.228 9.625 15.282 9.751 ;
     RECT  3.42 9.085 3.798 9.931 ;
     RECT  4.572 9.751 15.282 9.931 ;
     RECT  3.42 9.931 15.282 10.193 ;
     RECT  9.144 10.193 15.282 10.499 ;
     RECT  3.42 10.193 8.154 10.589 ;
     RECT  9.324 10.499 15.282 10.633 ;
     RECT  2.415 2.413 2.697 10.705 ;
     RECT  2.088 10.705 2.697 11.209 ;
     RECT  3.42 10.589 8.097 11.209 ;
     RECT  9.324 10.633 15.318 11.281 ;
     RECT  2.088 11.209 8.097 11.371 ;
     RECT  8.928 11.281 15.354 11.371 ;
     RECT  2.088 11.371 15.354 11.975 ;
     RECT  2.088 11.975 11.322 12.083 ;
     RECT  2.088 12.083 11.178 13.063 ;
     RECT  12.096 11.975 15.354 13.063 ;
     RECT  17.244 14.413 17.262 14.485 ;
     RECT  2.088 13.063 15.354 14.755 ;
     RECT  16.272 13.909 16.29 14.755 ;
     RECT  0.108 14.953 0.126 15.151 ;
     RECT  2.088 14.755 16.29 15.646 ;
     RECT  17.172 14.485 17.262 16.033 ;
     RECT  2.088 15.646 16.398 16.303 ;
     RECT  2.052 16.303 16.398 16.339 ;
     RECT  17.136 16.033 17.262 16.339 ;
     RECT  2.052 16.339 17.262 16.501 ;
     RECT  2.016 16.501 17.262 16.771 ;
     RECT  0.036 15.151 0.126 20.083 ;
     RECT  1.404 16.771 17.262 20.489 ;
     RECT  0.036 20.083 0.522 20.551 ;
     RECT  1.404 20.489 9.774 20.551 ;
     RECT  0.036 20.551 9.774 20.687 ;
     RECT  11.484 20.489 17.262 20.804 ;
     RECT  11.484 20.804 17.19 20.813 ;
     RECT  0.108 20.687 9.774 21.029 ;
     RECT  1.512 21.029 9.774 21.101 ;
     RECT  1.656 21.101 9.774 21.235 ;
     RECT  10.512 20.489 10.566 21.235 ;
     RECT  1.656 21.235 10.566 21.271 ;
     RECT  11.484 20.813 17.154 21.271 ;
     RECT  1.656 21.271 17.154 21.703 ;
     RECT  0.108 21.029 0.558 21.787 ;
     RECT  0.108 21.787 0.594 21.839 ;
     RECT  0.108 21.839 0.522 21.869 ;
     RECT  1.656 21.703 17.262 21.965 ;
     RECT  1.656 21.965 10.638 22.081 ;
     RECT  0.108 21.869 0.486 22.621 ;
     RECT  1.44 22.081 10.638 22.885 ;
     RECT  11.484 21.965 17.262 22.885 ;
     RECT  1.44 22.885 17.262 23.981 ;
     RECT  0.108 22.621 0.558 24.077 ;
     RECT  1.512 23.981 17.262 24.395 ;
     RECT  1.512 24.395 11.394 24.557 ;
     RECT  0.504 24.077 0.558 24.943 ;
     RECT  0.468 24.943 0.558 25.099 ;
     RECT  0.144 25.099 0.558 25.141 ;
     RECT  0.108 25.141 0.558 25.213 ;
     RECT  0.108 25.213 1.17 25.313 ;
     RECT  2.052 24.557 11.394 25.321 ;
     RECT  12.132 24.395 17.262 25.321 ;
     RECT  2.052 25.321 17.262 25.889 ;
     RECT  2.052 25.889 17.19 25.901 ;
     RECT  2.052 25.901 17.118 26.237 ;
     RECT  0.108 25.313 0.558 26.381 ;
     RECT  0.144 26.381 0.558 27.067 ;
     RECT  2.052 26.237 11.286 27.067 ;
     RECT  12.168 26.237 17.118 27.067 ;
     RECT  0.144 27.067 1.17 27.203 ;
     RECT  0.144 27.203 0.558 27.341 ;
     RECT  2.052 27.067 17.118 27.715 ;
     RECT  2.052 27.715 17.19 27.796 ;
     RECT  0.504 27.341 0.558 28.109 ;
     RECT  0.18 28.291 0.342 28.381 ;
     RECT  1.152 28.219 1.278 28.445 ;
     RECT  0.108 28.381 0.342 28.493 ;
     RECT  1.26 28.445 1.278 28.493 ;
     RECT  0.108 28.493 0.198 28.589 ;
     RECT  0.18 28.589 0.198 28.973 ;
     RECT  0.144 29.419 0.162 29.461 ;
     RECT  2.052 27.796 17.262 29.525 ;
     RECT  0.108 29.461 0.162 30.001 ;
     RECT  0.108 30.001 0.27 30.073 ;
     RECT  0.108 30.073 0.342 30.181 ;
     RECT  2.052 29.525 9.81 30.299 ;
     RECT  0.108 30.181 0.558 30.317 ;
     RECT  2.376 30.299 9.81 30.343 ;
     RECT  10.764 29.525 17.262 30.343 ;
     RECT  0.108 30.317 0.342 31.051 ;
     RECT  0.108 31.051 0.378 31.181 ;
     RECT  2.376 30.343 17.262 31.243 ;
     RECT  2.304 31.243 17.262 31.919 ;
     RECT  2.304 31.919 17.226 32.395 ;
     RECT  2.268 32.395 17.226 32.567 ;
     RECT  0.108 31.181 0.342 32.809 ;
     RECT  2.304 32.567 17.226 33.377 ;
     RECT  2.304 33.377 9.558 34.027 ;
     RECT  2.268 34.027 9.558 34.115 ;
     RECT  2.304 34.115 9.558 34.231 ;
     RECT  10.296 33.377 17.226 34.231 ;
     RECT  0.108 32.809 0.558 34.253 ;
     RECT  2.304 34.231 17.226 34.763 ;
     RECT  11.628 34.763 17.226 34.889 ;
     RECT  11.628 34.889 17.19 34.997 ;
     RECT  0.108 34.253 0.342 35.213 ;
     RECT  2.304 34.763 10.89 35.851 ;
     RECT  11.628 34.997 17.154 35.851 ;
     RECT  2.304 35.851 17.154 36.077 ;
     RECT  0.108 35.213 0.306 36.113 ;
     RECT  2.304 36.077 17.082 36.113 ;
     RECT  15.768 36.113 17.082 36.173 ;
     RECT  15.768 36.173 16.542 36.269 ;
     RECT  1.224 36.331 1.35 36.461 ;
     RECT  15.984 36.269 16.542 36.749 ;
     RECT  2.304 36.113 14.814 36.763 ;
     RECT  2.232 36.763 14.814 36.851 ;
     RECT  0.324 36.139 0.342 36.859 ;
     RECT  0.216 36.859 0.342 37.003 ;
     RECT  15.984 36.749 16.506 37.003 ;
     RECT  2.304 36.851 14.814 37.049 ;
     RECT  12.132 37.049 14.814 37.093 ;
     RECT  15.948 37.003 16.506 37.093 ;
     RECT  2.304 37.049 11.286 37.157 ;
     RECT  12.132 37.093 16.506 37.373 ;
     RECT  0.18 37.003 0.342 37.613 ;
     RECT  2.304 37.157 11.25 37.625 ;
     RECT  2.304 37.625 9.342 37.697 ;
     RECT  12.24 37.373 16.506 37.805 ;
     RECT  2.304 37.697 9.306 37.859 ;
     RECT  2.304 37.859 9.234 37.895 ;
     RECT  10.62 37.625 11.25 38.003 ;
     RECT  10.836 38.003 11.25 38.101 ;
     RECT  12.24 37.805 16.074 38.101 ;
     RECT  1.224 36.461 1.242 38.579 ;
     RECT  0.036 37.669 0.162 38.635 ;
     RECT  2.304 37.895 9.198 38.677 ;
     RECT  0.036 38.635 0.342 38.779 ;
     RECT  10.836 38.101 16.074 38.785 ;
     RECT  10.548 38.785 16.074 38.821 ;
     RECT  2.304 38.677 9.45 38.939 ;
     RECT  0.036 38.779 0.414 38.983 ;
     RECT  10.296 38.821 16.074 38.983 ;
     RECT  10.224 38.983 16.074 39.217 ;
     RECT  10.116 39.217 16.074 39.341 ;
     RECT  10.116 39.341 16.038 39.437 ;
     RECT  10.116 39.437 16.002 39.757 ;
     RECT  17.244 38.101 17.262 39.787 ;
     RECT  2.304 38.939 9.234 39.865 ;
     RECT  10.044 39.757 16.002 39.865 ;
     RECT  17.172 39.787 17.262 40.019 ;
     RECT  0.036 38.983 0.558 40.075 ;
     RECT  0.036 40.075 0.666 40.205 ;
     RECT  2.304 39.865 16.002 40.205 ;
     RECT  2.304 40.205 15.966 40.469 ;
     RECT  0.036 40.205 0.558 40.559 ;
     RECT  2.304 40.469 9.45 40.589 ;
     RECT  2.415 40.589 9.45 40.733 ;
     RECT  2.415 40.733 9.378 40.739 ;
     RECT  10.224 40.469 15.966 40.973 ;
     RECT  10.26 40.973 15.966 41.009 ;
     RECT  2.415 40.739 9.054 41.099 ;
     RECT  12.24 41.009 15.966 41.135 ;
     RECT  17.172 40.747 17.19 41.323 ;
     RECT  17.136 41.323 17.19 41.515 ;
     RECT  2.415 41.099 8.982 41.611 ;
     RECT  12.888 41.135 15.966 41.707 ;
     RECT  0.108 40.559 0.558 41.741 ;
     RECT  10.26 41.009 11.43 41.755 ;
     RECT  2.34 41.611 8.982 41.791 ;
     RECT  10.26 41.755 11.79 41.791 ;
     RECT  17.1 41.515 17.19 41.981 ;
     RECT  12.888 41.707 16.254 42.025 ;
     RECT  10.152 41.791 11.79 42.151 ;
     RECT  10.008 42.151 11.79 42.181 ;
     RECT  12.564 42.025 16.254 42.181 ;
     RECT  10.008 42.181 16.254 42.259 ;
     RECT  2.304 41.791 8.982 42.601 ;
     RECT  9.756 42.259 16.254 42.601 ;
     RECT  0.144 41.741 0.558 42.646 ;
     RECT  2.304 42.601 16.254 42.667 ;
     RECT  0.108 42.646 0.594 42.719 ;
     RECT  2.268 42.667 16.254 42.755 ;
     RECT  2.304 42.755 16.254 42.859 ;
     RECT  17.172 41.981 17.19 42.859 ;
     RECT  2.304 42.859 17.19 43.133 ;
     RECT  15.804 43.133 17.19 43.331 ;
     RECT  15.84 43.331 17.19 43.469 ;
     RECT  2.304 43.133 14.886 43.915 ;
     RECT  2.304 43.915 14.922 44.149 ;
     RECT  15.84 43.469 16.254 44.149 ;
     RECT  2.304 44.149 16.254 44.203 ;
     RECT  2.268 44.203 16.254 44.249 ;
     RECT  2.268 44.249 15.93 44.519 ;
     RECT  2.304 44.519 15.93 44.609 ;
     RECT  12.024 44.609 15.93 44.753 ;
     RECT  12.672 44.753 15.93 44.765 ;
     RECT  17.136 43.469 17.19 44.779 ;
     RECT  17.1 44.779 17.19 44.806 ;
     RECT  0.108 42.719 0.558 44.813 ;
     RECT  17.1 44.806 17.262 44.834 ;
     RECT  0.54 44.813 0.558 44.909 ;
     RECT  13.215 44.765 15.93 44.995 ;
     RECT  13.215 44.995 16.002 45.229 ;
     RECT  2.34 44.609 10.854 45.355 ;
     RECT  2.304 45.355 10.854 45.739 ;
     RECT  2.232 45.739 10.854 45.769 ;
     RECT  2.232 45.769 11.286 45.797 ;
     RECT  12.456 45.571 12.474 45.841 ;
     RECT  13.215 45.229 16.038 45.841 ;
     RECT  2.304 45.797 11.286 45.931 ;
     RECT  0.252 45.931 0.342 45.979 ;
     RECT  0.216 45.979 0.342 46.003 ;
     RECT  0.18 46.003 0.342 46.027 ;
     RECT  2.304 45.931 11.718 46.237 ;
     RECT  12.456 45.841 16.038 46.237 ;
     RECT  2.304 46.237 16.038 46.315 ;
     RECT  17.136 44.834 17.262 46.409 ;
     RECT  2.304 46.315 16.29 46.795 ;
     RECT  0.144 46.027 0.342 47.119 ;
     RECT  0.144 47.119 0.558 47.281 ;
     RECT  2.304 46.795 16.506 47.467 ;
     RECT  2.268 47.467 16.506 47.755 ;
     RECT  17.244 46.409 17.262 47.755 ;
     RECT  2.268 47.755 17.262 47.759 ;
     RECT  2.304 47.759 17.262 48.263 ;
     RECT  0.108 47.281 0.558 49.081 ;
     RECT  2.304 48.263 17.154 49.099 ;
     RECT  2.304 49.099 17.19 49.126 ;
     RECT  0.108 49.081 1.134 49.133 ;
     RECT  0.144 49.133 1.134 49.154 ;
     RECT  0.144 49.154 0.522 49.229 ;
     RECT  0.144 49.229 0.486 49.901 ;
     RECT  2.304 49.126 17.226 50.315 ;
     RECT  0.144 49.901 0.45 50.333 ;
     RECT  0.144 50.333 0.378 50.381 ;
     RECT  2.34 50.315 17.226 50.459 ;
     RECT  2.376 50.459 17.226 50.657 ;
     RECT  8.928 50.657 17.226 50.891 ;
     RECT  0.144 50.381 0.162 51.197 ;
     RECT  2.376 50.657 8.154 51.211 ;
     RECT  8.964 50.891 17.226 51.233 ;
     RECT  8.964 51.233 17.19 51.256 ;
     RECT  2.34 51.211 8.154 51.355 ;
     RECT  0.216 51.307 0.342 51.437 ;
     RECT  0.216 51.437 0.234 51.629 ;
     RECT  1.404 49.963 1.422 52.079 ;
     RECT  2.268 51.355 8.154 52.249 ;
     RECT  9.144 51.256 17.19 52.249 ;
     RECT  0.54 52.213 0.558 52.973 ;
     RECT  2.268 52.249 17.19 52.987 ;
     RECT  0.108 52.987 0.342 53.069 ;
     RECT  2.232 52.987 17.19 53.087 ;
     RECT  0.144 53.069 0.342 53.549 ;
     RECT  0.144 53.549 0.162 53.885 ;
     RECT  2.304 53.087 17.19 53.986 ;
     RECT  2.304 53.986 17.262 54.283 ;
     RECT  0.324 54.571 0.342 54.701 ;
     RECT  1.98 54.283 17.262 55.579 ;
     RECT  0.144 55.579 0.162 55.627 ;
     RECT  0.144 55.627 0.342 55.757 ;
     RECT  0.144 55.757 0.162 56.285 ;
     RECT  0.18 56.491 0.342 56.621 ;
     RECT  0.18 56.621 0.198 56.861 ;
     RECT  1.728 55.579 17.262 57.163 ;
     RECT  0.144 57.067 0.162 57.341 ;
     RECT  0.324 57.739 0.342 57.869 ;
     RECT  1.152 57.163 17.262 58.181 ;
     RECT  2.232 58.181 17.262 58.451 ;
     RECT  1.152 58.181 1.17 59.873 ;
     RECT  2.304 58.451 17.262 59.999 ;
     RECT  2.34 59.999 17.262 60.647 ;
     RECT  2.34 60.647 17.226 60.719 ;
     RECT  0.036 60.313 0.054 61.051 ;
     RECT  0.036 61.051 0.126 61.159 ;
     RECT  0.036 61.159 0.522 61.393 ;
     RECT  2.34 60.719 16.47 61.691 ;
     RECT  2.34 61.691 16.434 61.771 ;
     RECT  2.304 61.771 16.434 61.889 ;
     RECT  17.208 60.719 17.226 62.114 ;
     RECT  2.34 61.889 16.434 62.779 ;
     RECT  2.304 62.779 16.434 62.807 ;
     RECT  0.036 61.393 0.558 62.827 ;
     RECT  0.036 62.827 0.666 62.957 ;
     RECT  0.036 62.957 0.522 63.149 ;
     RECT  2.304 62.807 16.362 63.211 ;
     RECT  2.268 63.211 16.362 63.275 ;
     RECT  2.268 63.275 16.326 63.347 ;
     RECT  0.036 63.149 0.234 63.419 ;
     RECT  0.108 63.419 0.234 63.883 ;
     RECT  0.108 63.883 0.342 64.685 ;
     RECT  2.304 63.347 16.326 64.831 ;
     RECT  17.172 64.843 17.19 65.227 ;
     RECT  17.1 65.227 17.19 65.326 ;
     RECT  0.108 64.685 0.306 65.357 ;
     RECT  2.232 64.831 16.326 65.515 ;
     RECT  17.1 65.326 17.262 65.515 ;
     RECT  0.108 65.357 0.27 65.693 ;
     RECT  0.108 65.693 0.198 65.981 ;
     RECT  2.232 65.515 17.262 66.221 ;
     RECT  0.108 65.981 0.126 66.763 ;
     RECT  2.304 66.221 17.262 66.955 ;
     RECT  2.268 66.955 17.262 67.127 ;
     RECT  0.108 66.763 0.198 67.369 ;
     RECT  0.108 67.369 0.558 67.853 ;
     RECT  0.18 67.853 0.558 68.429 ;
     RECT  0.18 68.429 0.198 68.587 ;
     RECT  2.304 67.127 17.262 69.017 ;
     RECT  0.108 68.587 0.198 69.163 ;
     RECT  0.108 69.163 0.342 69.863 ;
     RECT  0.18 69.863 0.342 69.869 ;
     RECT  0.18 69.869 0.198 70.013 ;
     RECT  2.304 69.017 17.19 70.027 ;
     RECT  1.728 70.027 17.19 70.033 ;
     RECT  0.54 71.221 0.558 71.275 ;
     RECT  0.324 71.275 0.558 71.371 ;
     RECT  1.728 70.033 17.262 71.411 ;
     RECT  0.108 71.371 0.558 71.885 ;
     RECT  1.764 71.411 17.262 72.059 ;
     RECT  0.108 71.885 0.342 72.257 ;
     RECT  0.324 72.257 0.342 72.269 ;
     RECT  1.152 72.619 1.17 72.715 ;
     RECT  0.576 72.715 1.17 73.003 ;
     RECT  0.144 73.003 1.17 73.483 ;
     RECT  2.016 72.059 17.262 73.579 ;
     RECT  0.144 73.483 1.242 73.777 ;
     RECT  0.072 73.777 1.242 74.395 ;
     RECT  1.98 73.579 17.262 75.029 ;
     RECT  0.036 74.395 1.242 75.389 ;
     RECT  0.036 75.389 0.846 77.009 ;
     RECT  0.036 77.009 0.09 77.081 ;
     RECT  1.98 75.029 17.19 77.081 ;
     RECT  0.036 77.081 0.054 77.657 ;
     RECT  0.828 77.009 0.846 77.855 ;
     RECT  1.98 77.081 17.154 78.269 ;
     RECT  2.016 78.269 17.154 78.539 ;
     RECT  2.304 78.539 17.154 78.637 ;
     RECT  2.304 78.637 17.19 79.745 ;
     RECT  2.304 79.745 16.506 79.889 ;
     RECT  2.304 79.889 16.47 80.683 ;
     RECT  2.268 80.683 16.47 80.789 ;
     RECT  2.304 80.789 16.47 81.473 ;
     RECT  2.304 81.473 16.326 81.671 ;
     RECT  15.84 81.671 16.326 82.481 ;
     RECT  16.308 82.481 16.326 82.787 ;
     RECT  2.304 81.671 15.066 84.065 ;
     RECT  2.304 84.065 14.958 84.875 ;
     RECT  2.304 84.875 14.778 85.649 ;
     RECT  8.964 85.649 14.778 85.793 ;
     RECT  9 85.793 14.778 86.099 ;
     RECT  9 86.099 11.358 86.225 ;
     RECT  9 86.225 11.25 86.297 ;
     RECT  12.456 86.099 14.778 86.341 ;
     RECT  9 86.297 10.926 86.369 ;
     RECT  2.304 85.649 8.226 86.459 ;
     RECT  9 86.369 9.738 86.459 ;
     RECT  12.456 86.341 14.922 86.495 ;
     RECT  14.904 86.495 14.922 86.567 ;
     RECT  9.108 86.459 9.738 86.729 ;
     RECT  12.456 86.495 13.95 86.765 ;
     RECT  2.376 86.459 8.226 86.957 ;
     RECT  2.376 86.957 3.762 87.149 ;
     RECT  10.692 86.369 10.926 87.151 ;
     RECT  4.68 86.957 8.226 87.241 ;
     RECT  9.108 86.729 9.666 87.241 ;
     RECT  10.692 87.151 11.43 87.269 ;
     RECT  12.456 86.765 13.497 87.305 ;
     RECT  2.415 87.149 3.762 87.575 ;
     RECT  10.692 87.269 10.818 87.575 ;
     RECT  12.456 87.305 12.474 87.683 ;
     RECT  2.415 87.575 2.934 87.773 ;
     RECT  4.68 87.241 9.666 87.809 ;
     RECT  3.924 87.739 3.942 87.845 ;
     RECT  10.8 87.575 10.818 87.845 ;
     RECT  4.716 87.809 9.666 87.953 ;
     RECT  4.788 87.953 9.666 88.079 ;
     RECT  6.264 88.079 9.666 88.115 ;
     RECT  6.264 88.115 6.894 88.187 ;
     RECT  7.812 88.115 9.666 88.231 ;
     RECT  7.812 88.231 9.954 88.349 ;
     RECT  6.264 88.187 6.786 88.385 ;
     RECT  7.812 88.349 9.63 88.397 ;
     RECT  6.372 88.385 6.786 88.421 ;
     RECT  6.624 88.421 6.786 88.493 ;
     RECT  6.768 88.493 6.786 88.619 ;
     RECT  7.815 88.397 8.55 88.619 ;
     RECT  9.612 88.397 9.63 88.655 ;
     RECT  7.815 88.619 8.514 88.691 ;
     RECT  2.415 87.773 2.697 94.787 ;
     RECT  7.815 88.691 8.097 94.787 ;
     RECT  13.215 87.305 13.497 94.787 ;
     RECT  2.415 94.787 2.505 95.057 ;
     RECT  7.815 94.787 7.905 95.057 ;
     RECT  13.215 94.787 13.305 95.057 ;
    LAYER M4 ;
     RECT  0.025 74.4 0.06 74.424 ;
     RECT  0.06 20.496 0.061 58.056 ;
     RECT  0.06 61.968 0.137 74.424 ;
     RECT  0.061 20.4 0.173 58.056 ;
     RECT  0.137 61.968 0.569 74.088 ;
     RECT  0.173 20.688 2.257 58.056 ;
     RECT  0.569 62.16 2.293 74.088 ;
     RECT  2.293 11.952 2.329 11.976 ;
     RECT  1.969 17.088 2.329 17.112 ;
     RECT  2.293 18.144 2.329 18.168 ;
     RECT  2.293 15.408 2.365 15.432 ;
     RECT  2.257 80.688 2.365 80.712 ;
     RECT  2.329 11.52 2.408 11.976 ;
     RECT  2.293 14.208 2.408 14.232 ;
     RECT  2.365 15.408 2.408 15.864 ;
     RECT  2.329 17.088 2.408 18.168 ;
     RECT  2.293 19.584 2.408 19.608 ;
     RECT  2.257 20.688 2.408 58.152 ;
     RECT  2.293 62.16 2.408 74.472 ;
     RECT  2.293 75.696 2.408 75.72 ;
     RECT  2.365 80.688 2.408 80.904 ;
     RECT  2.365 82.704 2.408 82.728 ;
     RECT  2.365 87.12 2.408 87.144 ;
     RECT  2.408 2.148 2.512 95.052 ;
     RECT  2.512 2.418 2.704 94.782 ;
     RECT  2.704 61.344 2.909 73.8 ;
     RECT  2.704 82.704 3.197 86.04 ;
     RECT  3.197 82.704 3.203 85.944 ;
     RECT  2.909 61.344 3.233 73.368 ;
     RECT  3.233 61.344 3.413 73.32 ;
     RECT  3.203 82.704 3.443 84.744 ;
     RECT  2.704 10.848 3.628 11.544 ;
     RECT  2.704 17.136 3.685 18.264 ;
     RECT  2.704 80.352 3.685 80.904 ;
     RECT  3.443 82.704 3.685 83.64 ;
     RECT  2.704 14.256 3.692 15.864 ;
     RECT  2.704 77.808 3.697 77.832 ;
     RECT  2.704 78.912 3.697 79.08 ;
     RECT  3.692 14.208 3.733 15.864 ;
     RECT  3.685 17.04 3.733 18.408 ;
     RECT  3.628 11.472 3.737 11.544 ;
     RECT  3.685 80.352 3.737 83.64 ;
     RECT  3.733 14.208 3.769 18.408 ;
     RECT  2.704 19.488 3.769 19.512 ;
     RECT  3.769 14.208 3.779 19.512 ;
     RECT  3.697 77.808 3.805 79.08 ;
     RECT  3.779 14.256 3.827 19.512 ;
     RECT  2.704 59.424 3.841 59.736 ;
     RECT  3.841 59.424 3.877 59.832 ;
     RECT  3.805 77.808 3.877 79.272 ;
     RECT  3.737 80.352 3.877 82.728 ;
     RECT  3.827 16.512 3.881 19.512 ;
     RECT  3.877 77.808 3.923 82.728 ;
     RECT  3.805 76.368 3.925 76.776 ;
     RECT  3.923 77.808 3.925 79.608 ;
     RECT  3.925 76.368 3.964 79.608 ;
     RECT  3.964 76.368 3.971 78.696 ;
     RECT  3.923 80.88 3.971 82.728 ;
     RECT  2.704 87.12 3.973 87.768 ;
     RECT  2.704 20.832 4.021 58.152 ;
     RECT  3.877 59.232 4.021 59.832 ;
     RECT  3.881 16.608 4.025 19.512 ;
     RECT  4.021 20.832 4.025 59.832 ;
     RECT  3.973 86.928 4.06 87.768 ;
     RECT  3.413 61.344 4.061 72.888 ;
     RECT  4.025 34.752 4.115 59.832 ;
     RECT  4.025 20.832 4.201 33.768 ;
     RECT  4.201 20.64 4.261 33.768 ;
     RECT  4.061 71.856 4.349 72.888 ;
     RECT  4.115 34.8 4.381 59.832 ;
     RECT  4.061 61.344 4.381 70.728 ;
     RECT  3.971 80.88 4.385 81.24 ;
     RECT  4.261 20.544 4.444 33.768 ;
     RECT  4.025 17.04 4.457 19.512 ;
     RECT  4.069 1.728 4.529 1.752 ;
     RECT  4.381 34.8 4.529 70.728 ;
     RECT  4.529 34.8 4.565 70.536 ;
     RECT  4.549 75.216 4.745 75.24 ;
     RECT  4.349 71.856 4.817 71.88 ;
     RECT  4.06 87.744 4.817 87.768 ;
     RECT  4.349 72.864 4.988 72.888 ;
     RECT  3.971 76.368 4.988 76.632 ;
     RECT  3.971 77.664 5.069 78.696 ;
     RECT  4.988 72.864 5.075 72.984 ;
     RECT  3.827 14.256 5.109 15.432 ;
     RECT  4.988 76.224 5.141 76.632 ;
     RECT  4.453 12.24 5.171 12.264 ;
     RECT  4.741 9.792 5.173 9.816 ;
     RECT  5.125 11.04 5.173 11.064 ;
     RECT  4.849 74.4 5.173 74.952 ;
     RECT  4.021 7.2 5.219 7.224 ;
     RECT  5.132 8.496 5.219 8.52 ;
     RECT  3.443 84.72 5.249 84.744 ;
     RECT  4.444 20.64 5.281 33.768 ;
     RECT  4.565 34.8 5.281 70.488 ;
     RECT  5.281 20.64 5.321 70.488 ;
     RECT  5.321 28.272 5.465 70.488 ;
     RECT  5.069 78.672 5.465 78.696 ;
     RECT  4.489 86.592 5.465 86.616 ;
     RECT  5.465 28.272 5.537 38.136 ;
     RECT  5.069 77.664 5.537 77.688 ;
     RECT  5.321 20.64 5.564 26.856 ;
     RECT  5.465 39.216 5.569 70.488 ;
     RECT  5.029 71.52 5.569 71.832 ;
     RECT  5.173 9.792 5.573 11.064 ;
     RECT  5.573 10.176 5.651 11.064 ;
     RECT  5.564 20.496 5.651 26.856 ;
     RECT  5.109 13.584 5.677 15.432 ;
     RECT  5.173 74.016 5.708 74.952 ;
     RECT  4.457 17.088 5.713 19.512 ;
     RECT  5.677 13.344 5.747 15.432 ;
     RECT  5.708 74.016 5.747 75.576 ;
     RECT  4.385 81.216 5.785 81.24 ;
     RECT  5.569 39.216 5.797 71.832 ;
     RECT  5.281 84.288 5.821 84.456 ;
     RECT  5.651 10.704 5.857 11.064 ;
     RECT  5.651 21.36 5.884 26.856 ;
     RECT  5.075 72.864 5.933 72.888 ;
     RECT  5.713 17.088 5.965 20.376 ;
     RECT  5.749 76.992 6.005 77.544 ;
     RECT  5.884 21.456 6.041 26.856 ;
     RECT  5.996 7.392 6.083 7.416 ;
     RECT  5.965 16.8 6.145 20.376 ;
     RECT  5.797 39.216 6.145 71.88 ;
     RECT  5.747 74.928 6.145 75.576 ;
     RECT  5.747 13.344 6.149 15.048 ;
     RECT  6.145 39.216 6.185 72.072 ;
     RECT  5.173 79.68 6.217 79.704 ;
     RECT  3.971 82.704 6.277 82.728 ;
     RECT  5.821 84 6.277 84.456 ;
     RECT  6.145 74.928 6.325 75.72 ;
     RECT  6.145 7.584 6.361 7.608 ;
     RECT  6.149 14.544 6.365 15.048 ;
     RECT  6.185 39.216 6.365 70.152 ;
     RECT  5.537 28.416 6.433 38.136 ;
     RECT  6.365 39.216 6.433 57.048 ;
     RECT  6.277 82.704 6.469 84.456 ;
     RECT  5.857 10.704 6.505 11.784 ;
     RECT  5.785 81.216 6.545 81.432 ;
     RECT  6.365 58.272 6.617 70.152 ;
     RECT  6.505 10.704 6.649 11.88 ;
     RECT  6.613 27.312 6.649 27.384 ;
     RECT  6.433 28.416 6.649 57.048 ;
     RECT  6.649 10.512 6.685 11.88 ;
     RECT  6.149 13.344 6.685 13.416 ;
     RECT  6.617 58.272 6.689 67.128 ;
     RECT  6.361 7.584 6.721 7.704 ;
     RECT  6.037 8.736 6.721 8.76 ;
     RECT  6.577 86.016 6.749 86.04 ;
     RECT  6.145 16.08 6.757 20.376 ;
     RECT  6.545 81.216 6.757 81.336 ;
     RECT  6.685 10.512 6.797 13.416 ;
     RECT  6.217 79.104 6.803 79.704 ;
     RECT  5.281 87.936 6.805 87.96 ;
     RECT  6.041 21.456 6.833 26.328 ;
     RECT  6.469 82.608 6.833 84.456 ;
     RECT  6.749 85.584 6.833 86.04 ;
     RECT  6.325 73.488 6.865 73.56 ;
     RECT  6.325 74.928 6.865 75.912 ;
     RECT  6.365 15.024 6.973 15.048 ;
     RECT  6.757 16.08 6.973 20.424 ;
     RECT  6.649 27.312 7.009 57.048 ;
     RECT  6.973 15.024 7.093 20.424 ;
     RECT  6.833 21.456 7.093 26.232 ;
     RECT  6.797 10.56 7.141 13.416 ;
     RECT  6.005 77.52 7.333 77.544 ;
     RECT  7.333 77.52 7.405 78.12 ;
     RECT  6.185 71.184 7.436 72.072 ;
     RECT  6.865 73.488 7.436 75.912 ;
     RECT  6.721 7.584 7.549 8.76 ;
     RECT  6.689 58.272 7.549 65.208 ;
     RECT  7.549 58.128 7.765 65.208 ;
     RECT  6.689 66.24 7.765 67.128 ;
     RECT  6.805 87.408 7.801 87.96 ;
     RECT  7.549 7.392 7.808 8.76 ;
     RECT  7.141 10.56 7.808 13.464 ;
     RECT  7.093 15.024 7.808 26.232 ;
     RECT  7.009 27.216 7.808 57.048 ;
     RECT  7.765 58.128 7.808 67.128 ;
     RECT  6.617 68.352 7.808 70.152 ;
     RECT  7.436 71.184 7.808 75.912 ;
     RECT  7.405 77.52 7.808 78.216 ;
     RECT  6.803 79.488 7.808 79.704 ;
     RECT  6.757 81.072 7.808 81.336 ;
     RECT  6.833 82.608 7.808 84.312 ;
     RECT  6.833 86.016 7.808 86.04 ;
     RECT  7.801 87.408 7.808 88.392 ;
     RECT  7.808 2.148 7.912 95.052 ;
     RECT  7.912 2.418 8.104 94.782 ;
     RECT  8.104 8.736 8.165 9.672 ;
     RECT  8.104 29.568 8.201 43.032 ;
     RECT  8.104 45.696 8.201 47.352 ;
     RECT  8.201 29.568 8.243 42.888 ;
     RECT  8.104 52.512 8.243 66.072 ;
     RECT  8.104 68.4 8.273 71.736 ;
     RECT  8.243 29.568 8.309 40.824 ;
     RECT  8.104 22.08 8.345 25.176 ;
     RECT  8.309 38.784 8.531 40.824 ;
     RECT  8.243 52.512 8.531 55.416 ;
     RECT  8.104 81.072 8.579 84.36 ;
     RECT  8.104 13.344 8.597 15.336 ;
     RECT  8.243 56.928 8.597 66.072 ;
     RECT  8.579 83.808 8.597 84.36 ;
     RECT  8.345 22.08 8.627 23.256 ;
     RECT  8.104 77.28 8.633 79.512 ;
     RECT  8.531 38.784 8.669 40.728 ;
     RECT  8.597 13.488 8.675 15.336 ;
     RECT  8.345 24.336 8.741 25.176 ;
     RECT  8.273 68.4 8.741 71.256 ;
     RECT  8.597 84 8.741 84.36 ;
     RECT  8.741 69.792 8.777 71.256 ;
     RECT  8.579 81.072 8.813 82.296 ;
     RECT  8.597 57.744 8.867 66.072 ;
     RECT  8.867 60 8.921 66.072 ;
     RECT  8.104 48.432 8.963 51.24 ;
     RECT  8.243 41.904 8.993 42.888 ;
     RECT  8.741 84.336 9.059 84.36 ;
     RECT  8.104 85.44 9.059 86.04 ;
     RECT  8.104 88.368 9.059 88.392 ;
     RECT  8.921 60 9.107 65.928 ;
     RECT  8.633 79.392 9.109 79.512 ;
     RECT  8.104 16.8 9.137 20.952 ;
     RECT  8.104 73.44 9.164 74.136 ;
     RECT  8.104 44.352 9.169 44.424 ;
     RECT  8.633 77.28 9.173 77.688 ;
     RECT  8.104 11.568 9.209 11.784 ;
     RECT  8.867 57.744 9.245 58.488 ;
     RECT  9.164 72.912 9.251 74.136 ;
     RECT  8.309 29.568 9.281 37.608 ;
     RECT  9.205 26.496 9.313 26.52 ;
     RECT  9.107 61.536 9.317 65.928 ;
     RECT  9.281 29.904 9.34 37.608 ;
     RECT  9.137 16.8 9.349 17.496 ;
     RECT  8.741 25.056 9.353 25.176 ;
     RECT  9.317 61.536 9.353 65.112 ;
     RECT  9.059 85.536 9.353 86.04 ;
     RECT  9.137 18.48 9.421 20.952 ;
     RECT  8.627 22.08 9.421 22.104 ;
     RECT  9.421 18.48 9.461 22.104 ;
     RECT  8.531 52.512 9.493 53.304 ;
     RECT  8.531 54.384 9.493 55.416 ;
     RECT  9.34 29.904 9.497 31.224 ;
     RECT  9.313 26.208 9.529 26.52 ;
     RECT  8.104 28.368 9.533 28.536 ;
     RECT  8.104 75.696 9.548 75.816 ;
     RECT  9.461 18.48 9.569 20.472 ;
     RECT  9.497 29.904 9.569 30.984 ;
     RECT  9.34 32.256 9.569 37.608 ;
     RECT  9.353 85.536 9.569 85.56 ;
     RECT  9.169 44.16 9.596 44.424 ;
     RECT  9.493 52.512 9.601 55.8 ;
     RECT  9.421 72.816 9.605 72.84 ;
     RECT  9.251 73.92 9.637 74.136 ;
     RECT  9.548 75.696 9.637 76.152 ;
     RECT  9.173 77.28 9.673 77.544 ;
     RECT  9.637 73.92 9.683 76.152 ;
     RECT  8.104 7.392 9.685 7.416 ;
     RECT  8.165 9.456 9.685 9.672 ;
     RECT  8.813 81.072 9.685 82.056 ;
     RECT  9.601 52.512 9.709 56.088 ;
     RECT  9.683 73.968 9.709 76.152 ;
     RECT  9.673 77.184 9.709 77.544 ;
     RECT  8.675 14.16 9.713 15.336 ;
     RECT  9.349 16.752 9.713 17.496 ;
     RECT  8.963 49.008 9.713 51.24 ;
     RECT  9.109 79.392 9.731 79.704 ;
     RECT  9.209 11.568 9.788 11.688 ;
     RECT  8.201 45.792 9.817 47.352 ;
     RECT  9.685 7.392 9.821 7.992 ;
     RECT  9.817 45.792 9.821 47.496 ;
     RECT  9.685 81.024 9.821 82.056 ;
     RECT  9.685 9.456 9.829 9.768 ;
     RECT  9.788 11.328 9.829 11.688 ;
     RECT  9.829 9.456 9.875 11.688 ;
     RECT  9.569 37.104 9.925 37.608 ;
     RECT  8.669 38.784 9.925 38.808 ;
     RECT  8.104 67.392 9.925 67.416 ;
     RECT  8.777 69.792 9.925 70.728 ;
     RECT  9.731 79.392 9.925 79.608 ;
     RECT  9.569 32.256 9.929 35.352 ;
     RECT  9.925 66.672 9.929 67.416 ;
     RECT  9.929 32.256 9.971 34.776 ;
     RECT  9.353 61.536 9.971 64.056 ;
     RECT  9.353 65.088 9.971 65.112 ;
     RECT  9.829 12.72 9.997 12.744 ;
     RECT  9.821 81.024 9.997 81.672 ;
     RECT  8.669 40.512 10.033 40.728 ;
     RECT  9.997 12.72 10.037 12.936 ;
     RECT  9.971 32.256 10.037 32.76 ;
     RECT  9.925 71.76 10.069 71.784 ;
     RECT  8.993 42.288 10.141 42.888 ;
     RECT  10.141 42.048 10.165 42.888 ;
     RECT  9.596 44.16 10.165 44.76 ;
     RECT  9.925 37.104 10.177 38.808 ;
     RECT  10.033 39.84 10.177 40.728 ;
     RECT  9.461 21.456 10.213 22.104 ;
     RECT  10.177 37.104 10.213 40.728 ;
     RECT  10.165 42.048 10.213 44.76 ;
     RECT  9.713 50.496 10.213 51.24 ;
     RECT  9.709 52.464 10.213 56.088 ;
     RECT  8.741 68.4 10.213 68.424 ;
     RECT  9.713 49.008 10.249 49.272 ;
     RECT  9.875 9.456 10.253 10.392 ;
     RECT  10.213 21.456 10.289 22.2 ;
     RECT  10.213 42 10.297 44.76 ;
     RECT  9.353 25.056 10.321 25.08 ;
     RECT  9.107 60 10.357 60.408 ;
     RECT  10.321 24.24 10.361 25.08 ;
     RECT  10.213 37.104 10.405 40.968 ;
     RECT  10.297 42 10.405 43.08 ;
     RECT  9.713 16.752 10.429 17.112 ;
     RECT  9.529 26.208 10.433 27.24 ;
     RECT  10.289 21.648 10.469 22.2 ;
     RECT  9.875 11.568 10.501 11.688 ;
     RECT  8.627 23.232 10.501 23.256 ;
     RECT  10.361 24.24 10.501 24.264 ;
     RECT  9.533 28.368 10.501 28.392 ;
     RECT  9.569 29.904 10.501 30.456 ;
     RECT  10.357 60 10.501 60.456 ;
     RECT  10.469 22.176 10.505 22.2 ;
     RECT  10.213 50.496 10.505 56.088 ;
     RECT  9.709 73.968 10.505 77.544 ;
     RECT  10.037 12.912 10.537 12.936 ;
     RECT  10.429 16.656 10.573 17.112 ;
     RECT  10.505 75.792 10.573 77.544 ;
     RECT  9.925 78.576 10.573 79.608 ;
     RECT  10.249 48.768 10.577 49.272 ;
     RECT  9.569 18.48 10.609 20.136 ;
     RECT  10.037 32.256 10.609 32.472 ;
     RECT  10.433 26.208 10.652 26.232 ;
     RECT  9.245 58.128 10.673 58.488 ;
     RECT  10.069 71.76 10.685 72.36 ;
     RECT  10.573 16.608 10.717 17.112 ;
     RECT  10.501 59.76 10.717 60.456 ;
     RECT  9.971 61.536 10.717 63.864 ;
     RECT  10.501 23.232 10.739 24.264 ;
     RECT  10.501 28.368 10.739 30.456 ;
     RECT  9.493 86.64 10.741 86.664 ;
     RECT  10.433 27.216 10.753 27.24 ;
     RECT  10.505 50.496 10.753 52.008 ;
     RECT  10.213 68.112 10.753 68.424 ;
     RECT  9.925 69.6 10.753 70.728 ;
     RECT  10.739 29.04 10.757 30.456 ;
     RECT  10.297 44.112 10.757 44.76 ;
     RECT  10.741 86.016 10.787 86.664 ;
     RECT  10.673 58.128 10.789 58.728 ;
     RECT  10.573 75.792 10.789 79.608 ;
     RECT  9.997 80.832 10.789 81.672 ;
     RECT  10.537 12.912 10.825 13.032 ;
     RECT  9.713 14.16 10.825 14.952 ;
     RECT  10.609 18.48 10.825 20.184 ;
     RECT  9.821 45.792 10.825 46.248 ;
     RECT  9.821 47.28 10.825 47.496 ;
     RECT  10.577 49.008 10.825 49.272 ;
     RECT  10.753 50.448 10.825 52.008 ;
     RECT  10.505 73.968 10.825 74.568 ;
     RECT  10.789 75.792 10.825 81.672 ;
     RECT  10.787 86.016 10.828 86.04 ;
     RECT  10.685 72.336 10.837 72.36 ;
     RECT  10.825 73.632 10.837 74.568 ;
     RECT  10.739 23.232 10.861 23.88 ;
     RECT  10.789 58.08 10.861 58.728 ;
     RECT  10.501 11.568 10.865 11.88 ;
     RECT  10.757 44.112 10.865 44.472 ;
     RECT  10.861 22.896 10.901 23.88 ;
     RECT  10.825 45.792 10.901 47.496 ;
     RECT  9.929 66.672 10.933 66.696 ;
     RECT  10.753 68.112 10.933 71.352 ;
     RECT  10.285 84.864 10.933 84.888 ;
     RECT  10.717 59.76 10.973 63.864 ;
     RECT  10.933 36.096 10.988 36.12 ;
     RECT  10.405 37.104 10.988 43.08 ;
     RECT  10.973 59.76 11.009 63.768 ;
     RECT  10.933 66.624 11.02 71.352 ;
     RECT  10.825 75.792 11.027 82.632 ;
     RECT  10.825 18.48 11.045 20.424 ;
     RECT  10.933 84.864 11.045 85.704 ;
     RECT  10.988 36.096 11.075 43.08 ;
     RECT  10.988 65.52 11.075 65.544 ;
     RECT  10.825 12.912 11.081 14.952 ;
     RECT  11.045 18.48 11.081 20.136 ;
     RECT  11.075 38.112 11.081 43.08 ;
     RECT  11.075 37.104 11.117 37.128 ;
     RECT  10.505 53.232 11.117 56.088 ;
     RECT  10.837 72.336 11.123 74.568 ;
     RECT  11.02 66.624 11.149 66.744 ;
     RECT  10.861 57.84 11.153 58.728 ;
     RECT  11.027 82.128 11.153 82.632 ;
     RECT  10.253 10.368 11.225 10.392 ;
     RECT  10.652 25.536 11.225 26.232 ;
     RECT  11.149 66.528 11.26 66.744 ;
     RECT  11.153 57.84 11.261 58.536 ;
     RECT  10.717 16.56 11.293 17.112 ;
     RECT  9.971 34.32 11.317 34.776 ;
     RECT  11.293 16.56 11.329 17.16 ;
     RECT  11.009 59.76 11.365 60.072 ;
     RECT  11.081 38.112 11.369 40.968 ;
     RECT  11.365 59.712 11.369 60.072 ;
     RECT  11.369 38.112 11.405 38.808 ;
     RECT  11.081 42.192 11.405 43.08 ;
     RECT  11.261 58.368 11.405 58.536 ;
     RECT  10.825 49.008 11.468 52.008 ;
     RECT  11.117 53.232 11.468 55.32 ;
     RECT  11.123 72.528 11.477 74.568 ;
     RECT  11.027 75.792 11.477 80.952 ;
     RECT  10.609 32.208 11.581 32.472 ;
     RECT  11.468 49.008 11.585 55.32 ;
     RECT  11.02 68.112 11.621 71.352 ;
     RECT  11.081 13.44 11.653 14.952 ;
     RECT  10.901 22.896 11.653 23.256 ;
     RECT  11.26 66.48 11.657 66.744 ;
     RECT  11.477 72.816 11.725 74.568 ;
     RECT  11.477 75.792 11.725 80.328 ;
     RECT  11.653 13.44 11.74 15.48 ;
     RECT  10.645 9.216 11.869 9.24 ;
     RECT  11.075 36.096 11.869 36.12 ;
     RECT  10.757 29.04 11.873 29.928 ;
     RECT  11.081 18.48 11.905 19.512 ;
     RECT  11.581 31.248 11.905 32.472 ;
     RECT  11.317 33.504 11.905 34.776 ;
     RECT  11.657 66.72 11.909 66.744 ;
     RECT  11.905 31.248 11.977 34.776 ;
     RECT  11.869 35.856 11.977 36.12 ;
     RECT  11.009 61.152 11.977 63.768 ;
     RECT  11.977 31.248 11.989 36.12 ;
     RECT  10.865 44.16 12.017 44.472 ;
     RECT  11.989 30.72 12.035 36.12 ;
     RECT  11.405 42.192 12.053 42.84 ;
     RECT  10.865 11.76 12.085 11.88 ;
     RECT  11.329 16.512 12.121 17.16 ;
     RECT  11.405 38.112 12.121 38.712 ;
     RECT  11.585 49.008 12.121 50.04 ;
     RECT  12.085 11.76 12.157 12.264 ;
     RECT  11.74 13.44 12.157 15 ;
     RECT  11.369 39.888 12.188 40.968 ;
     RECT  12.121 37.344 12.193 38.712 ;
     RECT  11.869 9.216 12.197 9.672 ;
     RECT  12.121 16.464 12.229 17.16 ;
     RECT  11.905 18.24 12.229 19.512 ;
     RECT  10.901 45.792 12.229 46.536 ;
     RECT  12.121 48.048 12.229 50.04 ;
     RECT  11.585 51.216 12.233 55.32 ;
     RECT  11.653 22.752 12.265 23.256 ;
     RECT  12.265 22.752 12.38 24.12 ;
     RECT  11.225 25.824 12.38 26.232 ;
     RECT  12.38 22.752 12.401 26.232 ;
     RECT  10.753 27.216 12.401 27.96 ;
     RECT  12.229 16.464 12.409 19.512 ;
     RECT  11.797 21.12 12.409 21.144 ;
     RECT  12.193 37.296 12.409 38.712 ;
     RECT  12.188 39.888 12.476 41.112 ;
     RECT  12.409 37.152 12.481 38.712 ;
     RECT  12.476 39.696 12.481 41.112 ;
     RECT  11.977 61.152 12.481 64.056 ;
     RECT  12.121 65.28 12.481 65.304 ;
     RECT  12.401 22.752 12.517 27.96 ;
     RECT  11.405 58.512 12.517 58.536 ;
     RECT  11.369 59.712 12.517 59.736 ;
     RECT  12.233 54.384 12.553 55.32 ;
     RECT  11.725 72.816 12.572 80.328 ;
     RECT  11.621 68.112 12.589 70.92 ;
     RECT  12.017 44.448 12.661 44.472 ;
     RECT  12.197 9.504 12.697 9.672 ;
     RECT  12.589 68.112 12.706 71.592 ;
     RECT  12.517 58.512 12.733 59.736 ;
     RECT  12.481 61.152 12.733 65.304 ;
     RECT  12.733 58.512 12.757 59.784 ;
     RECT  12.733 61.152 12.757 65.784 ;
     RECT  12.157 11.76 12.812 15 ;
     RECT  12.409 16.464 12.877 21.144 ;
     RECT  12.517 22.176 12.877 27.96 ;
     RECT  12.085 66.912 12.877 66.936 ;
     RECT  12.706 68.112 12.877 71.64 ;
     RECT  12.757 58.512 12.908 65.784 ;
     RECT  12.877 66.912 12.908 71.64 ;
     RECT  11.873 29.04 12.949 29.688 ;
     RECT  12.877 16.464 13.021 27.96 ;
     RECT  12.949 28.944 13.021 29.688 ;
     RECT  12.035 30.72 13.021 32.472 ;
     RECT  11.725 57.024 13.045 57.048 ;
     RECT  12.035 33.792 13.057 36.12 ;
     RECT  12.481 37.152 13.057 41.112 ;
     RECT  12.572 72.816 13.093 80.472 ;
     RECT  11.153 82.128 13.093 82.152 ;
     RECT  12.373 8.448 13.208 8.472 ;
     RECT  12.697 9.504 13.208 10.248 ;
     RECT  12.812 11.376 13.208 15 ;
     RECT  13.021 16.464 13.208 32.52 ;
     RECT  13.057 33.792 13.208 41.112 ;
     RECT  12.053 42.192 13.208 42.792 ;
     RECT  12.661 44.448 13.208 44.76 ;
     RECT  12.229 45.792 13.208 50.04 ;
     RECT  12.233 51.216 13.208 53.016 ;
     RECT  12.553 54.384 13.208 56.04 ;
     RECT  13.045 57.024 13.208 57.48 ;
     RECT  12.908 58.512 13.208 71.64 ;
     RECT  13.093 72.816 13.208 80.808 ;
     RECT  13.093 82.128 13.208 82.44 ;
     RECT  10.709 83.76 13.208 83.784 ;
     RECT  11.045 84.864 13.208 84.888 ;
     RECT  13.208 2.148 13.312 95.052 ;
     RECT  13.312 2.418 13.504 94.782 ;
     RECT  13.504 65.76 13.565 67.944 ;
     RECT  13.504 26.784 13.637 37.896 ;
     RECT  13.504 83.76 13.637 83.784 ;
     RECT  13.504 63.888 13.709 64.344 ;
     RECT  13.504 69.024 13.781 75.72 ;
     RECT  13.504 13.92 13.817 24.648 ;
     RECT  13.504 45.696 13.889 59.784 ;
     RECT  13.565 66.288 13.889 67.944 ;
     RECT  13.817 20.352 13.925 22.92 ;
     RECT  13.504 62.592 13.925 62.712 ;
     RECT  13.504 10.464 13.933 11.4 ;
     RECT  13.925 20.4 14.177 22.92 ;
     RECT  13.504 39.072 14.393 39.096 ;
     RECT  13.889 45.696 14.465 59.736 ;
     RECT  13.504 8.448 14.483 8.472 ;
     RECT  13.709 64.32 14.497 64.344 ;
     RECT  13.504 40.56 14.533 41.064 ;
     RECT  13.817 13.92 14.537 19.368 ;
     RECT  14.497 64.32 14.537 64.584 ;
     RECT  13.504 76.752 14.537 79.272 ;
     RECT  14.537 77.664 14.569 79.272 ;
     RECT  13.504 44.592 14.605 44.616 ;
     RECT  14.465 45.696 14.605 57 ;
     RECT  14.537 64.56 14.605 64.584 ;
     RECT  14.605 44.592 14.677 57 ;
     RECT  14.677 44.496 14.713 57 ;
     RECT  14.533 40.56 14.749 41.448 ;
     RECT  13.504 42.576 14.749 43.08 ;
     RECT  14.713 44.112 14.749 57 ;
     RECT  14.537 14.112 14.789 19.368 ;
     RECT  13.925 62.688 14.789 62.712 ;
     RECT  14.569 77.664 14.789 79.32 ;
     RECT  14.465 58.128 14.819 59.736 ;
     RECT  14.177 20.496 14.821 22.92 ;
     RECT  13.817 23.904 14.821 24.648 ;
     RECT  13.637 26.832 14.821 37.896 ;
     RECT  14.819 58.752 14.825 59.736 ;
     RECT  14.749 42.576 14.861 57 ;
     RECT  13.889 67.536 14.893 67.944 ;
     RECT  13.781 69.504 14.893 75.72 ;
     RECT  14.789 15.84 14.897 19.368 ;
     RECT  14.825 59.712 14.897 59.736 ;
     RECT  14.897 16.848 14.933 19.368 ;
     RECT  14.933 18.816 14.965 19.368 ;
     RECT  14.749 39.888 14.965 41.448 ;
     RECT  14.861 42.576 14.965 42.792 ;
     RECT  14.789 77.664 14.969 78.648 ;
     RECT  14.893 67.536 15.001 68.04 ;
     RECT  13.504 80.304 15.005 80.328 ;
     RECT  13.933 10.464 15.011 10.488 ;
     RECT  14.965 18.816 15.049 19.416 ;
     RECT  14.821 26.448 15.061 37.896 ;
     RECT  13.889 66.288 15.073 66.408 ;
     RECT  15.001 67.536 15.073 68.328 ;
     RECT  15.049 18.816 15.107 18.84 ;
     RECT  14.969 78.624 15.113 78.648 ;
     RECT  15.061 26.064 15.181 37.896 ;
     RECT  14.789 14.112 15.185 14.136 ;
     RECT  14.821 20.496 15.253 24.648 ;
     RECT  15.181 25.68 15.253 37.896 ;
     RECT  14.965 39.888 15.361 42.792 ;
     RECT  15.253 20.496 15.397 37.896 ;
     RECT  15.361 39.696 15.397 42.792 ;
     RECT  15.397 20.496 15.541 38.088 ;
     RECT  14.861 43.92 15.649 57 ;
     RECT  15.073 66.288 15.649 68.328 ;
     RECT  14.893 69.504 15.649 76.68 ;
     RECT  14.897 15.84 15.683 15.864 ;
     RECT  14.605 64.56 15.685 65.16 ;
     RECT  15.649 66.288 15.685 76.68 ;
     RECT  14.933 16.848 15.779 17.64 ;
     RECT  15.541 20.4 15.793 38.088 ;
     RECT  15.397 39.12 15.829 42.792 ;
     RECT  15.649 43.92 15.829 57.48 ;
     RECT  15.793 19.92 15.937 38.088 ;
     RECT  15.829 39.12 15.937 57.48 ;
     RECT  15.685 64.56 15.937 76.68 ;
     RECT  15.779 16.848 16.259 17.4 ;
     RECT  16.259 17.04 16.355 17.4 ;
     RECT  15.937 64.464 16.369 76.68 ;
     RECT  16.355 17.04 16.403 17.064 ;
     RECT  16.369 64.464 16.481 76.92 ;
     RECT  15.937 19.92 17.244 57.48 ;
     RECT  16.481 64.464 17.244 76.68 ;
    LAYER M5 ;
     RECT  3.984 0.016 4.104 1.763 ;
     RECT  2.4 2.137 2.52 2.151 ;
     RECT  7.8 2.137 7.92 2.151 ;
     RECT  13.2 2.137 13.32 2.151 ;
     RECT  5.184 7.189 5.208 7.381 ;
     RECT  13.2 2.151 13.512 8.437 ;
     RECT  5.184 7.381 6.072 8.725 ;
     RECT  7.8 2.151 8.112 8.725 ;
     RECT  5.184 8.725 8.112 8.771 ;
     RECT  9.696 7.957 9.72 9.733 ;
     RECT  9.696 9.733 9.864 9.779 ;
     RECT  5.184 8.771 5.208 10.165 ;
     RECT  13.2 8.437 14.472 10.213 ;
     RECT  12.864 10.213 14.472 10.453 ;
     RECT  2.4 2.151 2.712 10.837 ;
     RECT  3.984 1.763 4.008 10.837 ;
     RECT  5.184 10.165 5.64 11.029 ;
     RECT  5.136 11.029 5.64 11.075 ;
     RECT  6.912 8.771 8.112 11.363 ;
     RECT  2.4 10.837 4.008 11.459 ;
     RECT  7.392 11.363 8.112 11.653 ;
     RECT  2.4 11.459 2.712 11.941 ;
     RECT  9.84 9.779 9.864 12.755 ;
     RECT  7.392 11.653 8.664 13.429 ;
     RECT  3.984 11.459 4.008 14.197 ;
     RECT  5.136 11.075 5.16 14.197 ;
     RECT  3.744 14.197 4.008 14.245 ;
     RECT  5.136 14.197 5.736 14.245 ;
     RECT  7.152 13.429 8.664 14.339 ;
     RECT  3.744 14.245 5.736 14.533 ;
     RECT  12.864 10.453 15 14.867 ;
     RECT  7.152 14.339 8.112 15.347 ;
     RECT  2.304 11.941 2.712 15.443 ;
     RECT  3.744 14.533 6.168 15.443 ;
     RECT  11.664 14.197 11.688 15.491 ;
     RECT  13.2 14.867 15 15.829 ;
     RECT  13.2 15.829 15.672 16.837 ;
     RECT  7.8 15.347 8.112 16.981 ;
     RECT  3.744 15.443 5.16 17.029 ;
     RECT  13.2 16.837 16.248 17.029 ;
     RECT  6.144 15.443 6.168 17.077 ;
     RECT  7.8 16.981 9.096 17.077 ;
     RECT  2.4 15.443 2.712 17.125 ;
     RECT  3.696 17.029 5.16 17.125 ;
     RECT  2.4 17.125 5.16 18.133 ;
     RECT  2.304 18.133 5.16 18.229 ;
     RECT  6.144 17.077 6.264 18.229 ;
     RECT  2.304 18.229 6.264 19.285 ;
     RECT  7.392 17.077 9.768 19.285 ;
     RECT  2.304 19.285 9.768 19.523 ;
     RECT  2.304 19.523 9.096 19.619 ;
     RECT  2.4 19.619 9.096 19.955 ;
     RECT  13.2 17.029 16.392 21.395 ;
     RECT  13.2 21.395 13.704 22.165 ;
     RECT  2.4 19.955 8.856 22.451 ;
     RECT  2.4 22.451 6.744 22.787 ;
     RECT  15.072 21.395 16.392 22.885 ;
     RECT  15.072 22.885 17.112 23.075 ;
     RECT  12.528 22.165 13.704 23.317 ;
     RECT  12.432 23.317 13.704 23.987 ;
     RECT  2.4 22.787 6.504 24.515 ;
     RECT  15.072 23.075 16.392 24.947 ;
     RECT  15.072 24.947 16.344 25.523 ;
     RECT  15.072 25.523 15.768 26.099 ;
     RECT  0.144 26.005 0.168 26.195 ;
     RECT  15.744 26.099 15.768 26.195 ;
     RECT  2.4 24.515 6.168 26.387 ;
     RECT  12.432 23.987 13.512 26.819 ;
     RECT  10.704 23.317 10.728 28.403 ;
     RECT  0.144 28.213 0.168 28.499 ;
     RECT  7.8 22.451 8.856 29.365 ;
     RECT  4.08 26.387 6.168 29.605 ;
     RECT  7.44 29.365 8.856 29.605 ;
     RECT  2.4 26.387 3 30.277 ;
     RECT  4.08 29.605 8.856 30.277 ;
     RECT  2.4 30.277 8.856 30.419 ;
     RECT  2.4 30.419 3 30.851 ;
     RECT  4.08 30.419 8.856 30.853 ;
     RECT  14.784 30.757 14.808 30.899 ;
     RECT  17.088 30.757 17.112 30.947 ;
     RECT  4.08 30.853 9.288 31.379 ;
     RECT  4.08 31.379 5.496 31.619 ;
     RECT  2.4 30.851 2.904 31.811 ;
     RECT  12 30.709 12.024 32.341 ;
     RECT  7.8 31.379 9.288 33.445 ;
     RECT  11.328 32.341 12.024 33.781 ;
     RECT  13.2 26.819 13.512 33.781 ;
     RECT  11.328 33.781 13.512 33.827 ;
     RECT  4.08 31.619 4.824 34.741 ;
     RECT  11.328 33.827 11.352 34.741 ;
     RECT  11.04 34.741 11.352 34.787 ;
     RECT  3.984 34.741 4.824 34.789 ;
     RECT  3.984 34.789 5.112 34.835 ;
     RECT  6.576 31.379 6.6 35.077 ;
     RECT  7.8 33.445 9.96 35.077 ;
     RECT  6.576 35.077 9.96 35.363 ;
     RECT  2.4 31.811 2.712 35.845 ;
     RECT  12.528 33.827 13.512 35.891 ;
     RECT  2.4 35.845 2.808 36.755 ;
     RECT  6.576 35.363 8.76 37.573 ;
     RECT  9.936 35.363 9.96 38.197 ;
     RECT  11.04 34.787 11.064 38.197 ;
     RECT  9.936 38.197 11.064 38.243 ;
     RECT  13.2 35.891 13.512 38.725 ;
     RECT  0.144 36.085 0.168 38.771 ;
     RECT  5.088 34.835 5.112 38.819 ;
     RECT  6.24 37.573 8.76 39.253 ;
     RECT  10.224 38.243 11.064 39.347 ;
     RECT  12.528 38.725 13.512 39.877 ;
     RECT  10.224 39.347 10.44 42.227 ;
     RECT  2.4 36.755 2.712 42.421 ;
     RECT  5.904 39.253 8.76 42.467 ;
     RECT  2.4 42.421 2.808 42.563 ;
     RECT  10.224 42.227 10.248 43.379 ;
     RECT  0.144 44.149 0.168 44.435 ;
     RECT  12.24 39.877 13.512 44.483 ;
     RECT  6.576 42.467 8.76 44.725 ;
     RECT  10.176 43.717 10.2 44.725 ;
     RECT  6.576 44.725 10.2 45.971 ;
     RECT  13.104 44.483 13.512 46.069 ;
     RECT  13.104 46.069 13.608 46.115 ;
     RECT  10.176 45.971 10.2 46.259 ;
     RECT  13.2 46.115 13.608 47.123 ;
     RECT  6.576 45.971 8.76 47.269 ;
     RECT  13.2 47.123 13.512 47.701 ;
     RECT  6.576 47.269 8.952 48.419 ;
     RECT  3.984 34.835 4.008 48.515 ;
     RECT  13.008 47.701 13.512 49.043 ;
     RECT  6.576 48.419 6.792 49.477 ;
     RECT  7.8 48.419 8.952 49.477 ;
     RECT  6.576 49.477 8.952 49.909 ;
     RECT  5.808 49.909 8.952 50.531 ;
     RECT  3.936 50.341 3.96 50.627 ;
     RECT  5.808 50.531 8.76 50.677 ;
     RECT  11.28 48.997 11.304 51.205 ;
     RECT  11.28 51.205 11.544 51.251 ;
     RECT  13.2 49.043 13.512 51.493 ;
     RECT  14.544 47.557 14.568 51.493 ;
     RECT  0.144 51.397 0.168 51.683 ;
     RECT  13.2 51.493 14.568 51.971 ;
     RECT  5.76 50.677 8.76 52.309 ;
     RECT  10.224 51.205 10.248 52.499 ;
     RECT  5.664 52.309 8.76 53.027 ;
     RECT  11.52 51.251 11.544 53.027 ;
     RECT  5.664 53.027 6.744 53.507 ;
     RECT  13.2 51.971 14.472 53.509 ;
     RECT  7.8 53.027 8.76 54.661 ;
     RECT  0.144 53.365 0.168 54.707 ;
     RECT  5.664 53.507 6.6 54.805 ;
     RECT  7.8 54.661 8.856 54.805 ;
     RECT  5.664 54.805 8.856 54.899 ;
     RECT  5.808 54.899 8.856 54.995 ;
     RECT  9.936 55.429 9.96 55.955 ;
     RECT  13.2 53.509 14.808 55.957 ;
     RECT  2.4 42.563 2.712 56.389 ;
     RECT  0.144 56.581 0.168 56.771 ;
     RECT  13.104 55.957 14.808 57.445 ;
     RECT  2.304 56.389 2.712 57.635 ;
     RECT  0.144 57.829 0.168 58.019 ;
     RECT  13.056 57.445 14.808 58.163 ;
     RECT  10.704 58.117 10.728 58.739 ;
     RECT  13.056 58.163 14.328 58.739 ;
     RECT  13.056 58.739 14.136 59.315 ;
     RECT  5.808 54.995 6.6 59.605 ;
     RECT  7.8 54.995 8.856 59.605 ;
     RECT  13.056 59.315 13.512 60.181 ;
     RECT  5.808 59.605 8.856 60.323 ;
     RECT  5.808 60.323 6.6 60.373 ;
     RECT  7.8 60.323 8.856 60.373 ;
     RECT  5.136 60.373 6.6 61.811 ;
     RECT  7.8 60.373 9.096 61.957 ;
     RECT  10.752 59.749 10.776 61.957 ;
     RECT  7.8 61.957 10.776 62.003 ;
     RECT  5.568 61.811 6.6 62.677 ;
     RECT  7.8 62.003 8.76 62.677 ;
     RECT  12.768 60.181 13.512 62.867 ;
     RECT  5.568 62.677 8.76 63.827 ;
     RECT  9.936 62.003 10.776 63.875 ;
     RECT  9.936 63.875 9.96 64.067 ;
     RECT  0.144 64.117 0.168 64.931 ;
     RECT  5.568 63.827 6.6 64.933 ;
     RECT  7.8 63.827 8.76 64.933 ;
     RECT  7.8 64.933 9.144 65.077 ;
     RECT  7.8 65.077 9.96 65.123 ;
     RECT  5.52 64.933 6.6 66.179 ;
     RECT  5.808 66.179 6.6 66.467 ;
     RECT  11.04 65.509 11.064 66.755 ;
     RECT  12.96 62.867 13.512 66.947 ;
     RECT  5.808 66.467 5.88 67.283 ;
     RECT  9.12 65.123 9.96 67.427 ;
     RECT  0.144 67.621 0.168 67.811 ;
     RECT  13.104 66.947 13.512 67.859 ;
     RECT  9.936 67.427 9.96 68.101 ;
     RECT  10.944 67.141 10.968 68.101 ;
     RECT  9.936 68.101 10.968 68.435 ;
     RECT  13.2 67.859 13.512 68.821 ;
     RECT  5.808 67.283 5.832 68.917 ;
     RECT  7.8 65.123 8.112 68.965 ;
     RECT  13.104 68.821 13.512 69.493 ;
     RECT  0.144 69.253 0.168 69.539 ;
     RECT  12.672 69.493 13.512 69.781 ;
     RECT  10.224 68.435 10.968 70.069 ;
     RECT  7.8 68.965 8.616 70.163 ;
     RECT  5.808 68.917 6.024 71.075 ;
     RECT  5.808 71.075 5.832 71.509 ;
     RECT  7.8 70.163 8.112 71.701 ;
     RECT  5.04 71.509 5.832 71.891 ;
     RECT  0.192 71.461 0.216 72.275 ;
     RECT  10.224 70.069 11.112 72.371 ;
     RECT  12.624 69.781 13.512 72.517 ;
     RECT  7.488 71.701 8.112 72.659 ;
     RECT  2.4 57.635 2.712 72.901 ;
     RECT  5.04 71.891 5.064 72.995 ;
     RECT  2.304 72.901 2.712 73.043 ;
     RECT  12.624 72.517 14.376 73.861 ;
     RECT  9.216 70.693 9.24 73.909 ;
     RECT  10.224 72.371 10.872 73.909 ;
     RECT  6.336 73.477 6.36 74.005 ;
     RECT  9.216 73.909 10.872 74.051 ;
     RECT  2.4 73.043 2.712 74.437 ;
     RECT  5.712 74.005 6.36 74.963 ;
     RECT  12.576 73.861 14.376 75.011 ;
     RECT  3.936 72.229 3.96 75.205 ;
     RECT  2.304 74.437 2.712 75.731 ;
     RECT  5.76 74.963 6.36 75.923 ;
     RECT  3.936 75.205 4.584 76.213 ;
     RECT  5.76 75.923 5.784 76.213 ;
     RECT  3.936 76.213 5.784 76.403 ;
     RECT  9.6 74.051 10.872 76.403 ;
     RECT  5.04 76.403 5.784 76.595 ;
     RECT  3.936 76.403 3.96 76.645 ;
     RECT  5.76 76.595 5.784 77.027 ;
     RECT  9.6 76.403 10.776 77.509 ;
     RECT  9.12 77.509 10.776 77.555 ;
     RECT  3.84 76.645 3.96 77.699 ;
     RECT  10.176 77.555 10.776 77.699 ;
     RECT  9.12 77.555 9.144 78.613 ;
     RECT  10.176 77.699 10.728 78.613 ;
     RECT  6.768 77.509 6.792 79.139 ;
     RECT  9.12 78.613 10.728 79.187 ;
     RECT  3.84 77.699 3.912 79.283 ;
     RECT  12.624 75.011 14.376 79.283 ;
     RECT  9.12 79.187 9.96 79.715 ;
     RECT  12.624 79.283 13.512 80.483 ;
     RECT  3.888 79.283 3.912 80.869 ;
     RECT  9.696 79.715 9.96 81.059 ;
     RECT  9.936 81.059 9.96 81.107 ;
     RECT  3.696 80.869 3.912 81.205 ;
     RECT  7.8 72.659 8.112 81.877 ;
     RECT  3.696 81.205 3.96 82.115 ;
     RECT  13.104 80.483 13.512 82.451 ;
     RECT  2.4 75.731 2.712 82.693 ;
     RECT  10.992 81.445 11.016 83.749 ;
     RECT  10.752 83.749 11.016 83.795 ;
     RECT  6.288 83.221 6.312 84.035 ;
     RECT  2.4 82.693 3.432 84.227 ;
     RECT  7.8 81.877 8.568 84.325 ;
     RECT  6.768 84.325 6.792 85.619 ;
     RECT  2.4 84.227 3.192 85.955 ;
     RECT  7.8 84.325 9.048 86.005 ;
     RECT  10.752 83.795 10.776 86.675 ;
     RECT  2.4 85.955 3.144 86.917 ;
     RECT  2.4 86.917 4.008 87.155 ;
     RECT  3.984 87.155 4.008 87.779 ;
     RECT  6.816 86.005 9.048 87.971 ;
     RECT  7.8 87.971 9.048 88.403 ;
     RECT  2.4 87.155 2.712 95.049 ;
     RECT  7.8 88.403 8.112 95.049 ;
     RECT  13.2 82.451 13.512 95.049 ;
     RECT  2.4 95.049 2.52 95.063 ;
     RECT  7.8 95.049 7.92 95.063 ;
     RECT  13.2 95.049 13.32 95.063 ;
     RECT  2.52 2.137 3.984 2.151 ;
     RECT  2.712 2.151 3.984 10.837 ;
     RECT  4.008 7.189 5.184 11.029 ;
     RECT  5.208 8.771 6.912 10.165 ;
     RECT  5.64 10.165 6.912 11.075 ;
     RECT  4.008 11.029 5.136 14.245 ;
     RECT  2.712 11.459 3.984 14.197 ;
     RECT  8.664 11.653 9.84 12.755 ;
     RECT  2.712 14.197 3.744 17.029 ;
     RECT  5.736 14.197 7.152 14.533 ;
     RECT  11.688 14.197 12.864 14.867 ;
     RECT  6.168 14.533 7.152 15.347 ;
     RECT  11.688 14.867 13.2 15.491 ;
     RECT  5.16 15.443 6.144 18.229 ;
     RECT  2.712 17.029 3.696 17.125 ;
     RECT  6.264 17.077 7.392 19.285 ;
     RECT  13.704 21.395 15.072 23.987 ;
     RECT  6.744 22.451 7.8 22.787 ;
     RECT  6.504 22.787 7.8 24.515 ;
     RECT  3 26.387 4.08 30.277 ;
     RECT  6.168 29.365 7.44 29.605 ;
     RECT  3 30.419 4.08 30.851 ;
     RECT  12.024 30.709 13.2 33.781 ;
     RECT  13.512 30.757 14.784 30.899 ;
     RECT  2.904 30.851 4.08 31.811 ;
     RECT  5.496 31.379 6.576 31.619 ;
     RECT  6.6 31.379 7.8 35.077 ;
     RECT  2.712 31.811 4.08 34.741 ;
     RECT  9.96 33.445 11.328 34.741 ;
     RECT  11.352 33.827 12.528 34.787 ;
     RECT  2.712 34.741 3.984 35.845 ;
     RECT  9.96 34.741 11.04 38.197 ;
     RECT  11.064 34.787 12.528 35.891 ;
     RECT  5.112 34.789 6.576 37.573 ;
     RECT  4.008 34.835 5.088 38.819 ;
     RECT  8.76 35.363 9.936 38.243 ;
     RECT  2.808 35.845 3.984 36.755 ;
     RECT  2.712 36.755 3.984 42.421 ;
     RECT  5.112 37.573 6.24 38.819 ;
     RECT  8.76 38.243 10.224 43.379 ;
     RECT  11.064 38.725 12.528 39.347 ;
     RECT  5.904 38.819 6.24 39.253 ;
     RECT  12.24 39.347 12.528 39.877 ;
     RECT  2.808 42.421 3.984 42.563 ;
     RECT  2.712 42.563 3.984 48.515 ;
     RECT  8.76 43.379 10.2 43.717 ;
     RECT  8.76 43.717 10.176 44.725 ;
     RECT  8.76 45.971 10.176 46.259 ;
     RECT  8.76 46.259 8.952 47.269 ;
     RECT  13.512 47.123 13.608 47.557 ;
     RECT  13.512 47.557 14.544 51.493 ;
     RECT  6.792 48.419 7.8 49.477 ;
     RECT  2.712 50.341 3.936 50.627 ;
     RECT  8.76 50.531 8.952 51.205 ;
     RECT  8.76 51.205 10.224 52.499 ;
     RECT  10.248 51.205 11.28 51.251 ;
     RECT  10.248 51.251 11.52 52.499 ;
     RECT  6.744 53.027 7.8 53.507 ;
     RECT  6.6 53.507 7.8 54.805 ;
     RECT  6.6 54.995 7.8 59.605 ;
     RECT  8.856 55.429 9.936 55.955 ;
     RECT  0.144 56.771 0.168 57.829 ;
     RECT  6.6 60.323 7.8 62.677 ;
     RECT  8.76 62.003 9.936 64.067 ;
     RECT  6.6 63.827 7.8 66.467 ;
     RECT  8.76 64.067 9.96 64.933 ;
     RECT  9.144 64.933 9.96 65.077 ;
     RECT  8.112 65.123 9.12 67.427 ;
     RECT  9.96 65.509 11.04 66.755 ;
     RECT  9.96 66.755 10.968 67.141 ;
     RECT  9.96 67.141 10.944 68.101 ;
     RECT  0.144 67.811 0.168 69.253 ;
     RECT  13.104 67.859 13.2 68.821 ;
     RECT  11.112 70.069 12.624 72.371 ;
     RECT  8.112 70.163 8.616 70.693 ;
     RECT  8.112 70.693 9.216 74.051 ;
     RECT  9.24 70.693 10.224 73.909 ;
     RECT  2.712 72.229 3.936 76.645 ;
     RECT  3.96 72.229 5.04 72.995 ;
     RECT  12.576 72.371 12.624 73.861 ;
     RECT  7.488 72.659 7.8 73.477 ;
     RECT  2.304 73.043 2.4 74.437 ;
     RECT  6.36 73.477 7.8 75.923 ;
     RECT  8.112 74.051 9.6 77.509 ;
     RECT  5.712 74.963 5.76 75.205 ;
     RECT  4.584 75.205 5.76 76.213 ;
     RECT  3.96 76.403 5.04 76.595 ;
     RECT  2.712 76.645 3.84 79.283 ;
     RECT  6.792 77.509 7.8 79.139 ;
     RECT  8.112 77.509 9.12 79.715 ;
     RECT  9.144 77.555 10.176 78.613 ;
     RECT  2.712 79.283 3.888 80.869 ;
     RECT  2.712 80.869 3.696 82.115 ;
     RECT  2.712 82.115 3.432 82.693 ;
     RECT  6.312 83.221 7.8 84.035 ;
     RECT  6.768 84.035 7.8 84.325 ;
     RECT  6.792 84.325 7.8 85.619 ;
     RECT  6.816 85.619 7.8 86.005 ;
     RECT  3.144 85.955 3.192 86.917 ;
     RECT  2.712 87.155 3.984 87.779 ;
  END
END ot_qfd_vm_xrelay_t
END LIBRARY
